VERSION 5.8 ;
BUSBITCHARS "[]" ;
DIVIDERCHAR "/" ;
UNITS
    DATABASE MICRONS 1000 ;
END UNITS

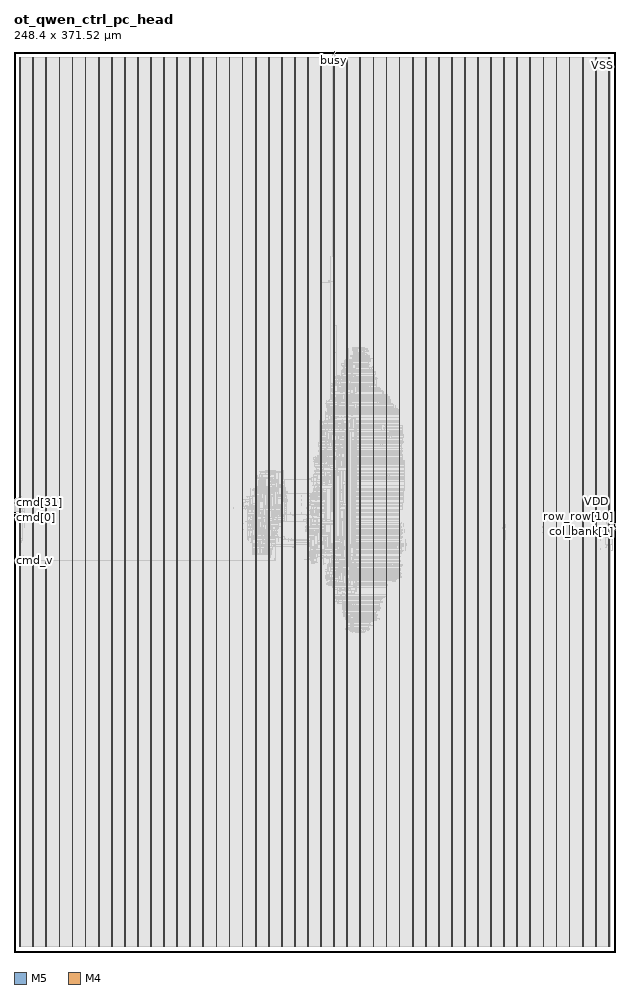
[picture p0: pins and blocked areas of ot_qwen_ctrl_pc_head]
MACRO ot_qwen_ctrl_pc_head
  FOREIGN ot_qwen_ctrl_pc_head 0 0 ;
  CLASS BLOCK ;
  SIZE 248.4 BY 371.52 ;
  PIN busy
    DIRECTION OUTPUT ;
    USE SIGNAL ;
    PORT
      LAYER M5 ;
        RECT  132.144 371.436 132.168 371.52 ;
    END
  END busy
  PIN clk
    DIRECTION INPUT ;
    USE SIGNAL ;
    PORT
      LAYER M5 ;
        RECT  132.24 371.436 132.264 371.52 ;
    END
  END clk
  PIN cmd[0]
    DIRECTION INPUT ;
    USE SIGNAL ;
    PORT
      LAYER M4 ;
        RECT  0 182.64 0.084 182.664 ;
    END
  END cmd[0]
  PIN cmd[10]
    DIRECTION INPUT ;
    USE SIGNAL ;
    PORT
      LAYER M4 ;
        RECT  0 183.6 0.084 183.624 ;
    END
  END cmd[10]
  PIN cmd[11]
    DIRECTION INPUT ;
    USE SIGNAL ;
    PORT
      LAYER M4 ;
        RECT  0 183.696 0.084 183.72 ;
    END
  END cmd[11]
  PIN cmd[12]
    DIRECTION INPUT ;
    USE SIGNAL ;
    PORT
      LAYER M4 ;
        RECT  0 183.792 0.084 183.816 ;
    END
  END cmd[12]
  PIN cmd[13]
    DIRECTION INPUT ;
    USE SIGNAL ;
    PORT
      LAYER M4 ;
        RECT  0 183.888 0.084 183.912 ;
    END
  END cmd[13]
  PIN cmd[14]
    DIRECTION INPUT ;
    USE SIGNAL ;
    PORT
      LAYER M4 ;
        RECT  0 183.984 0.084 184.008 ;
    END
  END cmd[14]
  PIN cmd[15]
    DIRECTION INPUT ;
    USE SIGNAL ;
    PORT
      LAYER M4 ;
        RECT  0 184.08 0.084 184.104 ;
    END
  END cmd[15]
  PIN cmd[16]
    DIRECTION INPUT ;
    USE SIGNAL ;
    PORT
      LAYER M4 ;
        RECT  0 184.176 0.084 184.2 ;
    END
  END cmd[16]
  PIN cmd[17]
    DIRECTION INPUT ;
    USE SIGNAL ;
    PORT
      LAYER M4 ;
        RECT  0 184.272 0.084 184.296 ;
    END
  END cmd[17]
  PIN cmd[18]
    DIRECTION INPUT ;
    USE SIGNAL ;
    PORT
      LAYER M4 ;
        RECT  0 184.368 0.084 184.392 ;
    END
  END cmd[18]
  PIN cmd[19]
    DIRECTION INPUT ;
    USE SIGNAL ;
    PORT
      LAYER M4 ;
        RECT  0 184.464 0.084 184.488 ;
    END
  END cmd[19]
  PIN cmd[1]
    DIRECTION INPUT ;
    USE SIGNAL ;
    PORT
      LAYER M4 ;
        RECT  0 182.736 0.084 182.76 ;
    END
  END cmd[1]
  PIN cmd[20]
    DIRECTION INPUT ;
    USE SIGNAL ;
    PORT
      LAYER M4 ;
        RECT  0 184.56 0.084 184.584 ;
    END
  END cmd[20]
  PIN cmd[21]
    DIRECTION INPUT ;
    USE SIGNAL ;
    PORT
      LAYER M4 ;
        RECT  0 184.656 0.084 184.68 ;
    END
  END cmd[21]
  PIN cmd[22]
    DIRECTION INPUT ;
    USE SIGNAL ;
    PORT
      LAYER M4 ;
        RECT  0 184.752 0.084 184.776 ;
    END
  END cmd[22]
  PIN cmd[23]
    DIRECTION INPUT ;
    USE SIGNAL ;
    PORT
      LAYER M4 ;
        RECT  0 184.848 0.084 184.872 ;
    END
  END cmd[23]
  PIN cmd[24]
    DIRECTION INPUT ;
    USE SIGNAL ;
    PORT
      LAYER M4 ;
        RECT  0 184.944 0.084 184.968 ;
    END
  END cmd[24]
  PIN cmd[25]
    DIRECTION INPUT ;
    USE SIGNAL ;
    PORT
      LAYER M4 ;
        RECT  0 185.04 0.084 185.064 ;
    END
  END cmd[25]
  PIN cmd[26]
    DIRECTION INPUT ;
    USE SIGNAL ;
    PORT
      LAYER M4 ;
        RECT  0 185.136 0.084 185.16 ;
    END
  END cmd[26]
  PIN cmd[27]
    DIRECTION INPUT ;
    USE SIGNAL ;
    PORT
      LAYER M4 ;
        RECT  0 185.232 0.084 185.256 ;
    END
  END cmd[27]
  PIN cmd[28]
    DIRECTION INPUT ;
    USE SIGNAL ;
    PORT
      LAYER M4 ;
        RECT  0 185.328 0.084 185.352 ;
    END
  END cmd[28]
  PIN cmd[29]
    DIRECTION INPUT ;
    USE SIGNAL ;
    PORT
      LAYER M4 ;
        RECT  0 185.424 0.084 185.448 ;
    END
  END cmd[29]
  PIN cmd[2]
    DIRECTION INPUT ;
    USE SIGNAL ;
    PORT
      LAYER M4 ;
        RECT  0 182.832 0.084 182.856 ;
    END
  END cmd[2]
  PIN cmd[30]
    DIRECTION INPUT ;
    USE SIGNAL ;
    PORT
      LAYER M4 ;
        RECT  0 185.52 0.084 185.544 ;
    END
  END cmd[30]
  PIN cmd[31]
    DIRECTION INPUT ;
    USE SIGNAL ;
    PORT
      LAYER M4 ;
        RECT  0 185.616 0.084 185.64 ;
    END
  END cmd[31]
  PIN cmd[3]
    DIRECTION INPUT ;
    USE SIGNAL ;
    PORT
      LAYER M4 ;
        RECT  0 182.928 0.084 182.952 ;
    END
  END cmd[3]
  PIN cmd[4]
    DIRECTION INPUT ;
    USE SIGNAL ;
    PORT
      LAYER M4 ;
        RECT  0 183.024 0.084 183.048 ;
    END
  END cmd[4]
  PIN cmd[5]
    DIRECTION INPUT ;
    USE SIGNAL ;
    PORT
      LAYER M4 ;
        RECT  0 183.12 0.084 183.144 ;
    END
  END cmd[5]
  PIN cmd[6]
    DIRECTION INPUT ;
    USE SIGNAL ;
    PORT
      LAYER M4 ;
        RECT  0 183.216 0.084 183.24 ;
    END
  END cmd[6]
  PIN cmd[7]
    DIRECTION INPUT ;
    USE SIGNAL ;
    PORT
      LAYER M4 ;
        RECT  0 183.312 0.084 183.336 ;
    END
  END cmd[7]
  PIN cmd[8]
    DIRECTION INPUT ;
    USE SIGNAL ;
    PORT
      LAYER M4 ;
        RECT  0 183.408 0.084 183.432 ;
    END
  END cmd[8]
  PIN cmd[9]
    DIRECTION INPUT ;
    USE SIGNAL ;
    PORT
      LAYER M4 ;
        RECT  0 183.504 0.084 183.528 ;
    END
  END cmd[9]
  PIN cmd_credit
    DIRECTION OUTPUT ;
    USE SIGNAL ;
    PORT
      LAYER M4 ;
        RECT  0 161.52 0.084 161.544 ;
    END
  END cmd_credit
  PIN cmd_v
    DIRECTION INPUT ;
    USE SIGNAL ;
    PORT
      LAYER M4 ;
        RECT  0 161.616 0.084 161.64 ;
    END
  END cmd_v
  PIN col_bank[0]
    DIRECTION OUTPUT ;
    USE SIGNAL ;
    PORT
      LAYER M4 ;
        RECT  248.316 173.52 248.4 173.544 ;
    END
  END col_bank[0]
  PIN col_bank[1]
    DIRECTION OUTPUT ;
    USE SIGNAL ;
    PORT
      LAYER M4 ;
        RECT  248.316 173.616 248.4 173.64 ;
    END
  END col_bank[1]
  PIN col_bank[2]
    DIRECTION OUTPUT ;
    USE SIGNAL ;
    PORT
      LAYER M4 ;
        RECT  248.316 173.712 248.4 173.736 ;
    END
  END col_bank[2]
  PIN col_bank[3]
    DIRECTION OUTPUT ;
    USE SIGNAL ;
    PORT
      LAYER M4 ;
        RECT  248.316 173.808 248.4 173.832 ;
    END
  END col_bank[3]
  PIN col_bank[4]
    DIRECTION OUTPUT ;
    USE SIGNAL ;
    PORT
      LAYER M4 ;
        RECT  248.316 173.904 248.4 173.928 ;
    END
  END col_bank[4]
  PIN col_col[0]
    DIRECTION OUTPUT ;
    USE SIGNAL ;
    PORT
      LAYER M4 ;
        RECT  248.316 174 248.4 174.024 ;
    END
  END col_col[0]
  PIN col_col[1]
    DIRECTION OUTPUT ;
    USE SIGNAL ;
    PORT
      LAYER M4 ;
        RECT  248.316 174.096 248.4 174.12 ;
    END
  END col_col[1]
  PIN col_col[2]
    DIRECTION OUTPUT ;
    USE SIGNAL ;
    PORT
      LAYER M4 ;
        RECT  248.316 174.192 248.4 174.216 ;
    END
  END col_col[2]
  PIN col_col[3]
    DIRECTION OUTPUT ;
    USE SIGNAL ;
    PORT
      LAYER M4 ;
        RECT  248.316 174.288 248.4 174.312 ;
    END
  END col_col[3]
  PIN col_col[4]
    DIRECTION OUTPUT ;
    USE SIGNAL ;
    PORT
      LAYER M4 ;
        RECT  248.316 174.384 248.4 174.408 ;
    END
  END col_col[4]
  PIN col_v
    DIRECTION OUTPUT ;
    USE SIGNAL ;
    PORT
      LAYER M4 ;
        RECT  248.316 174.48 248.4 174.504 ;
    END
  END col_v
  PIN col_we
    DIRECTION OUTPUT ;
    USE SIGNAL ;
    PORT
      LAYER M4 ;
        RECT  248.316 174.576 248.4 174.6 ;
    END
  END col_we
  PIN fault
    DIRECTION OUTPUT ;
    USE SIGNAL ;
    PORT
      LAYER M5 ;
        RECT  132.336 371.436 132.36 371.52 ;
    END
  END fault
  PIN read_credit[0]
    DIRECTION INPUT ;
    USE SIGNAL ;
    PORT
      LAYER M4 ;
        RECT  0 161.712 0.084 161.736 ;
    END
  END read_credit[0]
  PIN read_credit[1]
    DIRECTION INPUT ;
    USE SIGNAL ;
    PORT
      LAYER M4 ;
        RECT  0 161.808 0.084 161.832 ;
    END
  END read_credit[1]
  PIN read_credit[2]
    DIRECTION INPUT ;
    USE SIGNAL ;
    PORT
      LAYER M4 ;
        RECT  0 161.904 0.084 161.928 ;
    END
  END read_credit[2]
  PIN row_bank[0]
    DIRECTION OUTPUT ;
    USE SIGNAL ;
    PORT
      LAYER M4 ;
        RECT  248.316 174.672 248.4 174.696 ;
    END
  END row_bank[0]
  PIN row_bank[1]
    DIRECTION OUTPUT ;
    USE SIGNAL ;
    PORT
      LAYER M4 ;
        RECT  248.316 174.768 248.4 174.792 ;
    END
  END row_bank[1]
  PIN row_bank[2]
    DIRECTION OUTPUT ;
    USE SIGNAL ;
    PORT
      LAYER M4 ;
        RECT  248.316 174.864 248.4 174.888 ;
    END
  END row_bank[2]
  PIN row_bank[3]
    DIRECTION OUTPUT ;
    USE SIGNAL ;
    PORT
      LAYER M4 ;
        RECT  248.316 174.96 248.4 174.984 ;
    END
  END row_bank[3]
  PIN row_bank[4]
    DIRECTION OUTPUT ;
    USE SIGNAL ;
    PORT
      LAYER M4 ;
        RECT  248.316 175.056 248.4 175.08 ;
    END
  END row_bank[4]
  PIN row_op[0]
    DIRECTION OUTPUT ;
    USE SIGNAL ;
    PORT
      LAYER M4 ;
        RECT  248.316 175.152 248.4 175.176 ;
    END
  END row_op[0]
  PIN row_op[1]
    DIRECTION OUTPUT ;
    USE SIGNAL ;
    PORT
      LAYER M4 ;
        RECT  248.316 175.248 248.4 175.272 ;
    END
  END row_op[1]
  PIN row_op[2]
    DIRECTION OUTPUT ;
    USE SIGNAL ;
    PORT
      LAYER M4 ;
        RECT  248.316 175.344 248.4 175.368 ;
    END
  END row_op[2]
  PIN row_row[0]
    DIRECTION OUTPUT ;
    USE SIGNAL ;
    PORT
      LAYER M4 ;
        RECT  248.316 175.44 248.4 175.464 ;
    END
  END row_row[0]
  PIN row_row[10]
    DIRECTION OUTPUT ;
    USE SIGNAL ;
    PORT
      LAYER M4 ;
        RECT  248.316 176.4 248.4 176.424 ;
    END
  END row_row[10]
  PIN row_row[11]
    DIRECTION OUTPUT ;
    USE SIGNAL ;
    PORT
      LAYER M4 ;
        RECT  248.316 176.496 248.4 176.52 ;
    END
  END row_row[11]
  PIN row_row[12]
    DIRECTION OUTPUT ;
    USE SIGNAL ;
    PORT
      LAYER M4 ;
        RECT  248.316 179.664 248.4 179.688 ;
    END
  END row_row[12]
  PIN row_row[13]
    DIRECTION OUTPUT ;
    USE SIGNAL ;
    PORT
      LAYER M4 ;
        RECT  248.316 179.76 248.4 179.784 ;
    END
  END row_row[13]
  PIN row_row[14]
    DIRECTION OUTPUT ;
    USE SIGNAL ;
    PORT
      LAYER M4 ;
        RECT  248.316 179.856 248.4 179.88 ;
    END
  END row_row[14]
  PIN row_row[15]
    DIRECTION OUTPUT ;
    USE SIGNAL ;
    PORT
      LAYER M4 ;
        RECT  248.316 179.952 248.4 179.976 ;
    END
  END row_row[15]
  PIN row_row[16]
    DIRECTION OUTPUT ;
    USE SIGNAL ;
    PORT
      LAYER M4 ;
        RECT  248.316 180.048 248.4 180.072 ;
    END
  END row_row[16]
  PIN row_row[17]
    DIRECTION OUTPUT ;
    USE SIGNAL ;
    PORT
      LAYER M4 ;
        RECT  248.316 180.144 248.4 180.168 ;
    END
  END row_row[17]
  PIN row_row[18]
    DIRECTION OUTPUT ;
    USE SIGNAL ;
    PORT
      LAYER M4 ;
        RECT  248.316 180.24 248.4 180.264 ;
    END
  END row_row[18]
  PIN row_row[1]
    DIRECTION OUTPUT ;
    USE SIGNAL ;
    PORT
      LAYER M4 ;
        RECT  248.316 175.536 248.4 175.56 ;
    END
  END row_row[1]
  PIN row_row[2]
    DIRECTION OUTPUT ;
    USE SIGNAL ;
    PORT
      LAYER M4 ;
        RECT  248.316 175.632 248.4 175.656 ;
    END
  END row_row[2]
  PIN row_row[3]
    DIRECTION OUTPUT ;
    USE SIGNAL ;
    PORT
      LAYER M4 ;
        RECT  248.316 175.728 248.4 175.752 ;
    END
  END row_row[3]
  PIN row_row[4]
    DIRECTION OUTPUT ;
    USE SIGNAL ;
    PORT
      LAYER M4 ;
        RECT  248.316 175.824 248.4 175.848 ;
    END
  END row_row[4]
  PIN row_row[5]
    DIRECTION OUTPUT ;
    USE SIGNAL ;
    PORT
      LAYER M4 ;
        RECT  248.316 175.92 248.4 175.944 ;
    END
  END row_row[5]
  PIN row_row[6]
    DIRECTION OUTPUT ;
    USE SIGNAL ;
    PORT
      LAYER M4 ;
        RECT  248.316 176.016 248.4 176.04 ;
    END
  END row_row[6]
  PIN row_row[7]
    DIRECTION OUTPUT ;
    USE SIGNAL ;
    PORT
      LAYER M4 ;
        RECT  248.316 176.112 248.4 176.136 ;
    END
  END row_row[7]
  PIN row_row[8]
    DIRECTION OUTPUT ;
    USE SIGNAL ;
    PORT
      LAYER M4 ;
        RECT  248.316 176.208 248.4 176.232 ;
    END
  END row_row[8]
  PIN row_row[9]
    DIRECTION OUTPUT ;
    USE SIGNAL ;
    PORT
      LAYER M4 ;
        RECT  248.316 176.304 248.4 176.328 ;
    END
  END row_row[9]
  PIN row_v
    DIRECTION OUTPUT ;
    USE SIGNAL ;
    PORT
      LAYER M4 ;
        RECT  248.316 180.336 248.4 180.36 ;
    END
  END row_v
  PIN rst_n
    DIRECTION INPUT ;
    USE SIGNAL ;
    PORT
      LAYER M5 ;
        RECT  132.432 371.436 132.456 371.52 ;
    END
  END rst_n
  PIN VDD
    DIRECTION INOUT ;
    USE POWER ;
    PORT
      LAYER M5 ;
        RECT  245.592 2.151 245.712 369.369 ;
        RECT  240.192 2.151 240.312 369.369 ;
        RECT  234.792 2.151 234.912 369.369 ;
        RECT  229.392 2.151 229.512 369.369 ;
        RECT  223.992 2.151 224.112 369.369 ;
        RECT  218.592 2.151 218.712 369.369 ;
        RECT  213.192 2.151 213.312 369.369 ;
        RECT  207.792 2.151 207.912 369.369 ;
        RECT  202.392 2.151 202.512 369.369 ;
        RECT  196.992 2.151 197.112 369.369 ;
        RECT  191.592 2.151 191.712 369.369 ;
        RECT  186.192 2.151 186.312 369.369 ;
        RECT  180.792 2.151 180.912 369.369 ;
        RECT  175.392 2.151 175.512 369.369 ;
        RECT  169.992 2.151 170.112 369.369 ;
        RECT  164.592 2.151 164.712 369.369 ;
        RECT  159.192 2.151 159.312 369.369 ;
        RECT  153.792 2.151 153.912 369.369 ;
        RECT  148.392 2.151 148.512 369.369 ;
        RECT  142.992 2.151 143.112 369.369 ;
        RECT  137.592 2.151 137.712 369.369 ;
        RECT  132.192 2.151 132.312 369.369 ;
        RECT  126.792 2.151 126.912 369.369 ;
        RECT  121.392 2.151 121.512 369.369 ;
        RECT  115.992 2.151 116.112 369.369 ;
        RECT  110.592 2.151 110.712 369.369 ;
        RECT  105.192 2.151 105.312 369.369 ;
        RECT  99.792 2.151 99.912 369.369 ;
        RECT  94.392 2.151 94.512 369.369 ;
        RECT  88.992 2.151 89.112 369.369 ;
        RECT  83.592 2.151 83.712 369.369 ;
        RECT  78.192 2.151 78.312 369.369 ;
        RECT  72.792 2.151 72.912 369.369 ;
        RECT  67.392 2.151 67.512 369.369 ;
        RECT  61.992 2.151 62.112 369.369 ;
        RECT  56.592 2.151 56.712 369.369 ;
        RECT  51.192 2.151 51.312 369.369 ;
        RECT  45.792 2.151 45.912 369.369 ;
        RECT  40.392 2.151 40.512 369.369 ;
        RECT  34.992 2.151 35.112 369.369 ;
        RECT  29.592 2.151 29.712 369.369 ;
        RECT  24.192 2.151 24.312 369.369 ;
        RECT  18.792 2.151 18.912 369.369 ;
        RECT  13.392 2.151 13.512 369.369 ;
        RECT  7.992 2.151 8.112 369.369 ;
        RECT  2.592 2.151 2.712 369.369 ;
    END
  END VDD
  PIN VSS
    DIRECTION INOUT ;
    USE GROUND ;
    PORT
      LAYER M5 ;
        RECT  245.4 2.137 245.52 369.383 ;
        RECT  240 2.137 240.12 369.383 ;
        RECT  234.6 2.137 234.72 369.383 ;
        RECT  229.2 2.137 229.32 369.383 ;
        RECT  223.8 2.137 223.92 369.383 ;
        RECT  218.4 2.137 218.52 369.383 ;
        RECT  213 2.137 213.12 369.383 ;
        RECT  207.6 2.137 207.72 369.383 ;
        RECT  202.2 2.137 202.32 369.383 ;
        RECT  196.8 2.137 196.92 369.383 ;
        RECT  191.4 2.137 191.52 369.383 ;
        RECT  186 2.137 186.12 369.383 ;
        RECT  180.6 2.137 180.72 369.383 ;
        RECT  175.2 2.137 175.32 369.383 ;
        RECT  169.8 2.137 169.92 369.383 ;
        RECT  164.4 2.137 164.52 369.383 ;
        RECT  159 2.137 159.12 369.383 ;
        RECT  153.6 2.137 153.72 369.383 ;
        RECT  148.2 2.137 148.32 369.383 ;
        RECT  142.8 2.137 142.92 369.383 ;
        RECT  137.4 2.137 137.52 369.383 ;
        RECT  132 2.137 132.12 369.383 ;
        RECT  126.6 2.137 126.72 369.383 ;
        RECT  121.2 2.137 121.32 369.383 ;
        RECT  115.8 2.137 115.92 369.383 ;
        RECT  110.4 2.137 110.52 369.383 ;
        RECT  105 2.137 105.12 369.383 ;
        RECT  99.6 2.137 99.72 369.383 ;
        RECT  94.2 2.137 94.32 369.383 ;
        RECT  88.8 2.137 88.92 369.383 ;
        RECT  83.4 2.137 83.52 369.383 ;
        RECT  78 2.137 78.12 369.383 ;
        RECT  72.6 2.137 72.72 369.383 ;
        RECT  67.2 2.137 67.32 369.383 ;
        RECT  61.8 2.137 61.92 369.383 ;
        RECT  56.4 2.137 56.52 369.383 ;
        RECT  51 2.137 51.12 369.383 ;
        RECT  45.6 2.137 45.72 369.383 ;
        RECT  40.2 2.137 40.32 369.383 ;
        RECT  34.8 2.137 34.92 369.383 ;
        RECT  29.4 2.137 29.52 369.383 ;
        RECT  24 2.137 24.12 369.383 ;
        RECT  18.6 2.137 18.72 369.383 ;
        RECT  13.2 2.137 13.32 369.383 ;
        RECT  7.8 2.137 7.92 369.383 ;
        RECT  2.4 2.137 2.52 369.383 ;
    END
  END VSS
  OBS
    LAYER RVTN ;
     RECT  2.16 2.16 246.24 2.295 ;
     RECT  2.16 2.565 246.24 2.835 ;
     RECT  2.16 3.105 246.24 3.375 ;
     RECT  2.16 3.645 246.24 3.915 ;
     RECT  2.16 4.185 246.24 4.455 ;
     RECT  2.16 4.725 246.24 4.995 ;
     RECT  2.16 5.265 246.24 5.535 ;
     RECT  2.16 5.805 246.24 6.075 ;
     RECT  2.16 6.345 246.24 6.615 ;
     RECT  2.16 6.885 246.24 7.155 ;
     RECT  2.16 7.425 246.24 7.695 ;
     RECT  2.16 7.965 246.24 8.235 ;
     RECT  2.16 8.505 246.24 8.775 ;
     RECT  2.16 9.045 246.24 9.315 ;
     RECT  2.16 9.585 246.24 9.855 ;
     RECT  2.16 10.125 246.24 10.395 ;
     RECT  2.16 10.665 246.24 10.935 ;
     RECT  2.16 11.205 246.24 11.475 ;
     RECT  2.16 11.745 246.24 12.015 ;
     RECT  2.16 12.285 246.24 12.555 ;
     RECT  2.16 12.825 246.24 13.095 ;
     RECT  2.16 13.365 246.24 13.635 ;
     RECT  2.16 13.905 246.24 14.175 ;
     RECT  2.16 14.445 246.24 14.715 ;
     RECT  2.16 14.985 246.24 15.255 ;
     RECT  2.16 15.525 246.24 15.795 ;
     RECT  2.16 16.065 246.24 16.335 ;
     RECT  2.16 16.605 246.24 16.875 ;
     RECT  2.16 17.145 246.24 17.415 ;
     RECT  2.16 17.685 246.24 17.955 ;
     RECT  2.16 18.225 246.24 18.495 ;
     RECT  2.16 18.765 246.24 19.035 ;
     RECT  2.16 19.305 246.24 19.575 ;
     RECT  2.16 19.845 246.24 20.115 ;
     RECT  2.16 20.385 246.24 20.655 ;
     RECT  2.16 20.925 246.24 21.195 ;
     RECT  2.16 21.465 246.24 21.735 ;
     RECT  2.16 22.005 246.24 22.275 ;
     RECT  2.16 22.545 246.24 22.815 ;
     RECT  2.16 23.085 246.24 23.355 ;
     RECT  2.16 23.625 246.24 23.895 ;
     RECT  2.16 24.165 246.24 24.435 ;
     RECT  2.16 24.705 246.24 24.975 ;
     RECT  2.16 25.245 246.24 25.515 ;
     RECT  2.16 25.785 246.24 26.055 ;
     RECT  2.16 26.325 246.24 26.595 ;
     RECT  2.16 26.865 246.24 27.135 ;
     RECT  2.16 27.405 246.24 27.675 ;
     RECT  2.16 27.945 246.24 28.215 ;
     RECT  2.16 28.485 246.24 28.755 ;
     RECT  2.16 29.025 246.24 29.295 ;
     RECT  2.16 29.565 246.24 29.835 ;
     RECT  2.16 30.105 246.24 30.375 ;
     RECT  2.16 30.645 246.24 30.915 ;
     RECT  2.16 31.185 246.24 31.455 ;
     RECT  2.16 31.725 246.24 31.995 ;
     RECT  2.16 32.265 246.24 32.535 ;
     RECT  2.16 32.805 246.24 33.075 ;
     RECT  2.16 33.345 246.24 33.615 ;
     RECT  2.16 33.885 246.24 34.155 ;
     RECT  2.16 34.425 246.24 34.695 ;
     RECT  2.16 34.965 246.24 35.235 ;
     RECT  2.16 35.505 246.24 35.775 ;
     RECT  2.16 36.045 246.24 36.315 ;
     RECT  2.16 36.585 246.24 36.855 ;
     RECT  2.16 37.125 246.24 37.395 ;
     RECT  2.16 37.665 246.24 37.935 ;
     RECT  2.16 38.205 246.24 38.475 ;
     RECT  2.16 38.745 246.24 39.015 ;
     RECT  2.16 39.285 246.24 39.555 ;
     RECT  2.16 39.825 246.24 40.095 ;
     RECT  2.16 40.365 246.24 40.635 ;
     RECT  2.16 40.905 246.24 41.175 ;
     RECT  2.16 41.445 246.24 41.715 ;
     RECT  2.16 41.985 246.24 42.255 ;
     RECT  2.16 42.525 246.24 42.795 ;
     RECT  2.16 43.065 246.24 43.335 ;
     RECT  2.16 43.605 246.24 43.875 ;
     RECT  2.16 44.145 246.24 44.415 ;
     RECT  2.16 44.685 246.24 44.955 ;
     RECT  2.16 45.225 246.24 45.495 ;
     RECT  2.16 45.765 246.24 46.035 ;
     RECT  2.16 46.305 246.24 46.575 ;
     RECT  2.16 46.845 246.24 47.115 ;
     RECT  2.16 47.385 246.24 47.655 ;
     RECT  2.16 47.925 246.24 48.195 ;
     RECT  2.16 48.465 246.24 48.735 ;
     RECT  2.16 49.005 246.24 49.275 ;
     RECT  2.16 49.545 246.24 49.815 ;
     RECT  2.16 50.085 246.24 50.355 ;
     RECT  2.16 50.625 246.24 50.895 ;
     RECT  2.16 51.165 246.24 51.435 ;
     RECT  2.16 51.705 246.24 51.975 ;
     RECT  2.16 52.245 246.24 52.515 ;
     RECT  2.16 52.785 246.24 53.055 ;
     RECT  2.16 53.325 246.24 53.595 ;
     RECT  2.16 53.865 246.24 54.135 ;
     RECT  2.16 54.405 246.24 54.675 ;
     RECT  2.16 54.945 246.24 55.215 ;
     RECT  2.16 55.485 246.24 55.755 ;
     RECT  2.16 56.025 246.24 56.295 ;
     RECT  2.16 56.565 246.24 56.835 ;
     RECT  2.16 57.105 246.24 57.375 ;
     RECT  2.16 57.645 246.24 57.915 ;
     RECT  2.16 58.185 246.24 58.455 ;
     RECT  2.16 58.725 246.24 58.995 ;
     RECT  2.16 59.265 246.24 59.535 ;
     RECT  2.16 59.805 246.24 60.075 ;
     RECT  2.16 60.345 246.24 60.615 ;
     RECT  2.16 60.885 246.24 61.155 ;
     RECT  2.16 61.425 246.24 61.695 ;
     RECT  2.16 61.965 246.24 62.235 ;
     RECT  2.16 62.505 246.24 62.775 ;
     RECT  2.16 63.045 246.24 63.315 ;
     RECT  2.16 63.585 246.24 63.855 ;
     RECT  2.16 64.125 246.24 64.395 ;
     RECT  2.16 64.665 246.24 64.935 ;
     RECT  2.16 65.205 246.24 65.475 ;
     RECT  2.16 65.745 246.24 66.015 ;
     RECT  2.16 66.285 246.24 66.555 ;
     RECT  2.16 66.825 246.24 67.095 ;
     RECT  2.16 67.365 246.24 67.635 ;
     RECT  2.16 67.905 246.24 68.175 ;
     RECT  2.16 68.445 246.24 68.715 ;
     RECT  2.16 68.985 246.24 69.255 ;
     RECT  2.16 69.525 246.24 69.795 ;
     RECT  2.16 70.065 246.24 70.335 ;
     RECT  2.16 70.605 246.24 70.875 ;
     RECT  2.16 71.145 246.24 71.415 ;
     RECT  2.16 71.685 246.24 71.955 ;
     RECT  2.16 72.225 246.24 72.495 ;
     RECT  2.16 72.765 246.24 73.035 ;
     RECT  2.16 73.305 246.24 73.575 ;
     RECT  2.16 73.845 246.24 74.115 ;
     RECT  2.16 74.385 246.24 74.655 ;
     RECT  2.16 74.925 246.24 75.195 ;
     RECT  2.16 75.465 246.24 75.735 ;
     RECT  2.16 76.005 246.24 76.275 ;
     RECT  2.16 76.545 246.24 76.815 ;
     RECT  2.16 77.085 246.24 77.355 ;
     RECT  2.16 77.625 246.24 77.895 ;
     RECT  2.16 78.165 246.24 78.435 ;
     RECT  2.16 78.705 246.24 78.975 ;
     RECT  2.16 79.245 246.24 79.515 ;
     RECT  2.16 79.785 246.24 80.055 ;
     RECT  2.16 80.325 246.24 80.595 ;
     RECT  2.16 80.865 246.24 81.135 ;
     RECT  2.16 81.405 246.24 81.675 ;
     RECT  2.16 81.945 246.24 82.215 ;
     RECT  2.16 82.485 246.24 82.755 ;
     RECT  2.16 83.025 246.24 83.295 ;
     RECT  2.16 83.565 246.24 83.835 ;
     RECT  2.16 84.105 246.24 84.375 ;
     RECT  2.16 84.645 246.24 84.915 ;
     RECT  2.16 85.185 246.24 85.455 ;
     RECT  2.16 85.725 246.24 85.995 ;
     RECT  2.16 86.265 246.24 86.535 ;
     RECT  2.16 86.805 246.24 87.075 ;
     RECT  2.16 87.345 246.24 87.615 ;
     RECT  2.16 87.885 246.24 88.155 ;
     RECT  2.16 88.425 246.24 88.695 ;
     RECT  2.16 88.965 246.24 89.235 ;
     RECT  2.16 89.505 246.24 89.775 ;
     RECT  2.16 90.045 246.24 90.315 ;
     RECT  2.16 90.585 246.24 90.855 ;
     RECT  2.16 91.125 246.24 91.395 ;
     RECT  2.16 91.665 246.24 91.935 ;
     RECT  2.16 92.205 246.24 92.475 ;
     RECT  2.16 92.745 246.24 93.015 ;
     RECT  2.16 93.285 246.24 93.555 ;
     RECT  2.16 93.825 246.24 94.095 ;
     RECT  2.16 94.365 246.24 94.635 ;
     RECT  2.16 94.905 246.24 95.175 ;
     RECT  2.16 95.445 246.24 95.715 ;
     RECT  2.16 95.985 246.24 96.255 ;
     RECT  2.16 96.525 246.24 96.795 ;
     RECT  2.16 97.065 246.24 97.335 ;
     RECT  2.16 97.605 246.24 97.875 ;
     RECT  2.16 98.145 246.24 98.415 ;
     RECT  2.16 98.685 246.24 98.955 ;
     RECT  2.16 99.225 246.24 99.495 ;
     RECT  2.16 99.765 246.24 100.035 ;
     RECT  2.16 100.305 246.24 100.575 ;
     RECT  2.16 100.845 246.24 101.115 ;
     RECT  2.16 101.385 246.24 101.655 ;
     RECT  2.16 101.925 246.24 102.195 ;
     RECT  2.16 102.465 246.24 102.735 ;
     RECT  2.16 103.005 246.24 103.275 ;
     RECT  2.16 103.545 246.24 103.815 ;
     RECT  2.16 104.085 246.24 104.355 ;
     RECT  2.16 104.625 246.24 104.895 ;
     RECT  2.16 105.165 246.24 105.435 ;
     RECT  2.16 105.705 246.24 105.975 ;
     RECT  2.16 106.245 246.24 106.515 ;
     RECT  2.16 106.785 246.24 107.055 ;
     RECT  2.16 107.325 246.24 107.595 ;
     RECT  2.16 107.865 246.24 108.135 ;
     RECT  2.16 108.405 246.24 108.675 ;
     RECT  2.16 108.945 246.24 109.215 ;
     RECT  2.16 109.485 246.24 109.755 ;
     RECT  2.16 110.025 246.24 110.295 ;
     RECT  2.16 110.565 246.24 110.835 ;
     RECT  2.16 111.105 246.24 111.375 ;
     RECT  2.16 111.645 246.24 111.915 ;
     RECT  2.16 112.185 246.24 112.455 ;
     RECT  2.16 112.725 246.24 112.995 ;
     RECT  2.16 113.265 246.24 113.535 ;
     RECT  2.16 113.805 246.24 114.075 ;
     RECT  2.16 114.345 246.24 114.615 ;
     RECT  2.16 114.885 246.24 115.155 ;
     RECT  2.16 115.425 246.24 115.695 ;
     RECT  2.16 115.965 246.24 116.235 ;
     RECT  2.16 116.505 246.24 116.775 ;
     RECT  2.16 117.045 246.24 117.315 ;
     RECT  2.16 117.585 246.24 117.855 ;
     RECT  2.16 118.125 246.24 118.395 ;
     RECT  2.16 118.665 246.24 118.935 ;
     RECT  2.16 119.205 246.24 119.475 ;
     RECT  2.16 119.745 246.24 120.015 ;
     RECT  2.16 120.285 246.24 120.555 ;
     RECT  2.16 120.825 246.24 121.095 ;
     RECT  2.16 121.365 246.24 121.635 ;
     RECT  2.16 121.905 246.24 122.175 ;
     RECT  2.16 122.445 246.24 122.715 ;
     RECT  2.16 122.985 246.24 123.255 ;
     RECT  2.16 123.525 246.24 123.795 ;
     RECT  2.16 124.065 246.24 124.335 ;
     RECT  2.16 124.605 246.24 124.875 ;
     RECT  2.16 125.145 246.24 125.415 ;
     RECT  2.16 125.685 246.24 125.955 ;
     RECT  2.16 126.225 246.24 126.495 ;
     RECT  2.16 126.765 246.24 127.035 ;
     RECT  2.16 127.305 246.24 127.575 ;
     RECT  2.16 127.845 246.24 128.115 ;
     RECT  2.16 128.385 246.24 128.655 ;
     RECT  2.16 128.925 246.24 129.195 ;
     RECT  2.16 129.465 246.24 129.735 ;
     RECT  2.16 130.005 246.24 130.275 ;
     RECT  2.16 130.545 246.24 130.815 ;
     RECT  2.16 131.085 246.24 131.355 ;
     RECT  2.16 131.625 246.24 131.895 ;
     RECT  2.16 132.165 246.24 132.435 ;
     RECT  2.16 132.705 246.24 132.975 ;
     RECT  2.16 133.245 246.24 133.515 ;
     RECT  2.16 133.785 246.24 134.055 ;
     RECT  2.16 134.325 246.24 134.595 ;
     RECT  2.16 134.865 246.24 135.135 ;
     RECT  2.16 135.405 246.24 135.675 ;
     RECT  2.16 135.945 246.24 136.215 ;
     RECT  2.16 136.485 246.24 136.755 ;
     RECT  2.16 137.025 246.24 137.295 ;
     RECT  2.16 137.565 246.24 137.835 ;
     RECT  2.16 138.105 246.24 138.375 ;
     RECT  2.16 138.645 246.24 138.915 ;
     RECT  2.16 139.185 246.24 139.455 ;
     RECT  2.16 139.725 246.24 139.995 ;
     RECT  2.16 140.265 246.24 140.535 ;
     RECT  2.16 140.805 246.24 141.075 ;
     RECT  2.16 141.345 246.24 141.615 ;
     RECT  2.16 141.885 246.24 142.155 ;
     RECT  2.16 142.425 246.24 142.695 ;
     RECT  2.16 142.965 246.24 143.235 ;
     RECT  2.16 143.505 246.24 143.775 ;
     RECT  2.16 144.045 246.24 144.315 ;
     RECT  2.16 144.585 246.24 144.855 ;
     RECT  2.16 145.125 246.24 145.395 ;
     RECT  2.16 145.665 246.24 145.935 ;
     RECT  2.16 146.205 246.24 146.475 ;
     RECT  2.16 146.745 246.24 147.015 ;
     RECT  2.16 147.285 246.24 147.555 ;
     RECT  2.16 147.825 246.24 148.095 ;
     RECT  2.16 148.365 246.24 148.635 ;
     RECT  2.16 148.905 246.24 149.175 ;
     RECT  2.16 149.445 246.24 149.715 ;
     RECT  2.16 149.985 246.24 150.255 ;
     RECT  2.16 150.525 246.24 150.795 ;
     RECT  2.16 151.065 246.24 151.335 ;
     RECT  2.16 151.605 246.24 151.875 ;
     RECT  2.16 152.145 246.24 152.415 ;
     RECT  2.16 152.685 246.24 152.955 ;
     RECT  2.16 153.225 246.24 153.495 ;
     RECT  2.16 153.765 246.24 154.035 ;
     RECT  2.16 154.305 246.24 154.575 ;
     RECT  2.16 154.845 246.24 155.115 ;
     RECT  2.16 155.385 246.24 155.655 ;
     RECT  2.16 155.925 246.24 156.195 ;
     RECT  2.16 156.465 246.24 156.735 ;
     RECT  2.16 157.005 246.24 157.275 ;
     RECT  2.16 157.545 246.24 157.815 ;
     RECT  2.16 158.085 246.24 158.355 ;
     RECT  2.16 158.625 246.24 158.895 ;
     RECT  2.16 159.165 246.24 159.435 ;
     RECT  2.16 159.705 246.24 159.975 ;
     RECT  2.16 160.245 246.24 160.515 ;
     RECT  2.16 160.785 246.24 161.055 ;
     RECT  2.16 161.325 246.24 161.595 ;
     RECT  2.16 161.865 246.24 162.135 ;
     RECT  2.16 162.405 246.24 162.675 ;
     RECT  2.16 162.945 246.24 163.215 ;
     RECT  2.16 163.485 246.24 163.755 ;
     RECT  2.16 164.025 246.24 164.295 ;
     RECT  2.16 164.565 246.24 164.835 ;
     RECT  2.16 165.105 246.24 165.375 ;
     RECT  2.16 165.645 246.24 165.915 ;
     RECT  2.16 166.185 246.24 166.455 ;
     RECT  2.16 166.725 246.24 166.995 ;
     RECT  2.16 167.265 246.24 167.535 ;
     RECT  2.16 167.805 246.24 168.075 ;
     RECT  2.16 168.345 246.24 168.615 ;
     RECT  2.16 168.885 246.24 169.155 ;
     RECT  2.16 169.425 246.24 169.695 ;
     RECT  2.16 169.965 246.24 170.235 ;
     RECT  2.16 170.505 246.24 170.775 ;
     RECT  2.16 171.045 246.24 171.315 ;
     RECT  2.16 171.585 246.24 171.855 ;
     RECT  2.16 172.125 246.24 172.395 ;
     RECT  2.16 172.665 246.24 172.935 ;
     RECT  2.16 173.205 246.24 173.475 ;
     RECT  2.16 173.745 246.24 174.015 ;
     RECT  2.16 174.285 246.24 174.555 ;
     RECT  2.16 174.825 246.24 175.095 ;
     RECT  2.16 175.365 246.24 175.635 ;
     RECT  2.16 175.905 246.24 176.175 ;
     RECT  2.16 176.445 246.24 176.715 ;
     RECT  2.16 176.985 246.24 177.255 ;
     RECT  2.16 177.525 246.24 177.795 ;
     RECT  2.16 178.065 246.24 178.335 ;
     RECT  2.16 178.605 246.24 178.875 ;
     RECT  2.16 179.145 246.24 179.415 ;
     RECT  2.16 179.685 246.24 179.955 ;
     RECT  2.16 180.225 246.24 180.495 ;
     RECT  2.16 180.765 246.24 181.035 ;
     RECT  2.16 181.305 246.24 181.575 ;
     RECT  2.16 181.845 246.24 182.115 ;
     RECT  2.16 182.385 246.24 182.655 ;
     RECT  2.16 182.925 246.24 183.195 ;
     RECT  2.16 183.465 246.24 183.735 ;
     RECT  2.16 184.005 246.24 184.275 ;
     RECT  2.16 184.545 246.24 184.815 ;
     RECT  2.16 185.085 246.24 185.355 ;
     RECT  2.16 185.625 246.24 185.895 ;
     RECT  2.16 186.165 246.24 186.435 ;
     RECT  2.16 186.705 246.24 186.975 ;
     RECT  2.16 187.245 246.24 187.515 ;
     RECT  2.16 187.785 246.24 188.055 ;
     RECT  2.16 188.325 246.24 188.595 ;
     RECT  2.16 188.865 246.24 189.135 ;
     RECT  2.16 189.405 246.24 189.675 ;
     RECT  2.16 189.945 246.24 190.215 ;
     RECT  2.16 190.485 246.24 190.755 ;
     RECT  2.16 191.025 246.24 191.295 ;
     RECT  2.16 191.565 246.24 191.835 ;
     RECT  2.16 192.105 246.24 192.375 ;
     RECT  2.16 192.645 246.24 192.915 ;
     RECT  2.16 193.185 246.24 193.455 ;
     RECT  2.16 193.725 246.24 193.995 ;
     RECT  2.16 194.265 246.24 194.535 ;
     RECT  2.16 194.805 246.24 195.075 ;
     RECT  2.16 195.345 246.24 195.615 ;
     RECT  2.16 195.885 246.24 196.155 ;
     RECT  2.16 196.425 246.24 196.695 ;
     RECT  2.16 196.965 246.24 197.235 ;
     RECT  2.16 197.505 246.24 197.775 ;
     RECT  2.16 198.045 246.24 198.315 ;
     RECT  2.16 198.585 246.24 198.855 ;
     RECT  2.16 199.125 246.24 199.395 ;
     RECT  2.16 199.665 246.24 199.935 ;
     RECT  2.16 200.205 246.24 200.475 ;
     RECT  2.16 200.745 246.24 201.015 ;
     RECT  2.16 201.285 246.24 201.555 ;
     RECT  2.16 201.825 246.24 202.095 ;
     RECT  2.16 202.365 246.24 202.635 ;
     RECT  2.16 202.905 246.24 203.175 ;
     RECT  2.16 203.445 246.24 203.715 ;
     RECT  2.16 203.985 246.24 204.255 ;
     RECT  2.16 204.525 246.24 204.795 ;
     RECT  2.16 205.065 246.24 205.335 ;
     RECT  2.16 205.605 246.24 205.875 ;
     RECT  2.16 206.145 246.24 206.415 ;
     RECT  2.16 206.685 246.24 206.955 ;
     RECT  2.16 207.225 246.24 207.495 ;
     RECT  2.16 207.765 246.24 208.035 ;
     RECT  2.16 208.305 246.24 208.575 ;
     RECT  2.16 208.845 246.24 209.115 ;
     RECT  2.16 209.385 246.24 209.655 ;
     RECT  2.16 209.925 246.24 210.195 ;
     RECT  2.16 210.465 246.24 210.735 ;
     RECT  2.16 211.005 246.24 211.275 ;
     RECT  2.16 211.545 246.24 211.815 ;
     RECT  2.16 212.085 246.24 212.355 ;
     RECT  2.16 212.625 246.24 212.895 ;
     RECT  2.16 213.165 246.24 213.435 ;
     RECT  2.16 213.705 246.24 213.975 ;
     RECT  2.16 214.245 246.24 214.515 ;
     RECT  2.16 214.785 246.24 215.055 ;
     RECT  2.16 215.325 246.24 215.595 ;
     RECT  2.16 215.865 246.24 216.135 ;
     RECT  2.16 216.405 246.24 216.675 ;
     RECT  2.16 216.945 246.24 217.215 ;
     RECT  2.16 217.485 246.24 217.755 ;
     RECT  2.16 218.025 246.24 218.295 ;
     RECT  2.16 218.565 246.24 218.835 ;
     RECT  2.16 219.105 246.24 219.375 ;
     RECT  2.16 219.645 246.24 219.915 ;
     RECT  2.16 220.185 246.24 220.455 ;
     RECT  2.16 220.725 246.24 220.995 ;
     RECT  2.16 221.265 246.24 221.535 ;
     RECT  2.16 221.805 246.24 222.075 ;
     RECT  2.16 222.345 246.24 222.615 ;
     RECT  2.16 222.885 246.24 223.155 ;
     RECT  2.16 223.425 246.24 223.695 ;
     RECT  2.16 223.965 246.24 224.235 ;
     RECT  2.16 224.505 246.24 224.775 ;
     RECT  2.16 225.045 246.24 225.315 ;
     RECT  2.16 225.585 246.24 225.855 ;
     RECT  2.16 226.125 246.24 226.395 ;
     RECT  2.16 226.665 246.24 226.935 ;
     RECT  2.16 227.205 246.24 227.475 ;
     RECT  2.16 227.745 246.24 228.015 ;
     RECT  2.16 228.285 246.24 228.555 ;
     RECT  2.16 228.825 246.24 229.095 ;
     RECT  2.16 229.365 246.24 229.635 ;
     RECT  2.16 229.905 246.24 230.175 ;
     RECT  2.16 230.445 246.24 230.715 ;
     RECT  2.16 230.985 246.24 231.255 ;
     RECT  2.16 231.525 246.24 231.795 ;
     RECT  2.16 232.065 246.24 232.335 ;
     RECT  2.16 232.605 246.24 232.875 ;
     RECT  2.16 233.145 246.24 233.415 ;
     RECT  2.16 233.685 246.24 233.955 ;
     RECT  2.16 234.225 246.24 234.495 ;
     RECT  2.16 234.765 246.24 235.035 ;
     RECT  2.16 235.305 246.24 235.575 ;
     RECT  2.16 235.845 246.24 236.115 ;
     RECT  2.16 236.385 246.24 236.655 ;
     RECT  2.16 236.925 246.24 237.195 ;
     RECT  2.16 237.465 246.24 237.735 ;
     RECT  2.16 238.005 246.24 238.275 ;
     RECT  2.16 238.545 246.24 238.815 ;
     RECT  2.16 239.085 246.24 239.355 ;
     RECT  2.16 239.625 246.24 239.895 ;
     RECT  2.16 240.165 246.24 240.435 ;
     RECT  2.16 240.705 246.24 240.975 ;
     RECT  2.16 241.245 246.24 241.515 ;
     RECT  2.16 241.785 246.24 242.055 ;
     RECT  2.16 242.325 246.24 242.595 ;
     RECT  2.16 242.865 246.24 243.135 ;
     RECT  2.16 243.405 246.24 243.675 ;
     RECT  2.16 243.945 246.24 244.215 ;
     RECT  2.16 244.485 246.24 244.755 ;
     RECT  2.16 245.025 246.24 245.295 ;
     RECT  2.16 245.565 246.24 245.835 ;
     RECT  2.16 246.105 246.24 246.375 ;
     RECT  2.16 246.645 246.24 246.915 ;
     RECT  2.16 247.185 246.24 247.455 ;
     RECT  2.16 247.725 246.24 247.995 ;
     RECT  2.16 248.265 246.24 248.535 ;
     RECT  2.16 248.805 246.24 249.075 ;
     RECT  2.16 249.345 246.24 249.615 ;
     RECT  2.16 249.885 246.24 250.155 ;
     RECT  2.16 250.425 246.24 250.695 ;
     RECT  2.16 250.965 246.24 251.235 ;
     RECT  2.16 251.505 246.24 251.775 ;
     RECT  2.16 252.045 246.24 252.315 ;
     RECT  2.16 252.585 246.24 252.855 ;
     RECT  2.16 253.125 246.24 253.395 ;
     RECT  2.16 253.665 246.24 253.935 ;
     RECT  2.16 254.205 246.24 254.475 ;
     RECT  2.16 254.745 246.24 255.015 ;
     RECT  2.16 255.285 246.24 255.555 ;
     RECT  2.16 255.825 246.24 256.095 ;
     RECT  2.16 256.365 246.24 256.635 ;
     RECT  2.16 256.905 246.24 257.175 ;
     RECT  2.16 257.445 246.24 257.715 ;
     RECT  2.16 257.985 246.24 258.255 ;
     RECT  2.16 258.525 246.24 258.795 ;
     RECT  2.16 259.065 246.24 259.335 ;
     RECT  2.16 259.605 246.24 259.875 ;
     RECT  2.16 260.145 246.24 260.415 ;
     RECT  2.16 260.685 246.24 260.955 ;
     RECT  2.16 261.225 246.24 261.495 ;
     RECT  2.16 261.765 246.24 262.035 ;
     RECT  2.16 262.305 246.24 262.575 ;
     RECT  2.16 262.845 246.24 263.115 ;
     RECT  2.16 263.385 246.24 263.655 ;
     RECT  2.16 263.925 246.24 264.195 ;
     RECT  2.16 264.465 246.24 264.735 ;
     RECT  2.16 265.005 246.24 265.275 ;
     RECT  2.16 265.545 246.24 265.815 ;
     RECT  2.16 266.085 246.24 266.355 ;
     RECT  2.16 266.625 246.24 266.895 ;
     RECT  2.16 267.165 246.24 267.435 ;
     RECT  2.16 267.705 246.24 267.975 ;
     RECT  2.16 268.245 246.24 268.515 ;
     RECT  2.16 268.785 246.24 269.055 ;
     RECT  2.16 269.325 246.24 269.595 ;
     RECT  2.16 269.865 246.24 270.135 ;
     RECT  2.16 270.405 246.24 270.675 ;
     RECT  2.16 270.945 246.24 271.215 ;
     RECT  2.16 271.485 246.24 271.755 ;
     RECT  2.16 272.025 246.24 272.295 ;
     RECT  2.16 272.565 246.24 272.835 ;
     RECT  2.16 273.105 246.24 273.375 ;
     RECT  2.16 273.645 246.24 273.915 ;
     RECT  2.16 274.185 246.24 274.455 ;
     RECT  2.16 274.725 246.24 274.995 ;
     RECT  2.16 275.265 246.24 275.535 ;
     RECT  2.16 275.805 246.24 276.075 ;
     RECT  2.16 276.345 246.24 276.615 ;
     RECT  2.16 276.885 246.24 277.155 ;
     RECT  2.16 277.425 246.24 277.695 ;
     RECT  2.16 277.965 246.24 278.235 ;
     RECT  2.16 278.505 246.24 278.775 ;
     RECT  2.16 279.045 246.24 279.315 ;
     RECT  2.16 279.585 246.24 279.855 ;
     RECT  2.16 280.125 246.24 280.395 ;
     RECT  2.16 280.665 246.24 280.935 ;
     RECT  2.16 281.205 246.24 281.475 ;
     RECT  2.16 281.745 246.24 282.015 ;
     RECT  2.16 282.285 246.24 282.555 ;
     RECT  2.16 282.825 246.24 283.095 ;
     RECT  2.16 283.365 246.24 283.635 ;
     RECT  2.16 283.905 246.24 284.175 ;
     RECT  2.16 284.445 246.24 284.715 ;
     RECT  2.16 284.985 246.24 285.255 ;
     RECT  2.16 285.525 246.24 285.795 ;
     RECT  2.16 286.065 246.24 286.335 ;
     RECT  2.16 286.605 246.24 286.875 ;
     RECT  2.16 287.145 246.24 287.415 ;
     RECT  2.16 287.685 246.24 287.955 ;
     RECT  2.16 288.225 246.24 288.495 ;
     RECT  2.16 288.765 246.24 289.035 ;
     RECT  2.16 289.305 246.24 289.575 ;
     RECT  2.16 289.845 246.24 290.115 ;
     RECT  2.16 290.385 246.24 290.655 ;
     RECT  2.16 290.925 246.24 291.195 ;
     RECT  2.16 291.465 246.24 291.735 ;
     RECT  2.16 292.005 246.24 292.275 ;
     RECT  2.16 292.545 246.24 292.815 ;
     RECT  2.16 293.085 246.24 293.355 ;
     RECT  2.16 293.625 246.24 293.895 ;
     RECT  2.16 294.165 246.24 294.435 ;
     RECT  2.16 294.705 246.24 294.975 ;
     RECT  2.16 295.245 246.24 295.515 ;
     RECT  2.16 295.785 246.24 296.055 ;
     RECT  2.16 296.325 246.24 296.595 ;
     RECT  2.16 296.865 246.24 297.135 ;
     RECT  2.16 297.405 246.24 297.675 ;
     RECT  2.16 297.945 246.24 298.215 ;
     RECT  2.16 298.485 246.24 298.755 ;
     RECT  2.16 299.025 246.24 299.295 ;
     RECT  2.16 299.565 246.24 299.835 ;
     RECT  2.16 300.105 246.24 300.375 ;
     RECT  2.16 300.645 246.24 300.915 ;
     RECT  2.16 301.185 246.24 301.455 ;
     RECT  2.16 301.725 246.24 301.995 ;
     RECT  2.16 302.265 246.24 302.535 ;
     RECT  2.16 302.805 246.24 303.075 ;
     RECT  2.16 303.345 246.24 303.615 ;
     RECT  2.16 303.885 246.24 304.155 ;
     RECT  2.16 304.425 246.24 304.695 ;
     RECT  2.16 304.965 246.24 305.235 ;
     RECT  2.16 305.505 246.24 305.775 ;
     RECT  2.16 306.045 246.24 306.315 ;
     RECT  2.16 306.585 246.24 306.855 ;
     RECT  2.16 307.125 246.24 307.395 ;
     RECT  2.16 307.665 246.24 307.935 ;
     RECT  2.16 308.205 246.24 308.475 ;
     RECT  2.16 308.745 246.24 309.015 ;
     RECT  2.16 309.285 246.24 309.555 ;
     RECT  2.16 309.825 246.24 310.095 ;
     RECT  2.16 310.365 246.24 310.635 ;
     RECT  2.16 310.905 246.24 311.175 ;
     RECT  2.16 311.445 246.24 311.715 ;
     RECT  2.16 311.985 246.24 312.255 ;
     RECT  2.16 312.525 246.24 312.795 ;
     RECT  2.16 313.065 246.24 313.335 ;
     RECT  2.16 313.605 246.24 313.875 ;
     RECT  2.16 314.145 246.24 314.415 ;
     RECT  2.16 314.685 246.24 314.955 ;
     RECT  2.16 315.225 246.24 315.495 ;
     RECT  2.16 315.765 246.24 316.035 ;
     RECT  2.16 316.305 246.24 316.575 ;
     RECT  2.16 316.845 246.24 317.115 ;
     RECT  2.16 317.385 246.24 317.655 ;
     RECT  2.16 317.925 246.24 318.195 ;
     RECT  2.16 318.465 246.24 318.735 ;
     RECT  2.16 319.005 246.24 319.275 ;
     RECT  2.16 319.545 246.24 319.815 ;
     RECT  2.16 320.085 246.24 320.355 ;
     RECT  2.16 320.625 246.24 320.895 ;
     RECT  2.16 321.165 246.24 321.435 ;
     RECT  2.16 321.705 246.24 321.975 ;
     RECT  2.16 322.245 246.24 322.515 ;
     RECT  2.16 322.785 246.24 323.055 ;
     RECT  2.16 323.325 246.24 323.595 ;
     RECT  2.16 323.865 246.24 324.135 ;
     RECT  2.16 324.405 246.24 324.675 ;
     RECT  2.16 324.945 246.24 325.215 ;
     RECT  2.16 325.485 246.24 325.755 ;
     RECT  2.16 326.025 246.24 326.295 ;
     RECT  2.16 326.565 246.24 326.835 ;
     RECT  2.16 327.105 246.24 327.375 ;
     RECT  2.16 327.645 246.24 327.915 ;
     RECT  2.16 328.185 246.24 328.455 ;
     RECT  2.16 328.725 246.24 328.995 ;
     RECT  2.16 329.265 246.24 329.535 ;
     RECT  2.16 329.805 246.24 330.075 ;
     RECT  2.16 330.345 246.24 330.615 ;
     RECT  2.16 330.885 246.24 331.155 ;
     RECT  2.16 331.425 246.24 331.695 ;
     RECT  2.16 331.965 246.24 332.235 ;
     RECT  2.16 332.505 246.24 332.775 ;
     RECT  2.16 333.045 246.24 333.315 ;
     RECT  2.16 333.585 246.24 333.855 ;
     RECT  2.16 334.125 246.24 334.395 ;
     RECT  2.16 334.665 246.24 334.935 ;
     RECT  2.16 335.205 246.24 335.475 ;
     RECT  2.16 335.745 246.24 336.015 ;
     RECT  2.16 336.285 246.24 336.555 ;
     RECT  2.16 336.825 246.24 337.095 ;
     RECT  2.16 337.365 246.24 337.635 ;
     RECT  2.16 337.905 246.24 338.175 ;
     RECT  2.16 338.445 246.24 338.715 ;
     RECT  2.16 338.985 246.24 339.255 ;
     RECT  2.16 339.525 246.24 339.795 ;
     RECT  2.16 340.065 246.24 340.335 ;
     RECT  2.16 340.605 246.24 340.875 ;
     RECT  2.16 341.145 246.24 341.415 ;
     RECT  2.16 341.685 246.24 341.955 ;
     RECT  2.16 342.225 246.24 342.495 ;
     RECT  2.16 342.765 246.24 343.035 ;
     RECT  2.16 343.305 246.24 343.575 ;
     RECT  2.16 343.845 246.24 344.115 ;
     RECT  2.16 344.385 246.24 344.655 ;
     RECT  2.16 344.925 246.24 345.195 ;
     RECT  2.16 345.465 246.24 345.735 ;
     RECT  2.16 346.005 246.24 346.275 ;
     RECT  2.16 346.545 246.24 346.815 ;
     RECT  2.16 347.085 246.24 347.355 ;
     RECT  2.16 347.625 246.24 347.895 ;
     RECT  2.16 348.165 246.24 348.435 ;
     RECT  2.16 348.705 246.24 348.975 ;
     RECT  2.16 349.245 246.24 349.515 ;
     RECT  2.16 349.785 246.24 350.055 ;
     RECT  2.16 350.325 246.24 350.595 ;
     RECT  2.16 350.865 246.24 351.135 ;
     RECT  2.16 351.405 246.24 351.675 ;
     RECT  2.16 351.945 246.24 352.215 ;
     RECT  2.16 352.485 246.24 352.755 ;
     RECT  2.16 353.025 246.24 353.295 ;
     RECT  2.16 353.565 246.24 353.835 ;
     RECT  2.16 354.105 246.24 354.375 ;
     RECT  2.16 354.645 246.24 354.915 ;
     RECT  2.16 355.185 246.24 355.455 ;
     RECT  2.16 355.725 246.24 355.995 ;
     RECT  2.16 356.265 246.24 356.535 ;
     RECT  2.16 356.805 246.24 357.075 ;
     RECT  2.16 357.345 246.24 357.615 ;
     RECT  2.16 357.885 246.24 358.155 ;
     RECT  2.16 358.425 246.24 358.695 ;
     RECT  2.16 358.965 246.24 359.235 ;
     RECT  2.16 359.505 246.24 359.775 ;
     RECT  2.16 360.045 246.24 360.315 ;
     RECT  2.16 360.585 246.24 360.855 ;
     RECT  2.16 361.125 246.24 361.395 ;
     RECT  2.16 361.665 246.24 361.935 ;
     RECT  2.16 362.205 246.24 362.475 ;
     RECT  2.16 362.745 246.24 363.015 ;
     RECT  2.16 363.285 246.24 363.555 ;
     RECT  2.16 363.825 246.24 364.095 ;
     RECT  2.16 364.365 246.24 364.635 ;
     RECT  2.16 364.905 246.24 365.175 ;
     RECT  2.16 365.445 246.24 365.715 ;
     RECT  2.16 365.985 246.24 366.255 ;
     RECT  2.16 366.525 246.24 366.795 ;
     RECT  2.16 367.065 246.24 367.335 ;
     RECT  2.16 367.605 246.24 367.875 ;
     RECT  2.16 368.145 246.24 368.415 ;
     RECT  2.16 368.685 246.24 368.955 ;
     RECT  2.16 369.225 246.24 369.36 ;
    LAYER RVTP ;
     RECT  2.16 2.295 246.24 2.565 ;
     RECT  2.16 2.835 246.24 3.105 ;
     RECT  2.16 3.375 246.24 3.645 ;
     RECT  2.16 3.915 246.24 4.185 ;
     RECT  2.16 4.455 246.24 4.725 ;
     RECT  2.16 4.995 246.24 5.265 ;
     RECT  2.16 5.535 246.24 5.805 ;
     RECT  2.16 6.075 246.24 6.345 ;
     RECT  2.16 6.615 246.24 6.885 ;
     RECT  2.16 7.155 246.24 7.425 ;
     RECT  2.16 7.695 246.24 7.965 ;
     RECT  2.16 8.235 246.24 8.505 ;
     RECT  2.16 8.775 246.24 9.045 ;
     RECT  2.16 9.315 246.24 9.585 ;
     RECT  2.16 9.855 246.24 10.125 ;
     RECT  2.16 10.395 246.24 10.665 ;
     RECT  2.16 10.935 246.24 11.205 ;
     RECT  2.16 11.475 246.24 11.745 ;
     RECT  2.16 12.015 246.24 12.285 ;
     RECT  2.16 12.555 246.24 12.825 ;
     RECT  2.16 13.095 246.24 13.365 ;
     RECT  2.16 13.635 246.24 13.905 ;
     RECT  2.16 14.175 246.24 14.445 ;
     RECT  2.16 14.715 246.24 14.985 ;
     RECT  2.16 15.255 246.24 15.525 ;
     RECT  2.16 15.795 246.24 16.065 ;
     RECT  2.16 16.335 246.24 16.605 ;
     RECT  2.16 16.875 246.24 17.145 ;
     RECT  2.16 17.415 246.24 17.685 ;
     RECT  2.16 17.955 246.24 18.225 ;
     RECT  2.16 18.495 246.24 18.765 ;
     RECT  2.16 19.035 246.24 19.305 ;
     RECT  2.16 19.575 246.24 19.845 ;
     RECT  2.16 20.115 246.24 20.385 ;
     RECT  2.16 20.655 246.24 20.925 ;
     RECT  2.16 21.195 246.24 21.465 ;
     RECT  2.16 21.735 246.24 22.005 ;
     RECT  2.16 22.275 246.24 22.545 ;
     RECT  2.16 22.815 246.24 23.085 ;
     RECT  2.16 23.355 246.24 23.625 ;
     RECT  2.16 23.895 246.24 24.165 ;
     RECT  2.16 24.435 246.24 24.705 ;
     RECT  2.16 24.975 246.24 25.245 ;
     RECT  2.16 25.515 246.24 25.785 ;
     RECT  2.16 26.055 246.24 26.325 ;
     RECT  2.16 26.595 246.24 26.865 ;
     RECT  2.16 27.135 246.24 27.405 ;
     RECT  2.16 27.675 246.24 27.945 ;
     RECT  2.16 28.215 246.24 28.485 ;
     RECT  2.16 28.755 246.24 29.025 ;
     RECT  2.16 29.295 246.24 29.565 ;
     RECT  2.16 29.835 246.24 30.105 ;
     RECT  2.16 30.375 246.24 30.645 ;
     RECT  2.16 30.915 246.24 31.185 ;
     RECT  2.16 31.455 246.24 31.725 ;
     RECT  2.16 31.995 246.24 32.265 ;
     RECT  2.16 32.535 246.24 32.805 ;
     RECT  2.16 33.075 246.24 33.345 ;
     RECT  2.16 33.615 246.24 33.885 ;
     RECT  2.16 34.155 246.24 34.425 ;
     RECT  2.16 34.695 246.24 34.965 ;
     RECT  2.16 35.235 246.24 35.505 ;
     RECT  2.16 35.775 246.24 36.045 ;
     RECT  2.16 36.315 246.24 36.585 ;
     RECT  2.16 36.855 246.24 37.125 ;
     RECT  2.16 37.395 246.24 37.665 ;
     RECT  2.16 37.935 246.24 38.205 ;
     RECT  2.16 38.475 246.24 38.745 ;
     RECT  2.16 39.015 246.24 39.285 ;
     RECT  2.16 39.555 246.24 39.825 ;
     RECT  2.16 40.095 246.24 40.365 ;
     RECT  2.16 40.635 246.24 40.905 ;
     RECT  2.16 41.175 246.24 41.445 ;
     RECT  2.16 41.715 246.24 41.985 ;
     RECT  2.16 42.255 246.24 42.525 ;
     RECT  2.16 42.795 246.24 43.065 ;
     RECT  2.16 43.335 246.24 43.605 ;
     RECT  2.16 43.875 246.24 44.145 ;
     RECT  2.16 44.415 246.24 44.685 ;
     RECT  2.16 44.955 246.24 45.225 ;
     RECT  2.16 45.495 246.24 45.765 ;
     RECT  2.16 46.035 246.24 46.305 ;
     RECT  2.16 46.575 246.24 46.845 ;
     RECT  2.16 47.115 246.24 47.385 ;
     RECT  2.16 47.655 246.24 47.925 ;
     RECT  2.16 48.195 246.24 48.465 ;
     RECT  2.16 48.735 246.24 49.005 ;
     RECT  2.16 49.275 246.24 49.545 ;
     RECT  2.16 49.815 246.24 50.085 ;
     RECT  2.16 50.355 246.24 50.625 ;
     RECT  2.16 50.895 246.24 51.165 ;
     RECT  2.16 51.435 246.24 51.705 ;
     RECT  2.16 51.975 246.24 52.245 ;
     RECT  2.16 52.515 246.24 52.785 ;
     RECT  2.16 53.055 246.24 53.325 ;
     RECT  2.16 53.595 246.24 53.865 ;
     RECT  2.16 54.135 246.24 54.405 ;
     RECT  2.16 54.675 246.24 54.945 ;
     RECT  2.16 55.215 246.24 55.485 ;
     RECT  2.16 55.755 246.24 56.025 ;
     RECT  2.16 56.295 246.24 56.565 ;
     RECT  2.16 56.835 246.24 57.105 ;
     RECT  2.16 57.375 246.24 57.645 ;
     RECT  2.16 57.915 246.24 58.185 ;
     RECT  2.16 58.455 246.24 58.725 ;
     RECT  2.16 58.995 246.24 59.265 ;
     RECT  2.16 59.535 246.24 59.805 ;
     RECT  2.16 60.075 246.24 60.345 ;
     RECT  2.16 60.615 246.24 60.885 ;
     RECT  2.16 61.155 246.24 61.425 ;
     RECT  2.16 61.695 246.24 61.965 ;
     RECT  2.16 62.235 246.24 62.505 ;
     RECT  2.16 62.775 246.24 63.045 ;
     RECT  2.16 63.315 246.24 63.585 ;
     RECT  2.16 63.855 246.24 64.125 ;
     RECT  2.16 64.395 246.24 64.665 ;
     RECT  2.16 64.935 246.24 65.205 ;
     RECT  2.16 65.475 246.24 65.745 ;
     RECT  2.16 66.015 246.24 66.285 ;
     RECT  2.16 66.555 246.24 66.825 ;
     RECT  2.16 67.095 246.24 67.365 ;
     RECT  2.16 67.635 246.24 67.905 ;
     RECT  2.16 68.175 246.24 68.445 ;
     RECT  2.16 68.715 246.24 68.985 ;
     RECT  2.16 69.255 246.24 69.525 ;
     RECT  2.16 69.795 246.24 70.065 ;
     RECT  2.16 70.335 246.24 70.605 ;
     RECT  2.16 70.875 246.24 71.145 ;
     RECT  2.16 71.415 246.24 71.685 ;
     RECT  2.16 71.955 246.24 72.225 ;
     RECT  2.16 72.495 246.24 72.765 ;
     RECT  2.16 73.035 246.24 73.305 ;
     RECT  2.16 73.575 246.24 73.845 ;
     RECT  2.16 74.115 246.24 74.385 ;
     RECT  2.16 74.655 246.24 74.925 ;
     RECT  2.16 75.195 246.24 75.465 ;
     RECT  2.16 75.735 246.24 76.005 ;
     RECT  2.16 76.275 246.24 76.545 ;
     RECT  2.16 76.815 246.24 77.085 ;
     RECT  2.16 77.355 246.24 77.625 ;
     RECT  2.16 77.895 246.24 78.165 ;
     RECT  2.16 78.435 246.24 78.705 ;
     RECT  2.16 78.975 246.24 79.245 ;
     RECT  2.16 79.515 246.24 79.785 ;
     RECT  2.16 80.055 246.24 80.325 ;
     RECT  2.16 80.595 246.24 80.865 ;
     RECT  2.16 81.135 246.24 81.405 ;
     RECT  2.16 81.675 246.24 81.945 ;
     RECT  2.16 82.215 246.24 82.485 ;
     RECT  2.16 82.755 246.24 83.025 ;
     RECT  2.16 83.295 246.24 83.565 ;
     RECT  2.16 83.835 246.24 84.105 ;
     RECT  2.16 84.375 246.24 84.645 ;
     RECT  2.16 84.915 246.24 85.185 ;
     RECT  2.16 85.455 246.24 85.725 ;
     RECT  2.16 85.995 246.24 86.265 ;
     RECT  2.16 86.535 246.24 86.805 ;
     RECT  2.16 87.075 246.24 87.345 ;
     RECT  2.16 87.615 246.24 87.885 ;
     RECT  2.16 88.155 246.24 88.425 ;
     RECT  2.16 88.695 246.24 88.965 ;
     RECT  2.16 89.235 246.24 89.505 ;
     RECT  2.16 89.775 246.24 90.045 ;
     RECT  2.16 90.315 246.24 90.585 ;
     RECT  2.16 90.855 246.24 91.125 ;
     RECT  2.16 91.395 246.24 91.665 ;
     RECT  2.16 91.935 246.24 92.205 ;
     RECT  2.16 92.475 246.24 92.745 ;
     RECT  2.16 93.015 246.24 93.285 ;
     RECT  2.16 93.555 246.24 93.825 ;
     RECT  2.16 94.095 246.24 94.365 ;
     RECT  2.16 94.635 246.24 94.905 ;
     RECT  2.16 95.175 246.24 95.445 ;
     RECT  2.16 95.715 246.24 95.985 ;
     RECT  2.16 96.255 246.24 96.525 ;
     RECT  2.16 96.795 246.24 97.065 ;
     RECT  2.16 97.335 246.24 97.605 ;
     RECT  2.16 97.875 246.24 98.145 ;
     RECT  2.16 98.415 246.24 98.685 ;
     RECT  2.16 98.955 246.24 99.225 ;
     RECT  2.16 99.495 246.24 99.765 ;
     RECT  2.16 100.035 246.24 100.305 ;
     RECT  2.16 100.575 246.24 100.845 ;
     RECT  2.16 101.115 246.24 101.385 ;
     RECT  2.16 101.655 246.24 101.925 ;
     RECT  2.16 102.195 246.24 102.465 ;
     RECT  2.16 102.735 246.24 103.005 ;
     RECT  2.16 103.275 246.24 103.545 ;
     RECT  2.16 103.815 246.24 104.085 ;
     RECT  2.16 104.355 246.24 104.625 ;
     RECT  2.16 104.895 246.24 105.165 ;
     RECT  2.16 105.435 246.24 105.705 ;
     RECT  2.16 105.975 246.24 106.245 ;
     RECT  2.16 106.515 246.24 106.785 ;
     RECT  2.16 107.055 246.24 107.325 ;
     RECT  2.16 107.595 246.24 107.865 ;
     RECT  2.16 108.135 246.24 108.405 ;
     RECT  2.16 108.675 246.24 108.945 ;
     RECT  2.16 109.215 246.24 109.485 ;
     RECT  2.16 109.755 246.24 110.025 ;
     RECT  2.16 110.295 246.24 110.565 ;
     RECT  2.16 110.835 246.24 111.105 ;
     RECT  2.16 111.375 246.24 111.645 ;
     RECT  2.16 111.915 246.24 112.185 ;
     RECT  2.16 112.455 246.24 112.725 ;
     RECT  2.16 112.995 246.24 113.265 ;
     RECT  2.16 113.535 246.24 113.805 ;
     RECT  2.16 114.075 246.24 114.345 ;
     RECT  2.16 114.615 246.24 114.885 ;
     RECT  2.16 115.155 246.24 115.425 ;
     RECT  2.16 115.695 246.24 115.965 ;
     RECT  2.16 116.235 246.24 116.505 ;
     RECT  2.16 116.775 246.24 117.045 ;
     RECT  2.16 117.315 246.24 117.585 ;
     RECT  2.16 117.855 246.24 118.125 ;
     RECT  2.16 118.395 246.24 118.665 ;
     RECT  2.16 118.935 246.24 119.205 ;
     RECT  2.16 119.475 246.24 119.745 ;
     RECT  2.16 120.015 246.24 120.285 ;
     RECT  2.16 120.555 246.24 120.825 ;
     RECT  2.16 121.095 246.24 121.365 ;
     RECT  2.16 121.635 246.24 121.905 ;
     RECT  2.16 122.175 246.24 122.445 ;
     RECT  2.16 122.715 246.24 122.985 ;
     RECT  2.16 123.255 246.24 123.525 ;
     RECT  2.16 123.795 246.24 124.065 ;
     RECT  2.16 124.335 246.24 124.605 ;
     RECT  2.16 124.875 246.24 125.145 ;
     RECT  2.16 125.415 246.24 125.685 ;
     RECT  2.16 125.955 246.24 126.225 ;
     RECT  2.16 126.495 246.24 126.765 ;
     RECT  2.16 127.035 246.24 127.305 ;
     RECT  2.16 127.575 246.24 127.845 ;
     RECT  2.16 128.115 246.24 128.385 ;
     RECT  2.16 128.655 246.24 128.925 ;
     RECT  2.16 129.195 246.24 129.465 ;
     RECT  2.16 129.735 246.24 130.005 ;
     RECT  2.16 130.275 246.24 130.545 ;
     RECT  2.16 130.815 246.24 131.085 ;
     RECT  2.16 131.355 246.24 131.625 ;
     RECT  2.16 131.895 246.24 132.165 ;
     RECT  2.16 132.435 246.24 132.705 ;
     RECT  2.16 132.975 246.24 133.245 ;
     RECT  2.16 133.515 246.24 133.785 ;
     RECT  2.16 134.055 246.24 134.325 ;
     RECT  2.16 134.595 246.24 134.865 ;
     RECT  2.16 135.135 246.24 135.405 ;
     RECT  2.16 135.675 246.24 135.945 ;
     RECT  2.16 136.215 246.24 136.485 ;
     RECT  2.16 136.755 246.24 137.025 ;
     RECT  2.16 137.295 246.24 137.565 ;
     RECT  2.16 137.835 246.24 138.105 ;
     RECT  2.16 138.375 246.24 138.645 ;
     RECT  2.16 138.915 246.24 139.185 ;
     RECT  2.16 139.455 246.24 139.725 ;
     RECT  2.16 139.995 246.24 140.265 ;
     RECT  2.16 140.535 246.24 140.805 ;
     RECT  2.16 141.075 246.24 141.345 ;
     RECT  2.16 141.615 246.24 141.885 ;
     RECT  2.16 142.155 246.24 142.425 ;
     RECT  2.16 142.695 246.24 142.965 ;
     RECT  2.16 143.235 246.24 143.505 ;
     RECT  2.16 143.775 246.24 144.045 ;
     RECT  2.16 144.315 246.24 144.585 ;
     RECT  2.16 144.855 246.24 145.125 ;
     RECT  2.16 145.395 246.24 145.665 ;
     RECT  2.16 145.935 246.24 146.205 ;
     RECT  2.16 146.475 246.24 146.745 ;
     RECT  2.16 147.015 246.24 147.285 ;
     RECT  2.16 147.555 246.24 147.825 ;
     RECT  2.16 148.095 246.24 148.365 ;
     RECT  2.16 148.635 246.24 148.905 ;
     RECT  2.16 149.175 246.24 149.445 ;
     RECT  2.16 149.715 246.24 149.985 ;
     RECT  2.16 150.255 246.24 150.525 ;
     RECT  2.16 150.795 246.24 151.065 ;
     RECT  2.16 151.335 246.24 151.605 ;
     RECT  2.16 151.875 246.24 152.145 ;
     RECT  2.16 152.415 246.24 152.685 ;
     RECT  2.16 152.955 246.24 153.225 ;
     RECT  2.16 153.495 246.24 153.765 ;
     RECT  2.16 154.035 246.24 154.305 ;
     RECT  2.16 154.575 246.24 154.845 ;
     RECT  2.16 155.115 246.24 155.385 ;
     RECT  2.16 155.655 246.24 155.925 ;
     RECT  2.16 156.195 246.24 156.465 ;
     RECT  2.16 156.735 246.24 157.005 ;
     RECT  2.16 157.275 246.24 157.545 ;
     RECT  2.16 157.815 246.24 158.085 ;
     RECT  2.16 158.355 246.24 158.625 ;
     RECT  2.16 158.895 246.24 159.165 ;
     RECT  2.16 159.435 246.24 159.705 ;
     RECT  2.16 159.975 246.24 160.245 ;
     RECT  2.16 160.515 246.24 160.785 ;
     RECT  2.16 161.055 246.24 161.325 ;
     RECT  2.16 161.595 246.24 161.865 ;
     RECT  2.16 162.135 246.24 162.405 ;
     RECT  2.16 162.675 246.24 162.945 ;
     RECT  2.16 163.215 246.24 163.485 ;
     RECT  2.16 163.755 246.24 164.025 ;
     RECT  2.16 164.295 246.24 164.565 ;
     RECT  2.16 164.835 246.24 165.105 ;
     RECT  2.16 165.375 246.24 165.645 ;
     RECT  2.16 165.915 246.24 166.185 ;
     RECT  2.16 166.455 246.24 166.725 ;
     RECT  2.16 166.995 246.24 167.265 ;
     RECT  2.16 167.535 246.24 167.805 ;
     RECT  2.16 168.075 246.24 168.345 ;
     RECT  2.16 168.615 246.24 168.885 ;
     RECT  2.16 169.155 246.24 169.425 ;
     RECT  2.16 169.695 246.24 169.965 ;
     RECT  2.16 170.235 246.24 170.505 ;
     RECT  2.16 170.775 246.24 171.045 ;
     RECT  2.16 171.315 246.24 171.585 ;
     RECT  2.16 171.855 246.24 172.125 ;
     RECT  2.16 172.395 246.24 172.665 ;
     RECT  2.16 172.935 246.24 173.205 ;
     RECT  2.16 173.475 246.24 173.745 ;
     RECT  2.16 174.015 246.24 174.285 ;
     RECT  2.16 174.555 246.24 174.825 ;
     RECT  2.16 175.095 246.24 175.365 ;
     RECT  2.16 175.635 246.24 175.905 ;
     RECT  2.16 176.175 246.24 176.445 ;
     RECT  2.16 176.715 246.24 176.985 ;
     RECT  2.16 177.255 246.24 177.525 ;
     RECT  2.16 177.795 246.24 178.065 ;
     RECT  2.16 178.335 246.24 178.605 ;
     RECT  2.16 178.875 246.24 179.145 ;
     RECT  2.16 179.415 246.24 179.685 ;
     RECT  2.16 179.955 246.24 180.225 ;
     RECT  2.16 180.495 246.24 180.765 ;
     RECT  2.16 181.035 246.24 181.305 ;
     RECT  2.16 181.575 246.24 181.845 ;
     RECT  2.16 182.115 246.24 182.385 ;
     RECT  2.16 182.655 246.24 182.925 ;
     RECT  2.16 183.195 246.24 183.465 ;
     RECT  2.16 183.735 246.24 184.005 ;
     RECT  2.16 184.275 246.24 184.545 ;
     RECT  2.16 184.815 246.24 185.085 ;
     RECT  2.16 185.355 246.24 185.625 ;
     RECT  2.16 185.895 246.24 186.165 ;
     RECT  2.16 186.435 246.24 186.705 ;
     RECT  2.16 186.975 246.24 187.245 ;
     RECT  2.16 187.515 246.24 187.785 ;
     RECT  2.16 188.055 246.24 188.325 ;
     RECT  2.16 188.595 246.24 188.865 ;
     RECT  2.16 189.135 246.24 189.405 ;
     RECT  2.16 189.675 246.24 189.945 ;
     RECT  2.16 190.215 246.24 190.485 ;
     RECT  2.16 190.755 246.24 191.025 ;
     RECT  2.16 191.295 246.24 191.565 ;
     RECT  2.16 191.835 246.24 192.105 ;
     RECT  2.16 192.375 246.24 192.645 ;
     RECT  2.16 192.915 246.24 193.185 ;
     RECT  2.16 193.455 246.24 193.725 ;
     RECT  2.16 193.995 246.24 194.265 ;
     RECT  2.16 194.535 246.24 194.805 ;
     RECT  2.16 195.075 246.24 195.345 ;
     RECT  2.16 195.615 246.24 195.885 ;
     RECT  2.16 196.155 246.24 196.425 ;
     RECT  2.16 196.695 246.24 196.965 ;
     RECT  2.16 197.235 246.24 197.505 ;
     RECT  2.16 197.775 246.24 198.045 ;
     RECT  2.16 198.315 246.24 198.585 ;
     RECT  2.16 198.855 246.24 199.125 ;
     RECT  2.16 199.395 246.24 199.665 ;
     RECT  2.16 199.935 246.24 200.205 ;
     RECT  2.16 200.475 246.24 200.745 ;
     RECT  2.16 201.015 246.24 201.285 ;
     RECT  2.16 201.555 246.24 201.825 ;
     RECT  2.16 202.095 246.24 202.365 ;
     RECT  2.16 202.635 246.24 202.905 ;
     RECT  2.16 203.175 246.24 203.445 ;
     RECT  2.16 203.715 246.24 203.985 ;
     RECT  2.16 204.255 246.24 204.525 ;
     RECT  2.16 204.795 246.24 205.065 ;
     RECT  2.16 205.335 246.24 205.605 ;
     RECT  2.16 205.875 246.24 206.145 ;
     RECT  2.16 206.415 246.24 206.685 ;
     RECT  2.16 206.955 246.24 207.225 ;
     RECT  2.16 207.495 246.24 207.765 ;
     RECT  2.16 208.035 246.24 208.305 ;
     RECT  2.16 208.575 246.24 208.845 ;
     RECT  2.16 209.115 246.24 209.385 ;
     RECT  2.16 209.655 246.24 209.925 ;
     RECT  2.16 210.195 246.24 210.465 ;
     RECT  2.16 210.735 246.24 211.005 ;
     RECT  2.16 211.275 246.24 211.545 ;
     RECT  2.16 211.815 246.24 212.085 ;
     RECT  2.16 212.355 246.24 212.625 ;
     RECT  2.16 212.895 246.24 213.165 ;
     RECT  2.16 213.435 246.24 213.705 ;
     RECT  2.16 213.975 246.24 214.245 ;
     RECT  2.16 214.515 246.24 214.785 ;
     RECT  2.16 215.055 246.24 215.325 ;
     RECT  2.16 215.595 246.24 215.865 ;
     RECT  2.16 216.135 246.24 216.405 ;
     RECT  2.16 216.675 246.24 216.945 ;
     RECT  2.16 217.215 246.24 217.485 ;
     RECT  2.16 217.755 246.24 218.025 ;
     RECT  2.16 218.295 246.24 218.565 ;
     RECT  2.16 218.835 246.24 219.105 ;
     RECT  2.16 219.375 246.24 219.645 ;
     RECT  2.16 219.915 246.24 220.185 ;
     RECT  2.16 220.455 246.24 220.725 ;
     RECT  2.16 220.995 246.24 221.265 ;
     RECT  2.16 221.535 246.24 221.805 ;
     RECT  2.16 222.075 246.24 222.345 ;
     RECT  2.16 222.615 246.24 222.885 ;
     RECT  2.16 223.155 246.24 223.425 ;
     RECT  2.16 223.695 246.24 223.965 ;
     RECT  2.16 224.235 246.24 224.505 ;
     RECT  2.16 224.775 246.24 225.045 ;
     RECT  2.16 225.315 246.24 225.585 ;
     RECT  2.16 225.855 246.24 226.125 ;
     RECT  2.16 226.395 246.24 226.665 ;
     RECT  2.16 226.935 246.24 227.205 ;
     RECT  2.16 227.475 246.24 227.745 ;
     RECT  2.16 228.015 246.24 228.285 ;
     RECT  2.16 228.555 246.24 228.825 ;
     RECT  2.16 229.095 246.24 229.365 ;
     RECT  2.16 229.635 246.24 229.905 ;
     RECT  2.16 230.175 246.24 230.445 ;
     RECT  2.16 230.715 246.24 230.985 ;
     RECT  2.16 231.255 246.24 231.525 ;
     RECT  2.16 231.795 246.24 232.065 ;
     RECT  2.16 232.335 246.24 232.605 ;
     RECT  2.16 232.875 246.24 233.145 ;
     RECT  2.16 233.415 246.24 233.685 ;
     RECT  2.16 233.955 246.24 234.225 ;
     RECT  2.16 234.495 246.24 234.765 ;
     RECT  2.16 235.035 246.24 235.305 ;
     RECT  2.16 235.575 246.24 235.845 ;
     RECT  2.16 236.115 246.24 236.385 ;
     RECT  2.16 236.655 246.24 236.925 ;
     RECT  2.16 237.195 246.24 237.465 ;
     RECT  2.16 237.735 246.24 238.005 ;
     RECT  2.16 238.275 246.24 238.545 ;
     RECT  2.16 238.815 246.24 239.085 ;
     RECT  2.16 239.355 246.24 239.625 ;
     RECT  2.16 239.895 246.24 240.165 ;
     RECT  2.16 240.435 246.24 240.705 ;
     RECT  2.16 240.975 246.24 241.245 ;
     RECT  2.16 241.515 246.24 241.785 ;
     RECT  2.16 242.055 246.24 242.325 ;
     RECT  2.16 242.595 246.24 242.865 ;
     RECT  2.16 243.135 246.24 243.405 ;
     RECT  2.16 243.675 246.24 243.945 ;
     RECT  2.16 244.215 246.24 244.485 ;
     RECT  2.16 244.755 246.24 245.025 ;
     RECT  2.16 245.295 246.24 245.565 ;
     RECT  2.16 245.835 246.24 246.105 ;
     RECT  2.16 246.375 246.24 246.645 ;
     RECT  2.16 246.915 246.24 247.185 ;
     RECT  2.16 247.455 246.24 247.725 ;
     RECT  2.16 247.995 246.24 248.265 ;
     RECT  2.16 248.535 246.24 248.805 ;
     RECT  2.16 249.075 246.24 249.345 ;
     RECT  2.16 249.615 246.24 249.885 ;
     RECT  2.16 250.155 246.24 250.425 ;
     RECT  2.16 250.695 246.24 250.965 ;
     RECT  2.16 251.235 246.24 251.505 ;
     RECT  2.16 251.775 246.24 252.045 ;
     RECT  2.16 252.315 246.24 252.585 ;
     RECT  2.16 252.855 246.24 253.125 ;
     RECT  2.16 253.395 246.24 253.665 ;
     RECT  2.16 253.935 246.24 254.205 ;
     RECT  2.16 254.475 246.24 254.745 ;
     RECT  2.16 255.015 246.24 255.285 ;
     RECT  2.16 255.555 246.24 255.825 ;
     RECT  2.16 256.095 246.24 256.365 ;
     RECT  2.16 256.635 246.24 256.905 ;
     RECT  2.16 257.175 246.24 257.445 ;
     RECT  2.16 257.715 246.24 257.985 ;
     RECT  2.16 258.255 246.24 258.525 ;
     RECT  2.16 258.795 246.24 259.065 ;
     RECT  2.16 259.335 246.24 259.605 ;
     RECT  2.16 259.875 246.24 260.145 ;
     RECT  2.16 260.415 246.24 260.685 ;
     RECT  2.16 260.955 246.24 261.225 ;
     RECT  2.16 261.495 246.24 261.765 ;
     RECT  2.16 262.035 246.24 262.305 ;
     RECT  2.16 262.575 246.24 262.845 ;
     RECT  2.16 263.115 246.24 263.385 ;
     RECT  2.16 263.655 246.24 263.925 ;
     RECT  2.16 264.195 246.24 264.465 ;
     RECT  2.16 264.735 246.24 265.005 ;
     RECT  2.16 265.275 246.24 265.545 ;
     RECT  2.16 265.815 246.24 266.085 ;
     RECT  2.16 266.355 246.24 266.625 ;
     RECT  2.16 266.895 246.24 267.165 ;
     RECT  2.16 267.435 246.24 267.705 ;
     RECT  2.16 267.975 246.24 268.245 ;
     RECT  2.16 268.515 246.24 268.785 ;
     RECT  2.16 269.055 246.24 269.325 ;
     RECT  2.16 269.595 246.24 269.865 ;
     RECT  2.16 270.135 246.24 270.405 ;
     RECT  2.16 270.675 246.24 270.945 ;
     RECT  2.16 271.215 246.24 271.485 ;
     RECT  2.16 271.755 246.24 272.025 ;
     RECT  2.16 272.295 246.24 272.565 ;
     RECT  2.16 272.835 246.24 273.105 ;
     RECT  2.16 273.375 246.24 273.645 ;
     RECT  2.16 273.915 246.24 274.185 ;
     RECT  2.16 274.455 246.24 274.725 ;
     RECT  2.16 274.995 246.24 275.265 ;
     RECT  2.16 275.535 246.24 275.805 ;
     RECT  2.16 276.075 246.24 276.345 ;
     RECT  2.16 276.615 246.24 276.885 ;
     RECT  2.16 277.155 246.24 277.425 ;
     RECT  2.16 277.695 246.24 277.965 ;
     RECT  2.16 278.235 246.24 278.505 ;
     RECT  2.16 278.775 246.24 279.045 ;
     RECT  2.16 279.315 246.24 279.585 ;
     RECT  2.16 279.855 246.24 280.125 ;
     RECT  2.16 280.395 246.24 280.665 ;
     RECT  2.16 280.935 246.24 281.205 ;
     RECT  2.16 281.475 246.24 281.745 ;
     RECT  2.16 282.015 246.24 282.285 ;
     RECT  2.16 282.555 246.24 282.825 ;
     RECT  2.16 283.095 246.24 283.365 ;
     RECT  2.16 283.635 246.24 283.905 ;
     RECT  2.16 284.175 246.24 284.445 ;
     RECT  2.16 284.715 246.24 284.985 ;
     RECT  2.16 285.255 246.24 285.525 ;
     RECT  2.16 285.795 246.24 286.065 ;
     RECT  2.16 286.335 246.24 286.605 ;
     RECT  2.16 286.875 246.24 287.145 ;
     RECT  2.16 287.415 246.24 287.685 ;
     RECT  2.16 287.955 246.24 288.225 ;
     RECT  2.16 288.495 246.24 288.765 ;
     RECT  2.16 289.035 246.24 289.305 ;
     RECT  2.16 289.575 246.24 289.845 ;
     RECT  2.16 290.115 246.24 290.385 ;
     RECT  2.16 290.655 246.24 290.925 ;
     RECT  2.16 291.195 246.24 291.465 ;
     RECT  2.16 291.735 246.24 292.005 ;
     RECT  2.16 292.275 246.24 292.545 ;
     RECT  2.16 292.815 246.24 293.085 ;
     RECT  2.16 293.355 246.24 293.625 ;
     RECT  2.16 293.895 246.24 294.165 ;
     RECT  2.16 294.435 246.24 294.705 ;
     RECT  2.16 294.975 246.24 295.245 ;
     RECT  2.16 295.515 246.24 295.785 ;
     RECT  2.16 296.055 246.24 296.325 ;
     RECT  2.16 296.595 246.24 296.865 ;
     RECT  2.16 297.135 246.24 297.405 ;
     RECT  2.16 297.675 246.24 297.945 ;
     RECT  2.16 298.215 246.24 298.485 ;
     RECT  2.16 298.755 246.24 299.025 ;
     RECT  2.16 299.295 246.24 299.565 ;
     RECT  2.16 299.835 246.24 300.105 ;
     RECT  2.16 300.375 246.24 300.645 ;
     RECT  2.16 300.915 246.24 301.185 ;
     RECT  2.16 301.455 246.24 301.725 ;
     RECT  2.16 301.995 246.24 302.265 ;
     RECT  2.16 302.535 246.24 302.805 ;
     RECT  2.16 303.075 246.24 303.345 ;
     RECT  2.16 303.615 246.24 303.885 ;
     RECT  2.16 304.155 246.24 304.425 ;
     RECT  2.16 304.695 246.24 304.965 ;
     RECT  2.16 305.235 246.24 305.505 ;
     RECT  2.16 305.775 246.24 306.045 ;
     RECT  2.16 306.315 246.24 306.585 ;
     RECT  2.16 306.855 246.24 307.125 ;
     RECT  2.16 307.395 246.24 307.665 ;
     RECT  2.16 307.935 246.24 308.205 ;
     RECT  2.16 308.475 246.24 308.745 ;
     RECT  2.16 309.015 246.24 309.285 ;
     RECT  2.16 309.555 246.24 309.825 ;
     RECT  2.16 310.095 246.24 310.365 ;
     RECT  2.16 310.635 246.24 310.905 ;
     RECT  2.16 311.175 246.24 311.445 ;
     RECT  2.16 311.715 246.24 311.985 ;
     RECT  2.16 312.255 246.24 312.525 ;
     RECT  2.16 312.795 246.24 313.065 ;
     RECT  2.16 313.335 246.24 313.605 ;
     RECT  2.16 313.875 246.24 314.145 ;
     RECT  2.16 314.415 246.24 314.685 ;
     RECT  2.16 314.955 246.24 315.225 ;
     RECT  2.16 315.495 246.24 315.765 ;
     RECT  2.16 316.035 246.24 316.305 ;
     RECT  2.16 316.575 246.24 316.845 ;
     RECT  2.16 317.115 246.24 317.385 ;
     RECT  2.16 317.655 246.24 317.925 ;
     RECT  2.16 318.195 246.24 318.465 ;
     RECT  2.16 318.735 246.24 319.005 ;
     RECT  2.16 319.275 246.24 319.545 ;
     RECT  2.16 319.815 246.24 320.085 ;
     RECT  2.16 320.355 246.24 320.625 ;
     RECT  2.16 320.895 246.24 321.165 ;
     RECT  2.16 321.435 246.24 321.705 ;
     RECT  2.16 321.975 246.24 322.245 ;
     RECT  2.16 322.515 246.24 322.785 ;
     RECT  2.16 323.055 246.24 323.325 ;
     RECT  2.16 323.595 246.24 323.865 ;
     RECT  2.16 324.135 246.24 324.405 ;
     RECT  2.16 324.675 246.24 324.945 ;
     RECT  2.16 325.215 246.24 325.485 ;
     RECT  2.16 325.755 246.24 326.025 ;
     RECT  2.16 326.295 246.24 326.565 ;
     RECT  2.16 326.835 246.24 327.105 ;
     RECT  2.16 327.375 246.24 327.645 ;
     RECT  2.16 327.915 246.24 328.185 ;
     RECT  2.16 328.455 246.24 328.725 ;
     RECT  2.16 328.995 246.24 329.265 ;
     RECT  2.16 329.535 246.24 329.805 ;
     RECT  2.16 330.075 246.24 330.345 ;
     RECT  2.16 330.615 246.24 330.885 ;
     RECT  2.16 331.155 246.24 331.425 ;
     RECT  2.16 331.695 246.24 331.965 ;
     RECT  2.16 332.235 246.24 332.505 ;
     RECT  2.16 332.775 246.24 333.045 ;
     RECT  2.16 333.315 246.24 333.585 ;
     RECT  2.16 333.855 246.24 334.125 ;
     RECT  2.16 334.395 246.24 334.665 ;
     RECT  2.16 334.935 246.24 335.205 ;
     RECT  2.16 335.475 246.24 335.745 ;
     RECT  2.16 336.015 246.24 336.285 ;
     RECT  2.16 336.555 246.24 336.825 ;
     RECT  2.16 337.095 246.24 337.365 ;
     RECT  2.16 337.635 246.24 337.905 ;
     RECT  2.16 338.175 246.24 338.445 ;
     RECT  2.16 338.715 246.24 338.985 ;
     RECT  2.16 339.255 246.24 339.525 ;
     RECT  2.16 339.795 246.24 340.065 ;
     RECT  2.16 340.335 246.24 340.605 ;
     RECT  2.16 340.875 246.24 341.145 ;
     RECT  2.16 341.415 246.24 341.685 ;
     RECT  2.16 341.955 246.24 342.225 ;
     RECT  2.16 342.495 246.24 342.765 ;
     RECT  2.16 343.035 246.24 343.305 ;
     RECT  2.16 343.575 246.24 343.845 ;
     RECT  2.16 344.115 246.24 344.385 ;
     RECT  2.16 344.655 246.24 344.925 ;
     RECT  2.16 345.195 246.24 345.465 ;
     RECT  2.16 345.735 246.24 346.005 ;
     RECT  2.16 346.275 246.24 346.545 ;
     RECT  2.16 346.815 246.24 347.085 ;
     RECT  2.16 347.355 246.24 347.625 ;
     RECT  2.16 347.895 246.24 348.165 ;
     RECT  2.16 348.435 246.24 348.705 ;
     RECT  2.16 348.975 246.24 349.245 ;
     RECT  2.16 349.515 246.24 349.785 ;
     RECT  2.16 350.055 246.24 350.325 ;
     RECT  2.16 350.595 246.24 350.865 ;
     RECT  2.16 351.135 246.24 351.405 ;
     RECT  2.16 351.675 246.24 351.945 ;
     RECT  2.16 352.215 246.24 352.485 ;
     RECT  2.16 352.755 246.24 353.025 ;
     RECT  2.16 353.295 246.24 353.565 ;
     RECT  2.16 353.835 246.24 354.105 ;
     RECT  2.16 354.375 246.24 354.645 ;
     RECT  2.16 354.915 246.24 355.185 ;
     RECT  2.16 355.455 246.24 355.725 ;
     RECT  2.16 355.995 246.24 356.265 ;
     RECT  2.16 356.535 246.24 356.805 ;
     RECT  2.16 357.075 246.24 357.345 ;
     RECT  2.16 357.615 246.24 357.885 ;
     RECT  2.16 358.155 246.24 358.425 ;
     RECT  2.16 358.695 246.24 358.965 ;
     RECT  2.16 359.235 246.24 359.505 ;
     RECT  2.16 359.775 246.24 360.045 ;
     RECT  2.16 360.315 246.24 360.585 ;
     RECT  2.16 360.855 246.24 361.125 ;
     RECT  2.16 361.395 246.24 361.665 ;
     RECT  2.16 361.935 246.24 362.205 ;
     RECT  2.16 362.475 246.24 362.745 ;
     RECT  2.16 363.015 246.24 363.285 ;
     RECT  2.16 363.555 246.24 363.825 ;
     RECT  2.16 364.095 246.24 364.365 ;
     RECT  2.16 364.635 246.24 364.905 ;
     RECT  2.16 365.175 246.24 365.445 ;
     RECT  2.16 365.715 246.24 365.985 ;
     RECT  2.16 366.255 246.24 366.525 ;
     RECT  2.16 366.795 246.24 367.065 ;
     RECT  2.16 367.335 246.24 367.605 ;
     RECT  2.16 367.875 246.24 368.145 ;
     RECT  2.16 368.415 246.24 368.685 ;
     RECT  2.16 368.955 246.24 369.225 ;
    LAYER M1 ;
     RECT  2.16 2.151 246.24 369.369 ;
    LAYER M2 ;
     RECT  1.975 187.794 2.047 187.812 ;
     RECT  0.535 183.474 2.16 183.492 ;
     RECT  2.047 187.722 2.16 187.812 ;
     RECT  2.16 2.151 246.24 369.369 ;
     RECT  246.24 168.426 246.515 168.444 ;
     RECT  246.24 170.442 246.587 171 ;
     RECT  246.24 179.856 246.767 181.494 ;
     RECT  246.24 172.836 246.839 175.554 ;
     RECT  246.24 165.852 247.091 165.87 ;
     RECT  246.587 170.982 247.127 171 ;
     RECT  246.767 179.856 247.343 180.414 ;
     RECT  246.839 173.646 247.379 175.284 ;
     RECT  246.24 176.418 247.379 176.904 ;
     RECT  247.343 180.126 247.379 180.144 ;
     RECT  246.767 181.476 247.379 181.494 ;
     RECT  247.379 173.79 247.415 175.158 ;
     RECT  246.839 172.836 247.451 172.854 ;
     RECT  247.415 173.79 247.487 173.808 ;
     RECT  247.415 174.6 248.315 175.122 ;
     RECT  247.379 176.886 248.315 176.904 ;
    LAYER M3 ;
     RECT  2.415 2.143 2.505 2.413 ;
     RECT  7.815 2.143 7.905 2.413 ;
     RECT  13.215 2.143 13.305 2.413 ;
     RECT  18.615 2.143 18.705 2.413 ;
     RECT  24.015 2.143 24.105 2.413 ;
     RECT  29.415 2.143 29.505 2.413 ;
     RECT  34.815 2.143 34.905 2.413 ;
     RECT  40.215 2.143 40.305 2.413 ;
     RECT  45.615 2.143 45.705 2.413 ;
     RECT  51.015 2.143 51.105 2.413 ;
     RECT  56.415 2.143 56.505 2.413 ;
     RECT  61.815 2.143 61.905 2.413 ;
     RECT  67.215 2.143 67.305 2.413 ;
     RECT  72.615 2.143 72.705 2.413 ;
     RECT  78.015 2.143 78.105 2.413 ;
     RECT  83.415 2.143 83.505 2.413 ;
     RECT  88.815 2.143 88.905 2.413 ;
     RECT  94.215 2.143 94.305 2.413 ;
     RECT  99.615 2.143 99.705 2.413 ;
     RECT  105.015 2.143 105.105 2.413 ;
     RECT  110.415 2.143 110.505 2.413 ;
     RECT  115.815 2.143 115.905 2.413 ;
     RECT  121.215 2.143 121.305 2.413 ;
     RECT  126.615 2.143 126.705 2.413 ;
     RECT  132.015 2.143 132.105 2.413 ;
     RECT  137.415 2.143 137.505 2.413 ;
     RECT  142.815 2.143 142.905 2.413 ;
     RECT  148.215 2.143 148.305 2.413 ;
     RECT  153.615 2.143 153.705 2.413 ;
     RECT  159.015 2.143 159.105 2.413 ;
     RECT  164.415 2.143 164.505 2.413 ;
     RECT  169.815 2.143 169.905 2.413 ;
     RECT  175.215 2.143 175.305 2.413 ;
     RECT  180.615 2.143 180.705 2.413 ;
     RECT  186.015 2.143 186.105 2.413 ;
     RECT  191.415 2.143 191.505 2.413 ;
     RECT  196.815 2.143 196.905 2.413 ;
     RECT  202.215 2.143 202.305 2.413 ;
     RECT  207.615 2.143 207.705 2.413 ;
     RECT  213.015 2.143 213.105 2.413 ;
     RECT  218.415 2.143 218.505 2.413 ;
     RECT  223.815 2.143 223.905 2.413 ;
     RECT  229.215 2.143 229.305 2.413 ;
     RECT  234.615 2.143 234.705 2.413 ;
     RECT  240.015 2.143 240.105 2.413 ;
     RECT  245.415 2.143 245.505 2.413 ;
     RECT  142.815 2.413 143.097 131.665 ;
     RECT  142.416 131.665 143.097 131.899 ;
     RECT  139.788 131.791 139.806 131.935 ;
     RECT  144.36 131.899 144.378 131.935 ;
     RECT  141.948 131.899 143.097 131.971 ;
     RECT  144.252 131.935 144.378 131.971 ;
     RECT  139.788 131.935 139.914 132.205 ;
     RECT  139.608 132.205 140.238 132.331 ;
     RECT  141.156 131.971 144.702 132.331 ;
     RECT  139.104 132.331 144.702 132.367 ;
     RECT  139.104 132.367 145.134 132.431 ;
     RECT  139.104 132.431 143.406 132.475 ;
     RECT  138.852 132.475 143.406 132.701 ;
     RECT  138.852 132.701 143.154 132.745 ;
     RECT  145.944 132.511 145.962 132.907 ;
     RECT  137.415 2.413 137.697 133.015 ;
     RECT  144.144 132.431 145.134 133.015 ;
     RECT  145.944 132.907 146.214 133.015 ;
     RECT  137.415 133.015 137.754 133.051 ;
     RECT  138.492 132.745 143.154 133.051 ;
     RECT  144.144 133.015 146.214 133.051 ;
     RECT  144.144 133.051 146.682 133.285 ;
     RECT  137.415 133.051 143.154 133.291 ;
     RECT  137.016 133.291 143.154 133.349 ;
     RECT  139.86 133.349 143.154 133.435 ;
     RECT  143.892 133.285 146.682 133.435 ;
     RECT  137.016 133.349 139.122 133.511 ;
     RECT  139.86 133.435 146.682 133.709 ;
     RECT  137.232 133.511 139.122 134.107 ;
     RECT  139.86 133.709 146.214 134.107 ;
     RECT  137.232 134.107 146.214 134.599 ;
     RECT  137.232 134.599 146.934 134.671 ;
     RECT  148.215 2.413 148.497 134.671 ;
     RECT  137.232 134.671 148.497 134.789 ;
     RECT  137.232 134.789 147.186 134.797 ;
     RECT  137.088 134.797 147.186 134.825 ;
     RECT  137.088 134.825 139.086 134.969 ;
     RECT  137.304 134.969 139.086 135.059 ;
     RECT  139.824 134.825 147.186 135.095 ;
     RECT  139.824 135.095 146.646 135.149 ;
     RECT  137.376 135.059 139.086 135.389 ;
     RECT  137.415 135.389 139.086 135.751 ;
     RECT  137.415 135.751 139.194 135.913 ;
     RECT  139.968 135.149 146.646 135.913 ;
     RECT  137.415 135.913 146.646 135.985 ;
     RECT  137.415 135.985 147.366 136.291 ;
     RECT  148.215 134.789 148.497 136.291 ;
     RECT  137.415 136.291 148.497 136.759 ;
     RECT  149.22 136.723 149.238 136.759 ;
     RECT  137.415 136.759 149.238 136.795 ;
     RECT  137.415 136.795 149.31 136.993 ;
     RECT  137.415 136.993 149.706 137.101 ;
     RECT  137.415 137.101 149.814 137.191 ;
     RECT  137.376 137.191 149.814 137.323 ;
     RECT  137.016 137.323 149.814 137.405 ;
     RECT  150.84 137.371 150.858 137.489 ;
     RECT  144.864 137.405 149.814 137.497 ;
     RECT  137.016 137.405 144.09 137.561 ;
     RECT  140.184 137.561 144.09 137.633 ;
     RECT  137.016 137.561 139.446 137.669 ;
     RECT  144.864 137.497 150.318 137.759 ;
     RECT  150.3 137.759 150.318 137.795 ;
     RECT  140.22 137.633 144.09 138.145 ;
     RECT  144.864 137.759 149.562 138.145 ;
     RECT  137.016 137.669 139.05 138.271 ;
     RECT  136.908 138.271 139.05 138.415 ;
     RECT  140.22 138.145 149.562 138.415 ;
     RECT  136.8 138.415 139.05 138.451 ;
     RECT  135.972 138.451 139.05 138.577 ;
     RECT  139.824 138.415 149.562 138.577 ;
     RECT  135.972 138.577 149.562 138.685 ;
     RECT  135.972 138.685 149.67 138.763 ;
     RECT  135.972 138.763 150.102 138.839 ;
     RECT  135.972 138.839 149.85 138.875 ;
     RECT  138.744 138.875 149.85 139.145 ;
     RECT  135.972 138.875 137.862 139.189 ;
     RECT  138.744 139.145 149.562 139.289 ;
     RECT  138.744 139.289 149.346 139.621 ;
     RECT  135.936 139.189 137.862 139.657 ;
     RECT  138.672 139.621 149.346 139.657 ;
     RECT  135.936 139.657 149.346 140.071 ;
     RECT  135.828 140.071 149.778 140.197 ;
     RECT  135.684 140.197 149.778 140.237 ;
     RECT  136.332 140.237 149.778 140.773 ;
     RECT  136.332 140.773 150.426 140.809 ;
     RECT  136.332 140.809 150.858 141.151 ;
     RECT  136.188 141.151 150.858 141.385 ;
     RECT  136.152 141.385 150.858 141.421 ;
     RECT  135.72 141.421 150.858 141.643 ;
     RECT  135.576 141.643 150.858 141.691 ;
     RECT  135.576 141.691 151.038 141.845 ;
     RECT  135.684 141.845 151.038 141.961 ;
     RECT  135.684 141.961 151.11 142.259 ;
     RECT  135.936 142.259 151.11 142.385 ;
     RECT  135.936 142.385 151.038 142.493 ;
     RECT  135.936 142.493 150.93 142.925 ;
     RECT  135.936 142.925 139.338 143.275 ;
     RECT  135.468 143.275 139.338 143.309 ;
     RECT  135.792 143.309 139.338 143.671 ;
     RECT  140.112 142.925 150.93 143.671 ;
     RECT  134.244 143.977 134.262 144.013 ;
     RECT  133.416 143.977 133.434 144.029 ;
     RECT  134.208 144.013 134.262 144.121 ;
     RECT  135.792 143.671 150.93 144.121 ;
     RECT  151.668 144.085 151.686 144.121 ;
     RECT  135.792 144.121 151.686 144.391 ;
     RECT  135.504 144.391 152.262 144.509 ;
     RECT  135.504 144.509 151.542 144.545 ;
     RECT  133.452 144.121 133.47 144.625 ;
     RECT  134.208 144.121 134.406 144.625 ;
     RECT  133.452 144.625 134.406 144.859 ;
     RECT  135.504 144.545 151.218 144.859 ;
     RECT  133.092 144.859 151.218 145.327 ;
     RECT  133.092 145.327 151.578 145.435 ;
     RECT  133.02 145.435 151.578 145.669 ;
     RECT  132.015 2.413 132.297 145.741 ;
     RECT  133.02 145.669 151.614 145.741 ;
     RECT  132.015 145.741 152.154 146.443 ;
     RECT  132.015 146.443 152.766 146.705 ;
     RECT  135.396 146.705 152.766 146.713 ;
     RECT  135.396 146.713 152.838 146.821 ;
     RECT  153.615 2.413 153.897 146.821 ;
     RECT  132.015 146.705 134.658 147.499 ;
     RECT  135.396 146.821 153.897 147.499 ;
     RECT  131.76 147.499 153.897 150.493 ;
     RECT  131.328 150.493 153.897 151.411 ;
     RECT  129.852 151.483 129.87 151.573 ;
     RECT  130.68 151.411 153.99 151.573 ;
     RECT  129.852 151.573 153.99 151.601 ;
     RECT  129.852 151.601 153.897 152.077 ;
     RECT  128.916 152.149 128.934 152.189 ;
     RECT  129.708 152.077 153.897 152.221 ;
     RECT  129.384 152.221 153.897 152.339 ;
     RECT  129.708 152.339 153.897 152.609 ;
     RECT  130.212 152.609 132.93 152.753 ;
     RECT  156.816 152.959 156.834 152.971 ;
     RECT  156.24 152.971 156.834 152.995 ;
     RECT  156.24 152.995 157.122 153.031 ;
     RECT  156.24 153.031 157.446 153.157 ;
     RECT  155.268 153.229 155.286 153.301 ;
     RECT  156.024 153.157 157.446 153.301 ;
     RECT  133.884 152.609 153.897 153.307 ;
     RECT  133.884 153.307 154.422 153.499 ;
     RECT  155.268 153.301 157.446 153.499 ;
     RECT  130.464 152.753 132.93 153.571 ;
     RECT  133.884 153.499 157.446 153.571 ;
     RECT  129.204 153.355 129.222 153.691 ;
     RECT  129.996 153.571 157.446 153.691 ;
     RECT  129.204 153.691 157.446 153.805 ;
     RECT  129.204 153.805 157.842 154.027 ;
     RECT  129.204 154.027 157.914 154.075 ;
     RECT  128.556 154.075 157.914 154.111 ;
     RECT  128.556 154.111 158.202 154.349 ;
     RECT  128.736 154.349 158.202 154.381 ;
     RECT  159.015 2.413 159.297 154.381 ;
     RECT  128.736 154.381 159.297 154.579 ;
     RECT  128.736 154.579 159.57 154.651 ;
     RECT  128.736 154.651 159.93 155.039 ;
     RECT  128.736 155.039 159.606 155.191 ;
     RECT  128.664 155.191 159.606 155.453 ;
     RECT  128.808 155.453 159.39 155.741 ;
     RECT  131.112 155.741 159.39 155.849 ;
     RECT  131.184 155.849 159.39 155.957 ;
     RECT  131.4 155.957 159.39 156.155 ;
     RECT  131.472 156.155 159.39 156.271 ;
     RECT  131.472 156.271 159.966 156.389 ;
     RECT  131.472 156.389 159.57 156.461 ;
     RECT  131.472 156.461 159.462 156.695 ;
     RECT  131.472 156.695 159.297 156.901 ;
     RECT  128.808 155.741 130.122 156.907 ;
     RECT  128.556 156.907 130.122 156.937 ;
     RECT  130.896 156.901 159.297 156.937 ;
     RECT  128.556 156.937 159.297 156.965 ;
     RECT  129.06 156.965 159.297 157.109 ;
     RECT  160.02 157.351 160.038 157.469 ;
     RECT  129.348 157.109 159.297 157.477 ;
     RECT  129.348 157.477 159.642 157.541 ;
     RECT  129.348 157.541 159.57 157.891 ;
     RECT  128.88 157.891 159.57 157.963 ;
     RECT  128.736 157.963 159.57 158.009 ;
     RECT  129.456 158.009 159.57 158.045 ;
     RECT  129.564 158.045 159.57 158.315 ;
     RECT  129.564 158.315 159.297 159.019 ;
     RECT  129.384 159.019 159.297 159.169 ;
     RECT  129.384 159.169 159.822 159.359 ;
     RECT  156.744 159.359 159.822 159.475 ;
     RECT  156.744 159.475 160.182 159.899 ;
     RECT  129.384 159.359 155.898 160.043 ;
     RECT  156.744 159.899 159.714 160.043 ;
     RECT  129.816 160.043 155.898 160.169 ;
     RECT  130.104 160.169 155.898 160.171 ;
     RECT  156.744 160.043 159.297 160.171 ;
     RECT  127.908 160.141 127.926 160.285 ;
     RECT  127.908 160.285 128.502 160.349 ;
     RECT  122.832 160.321 122.85 160.411 ;
     RECT  130.104 160.171 159.297 160.475 ;
     RECT  122.832 160.411 123.282 160.519 ;
     RECT  124.164 160.321 124.182 160.519 ;
     RECT  122.832 160.519 124.182 160.681 ;
     RECT  122.832 160.681 124.434 160.861 ;
     RECT  122.832 160.861 125.154 160.979 ;
     RECT  130.932 160.475 159.297 161.285 ;
     RECT  122.832 160.979 124.794 161.321 ;
     RECT  131.004 161.285 159.297 161.323 ;
     RECT  122.832 161.321 123.786 161.519 ;
     RECT  131.004 161.323 159.642 161.519 ;
     RECT  122.832 161.519 123.714 161.635 ;
     RECT  122.58 161.635 123.714 161.671 ;
     RECT  2.415 2.413 2.697 161.797 ;
     RECT  2.34 161.797 2.862 161.851 ;
     RECT  3.78 161.761 3.798 161.851 ;
     RECT  0.18 161.707 0.198 161.885 ;
     RECT  107.784 161.515 107.802 161.905 ;
     RECT  120.348 161.833 120.366 161.941 ;
     RECT  2.34 161.851 3.798 161.947 ;
     RECT  120.276 161.941 120.366 162.059 ;
     RECT  2.304 161.947 3.798 162.095 ;
     RECT  0.108 161.899 0.126 162.125 ;
     RECT  126.615 2.413 126.897 162.139 ;
     RECT  107.784 161.905 107.91 162.175 ;
     RECT  121.215 2.413 121.497 162.175 ;
     RECT  122.508 161.671 123.714 162.175 ;
     RECT  3.78 162.095 3.798 162.211 ;
     RECT  121.212 162.175 121.497 162.211 ;
     RECT  122.436 162.175 123.714 162.211 ;
     RECT  120.132 162.175 120.15 162.221 ;
     RECT  2.415 162.095 2.862 162.239 ;
     RECT  130.104 160.475 130.122 162.301 ;
     RECT  107.712 162.175 107.91 162.329 ;
     RECT  121.068 162.211 123.714 162.337 ;
     RECT  124.776 161.321 124.794 162.337 ;
     RECT  131.004 161.519 159.297 162.337 ;
     RECT  121.068 162.337 124.794 162.365 ;
     RECT  121.215 162.365 124.794 162.373 ;
     RECT  126.615 162.139 127.134 162.607 ;
     RECT  127.908 160.349 127.926 162.607 ;
     RECT  121.215 162.373 124.902 162.635 ;
     RECT  129.42 162.301 130.122 162.643 ;
     RECT  126.615 162.607 127.926 162.667 ;
     RECT  105.015 2.413 105.297 162.715 ;
     RECT  3.78 162.211 3.834 162.743 ;
     RECT  126.468 162.667 127.926 162.751 ;
     RECT  129.024 162.643 130.122 162.751 ;
     RECT  122.22 162.635 124.902 162.913 ;
     RECT  122.22 162.913 125.406 162.941 ;
     RECT  126.396 162.751 130.122 163.021 ;
     RECT  130.932 162.337 159.297 163.021 ;
     RECT  126.396 163.021 159.297 163.183 ;
     RECT  125.388 162.941 125.406 163.219 ;
     RECT  126.252 163.183 159.297 163.219 ;
     RECT  125.388 163.219 159.297 163.255 ;
     RECT  122.22 162.941 124.254 163.319 ;
     RECT  125.388 163.255 159.426 163.409 ;
     RECT  121.215 162.635 121.497 163.417 ;
     RECT  122.22 163.319 124.146 163.417 ;
     RECT  121.215 163.417 124.146 163.531 ;
     RECT  3.816 162.743 3.834 163.679 ;
     RECT  121.104 163.531 124.146 163.715 ;
     RECT  101.808 163.993 101.826 164.029 ;
     RECT  101.34 164.029 101.826 164.065 ;
     RECT  105.015 162.715 105.714 164.065 ;
     RECT  121.215 163.715 124.146 164.065 ;
     RECT  99.615 2.413 99.897 164.101 ;
     RECT  104.904 164.065 105.714 164.101 ;
     RECT  103.248 164.101 103.986 164.107 ;
     RECT  104.904 164.101 106.11 164.107 ;
     RECT  99.144 164.101 99.897 164.227 ;
     RECT  99.144 164.227 100.17 164.251 ;
     RECT  100.908 164.065 101.826 164.251 ;
     RECT  99.144 164.251 101.826 164.263 ;
     RECT  103.248 164.107 106.11 164.263 ;
     RECT  121.215 164.065 124.362 164.299 ;
     RECT  121.215 164.299 124.542 164.335 ;
     RECT  125.388 163.409 159.297 164.335 ;
     RECT  99.144 164.263 106.11 164.371 ;
     RECT  98.676 164.371 106.11 164.461 ;
     RECT  121.215 164.335 159.297 164.497 ;
     RECT  121.215 164.497 159.462 164.641 ;
     RECT  98.64 164.461 106.11 164.803 ;
     RECT  121.215 164.641 159.93 164.831 ;
     RECT  122.364 164.831 159.93 164.867 ;
     RECT  98.64 164.803 106.29 164.875 ;
     RECT  98.388 164.875 106.326 165.299 ;
     RECT  122.4 164.867 159.93 165.415 ;
     RECT  122.4 165.415 160.29 165.569 ;
     RECT  98.46 165.299 106.326 165.629 ;
     RECT  122.436 165.569 160.29 165.649 ;
     RECT  122.436 165.649 160.902 165.869 ;
     RECT  160.884 165.869 160.902 165.875 ;
     RECT  98.604 165.629 106.326 165.919 ;
     RECT  98.604 165.919 106.434 165.991 ;
     RECT  108 162.409 108.018 166.379 ;
     RECT  242.244 166.225 242.262 166.379 ;
     RECT  245.415 2.413 245.697 166.423 ;
     RECT  98.604 165.991 106.578 166.459 ;
     RECT  122.436 165.869 160.11 166.523 ;
     RECT  122.472 166.523 160.11 166.649 ;
     RECT  245.415 166.423 245.898 166.801 ;
     RECT  158.688 166.649 160.11 166.829 ;
     RECT  115.815 2.413 116.097 166.891 ;
     RECT  244.008 166.801 244.026 166.891 ;
     RECT  244.008 166.891 244.494 166.919 ;
     RECT  115.056 166.891 115.074 166.925 ;
     RECT  122.472 166.649 157.95 167.021 ;
     RECT  122.472 167.021 157.878 167.189 ;
     RECT  98.388 166.459 106.578 167.225 ;
     RECT  121.215 164.831 121.497 167.269 ;
     RECT  122.472 167.189 156.402 167.269 ;
     RECT  115.815 166.891 116.37 167.405 ;
     RECT  121.215 167.269 156.402 167.459 ;
     RECT  98.604 167.225 106.578 167.467 ;
     RECT  158.688 166.829 160.038 167.539 ;
     RECT  244.476 166.919 244.494 167.539 ;
     RECT  158.616 167.539 160.038 167.563 ;
     RECT  244.476 167.539 244.53 167.701 ;
     RECT  245.415 166.801 246.15 167.701 ;
     RECT  158.616 167.563 160.758 167.729 ;
     RECT  107.892 166.495 107.91 167.845 ;
     RECT  157.176 167.189 157.878 167.845 ;
     RECT  158.616 167.729 160.722 167.845 ;
     RECT  161.748 165.847 161.766 167.881 ;
     RECT  242.244 167.809 242.262 167.909 ;
     RECT  122.688 167.459 156.402 167.971 ;
     RECT  157.176 167.845 160.722 167.971 ;
     RECT  161.748 167.881 162.054 167.999 ;
     RECT  98.604 167.467 106.722 168.007 ;
     RECT  107.892 167.845 108.126 168.007 ;
     RECT  122.688 167.971 160.722 168.269 ;
     RECT  98.604 168.007 108.126 168.413 ;
     RECT  98.604 168.413 107.91 168.421 ;
     RECT  244.476 167.701 246.15 168.421 ;
     RECT  247.068 165.847 247.086 168.421 ;
     RECT  161.748 167.999 161.982 168.449 ;
     RECT  122.976 168.269 160.722 168.539 ;
     RECT  122.976 168.539 160.47 168.653 ;
     RECT  121.215 167.459 121.914 168.763 ;
     RECT  122.976 168.653 160.362 168.809 ;
     RECT  2.415 162.239 2.697 169.051 ;
     RECT  121.215 168.763 122.238 169.051 ;
     RECT  122.976 168.809 159.498 169.051 ;
     RECT  98.28 168.421 107.91 169.195 ;
     RECT  97.56 169.195 107.91 169.229 ;
     RECT  97.956 169.229 107.91 169.565 ;
     RECT  160.56 169.465 160.578 169.619 ;
     RECT  109.296 169.627 109.314 169.699 ;
     RECT  160.236 169.675 160.254 169.727 ;
     RECT  121.215 169.051 159.498 169.735 ;
     RECT  121.215 169.735 160.146 169.763 ;
     RECT  122.436 169.763 160.146 169.799 ;
     RECT  122.436 169.799 159.39 169.805 ;
     RECT  98.28 169.565 107.91 169.889 ;
     RECT  160.128 169.799 160.146 169.889 ;
     RECT  2.415 169.051 3.006 169.969 ;
     RECT  109.116 169.699 109.314 170.069 ;
     RECT  113.292 169.465 113.31 170.131 ;
     RECT  202.215 2.413 202.497 170.131 ;
     RECT  161.748 168.449 161.766 170.195 ;
     RECT  113.04 170.131 113.31 170.299 ;
     RECT  96.876 170.041 96.894 170.311 ;
     RECT  111.492 170.275 111.51 170.311 ;
     RECT  114.336 169.963 114.354 170.311 ;
     RECT  242.244 170.041 242.262 170.339 ;
     RECT  112.968 170.299 113.31 170.429 ;
     RECT  118.584 170.311 118.602 170.429 ;
     RECT  114.336 170.311 114.498 170.465 ;
     RECT  111.492 170.311 111.654 170.473 ;
     RECT  110.415 2.413 110.697 170.509 ;
     RECT  111.492 170.473 112.05 170.509 ;
     RECT  110.415 170.509 112.194 170.573 ;
     RECT  121.215 169.763 121.554 170.581 ;
     RECT  112.104 170.573 112.194 170.699 ;
     RECT  2.415 169.969 3.33 170.707 ;
     RECT  98.352 169.889 107.91 170.743 ;
     RECT  110.415 170.573 111.33 170.771 ;
     RECT  113.292 170.429 113.31 170.771 ;
     RECT  121.215 170.581 121.698 170.815 ;
     RECT  122.436 169.805 159.297 170.815 ;
     RECT  112.104 170.699 112.122 170.843 ;
     RECT  114.48 170.465 114.498 170.843 ;
     RECT  121.215 170.815 159.297 170.851 ;
     RECT  244.116 168.421 247.086 170.977 ;
     RECT  121.215 170.851 159.822 171.013 ;
     RECT  109.116 170.069 109.17 171.019 ;
     RECT  121.215 171.013 159.966 171.019 ;
     RECT  98.244 170.743 107.91 171.121 ;
     RECT  121.215 171.019 160.218 171.121 ;
     RECT  110.415 170.771 111.258 171.149 ;
     RECT  97.812 171.121 107.91 171.211 ;
     RECT  109.116 171.019 109.422 171.211 ;
     RECT  97.812 171.211 109.422 171.275 ;
     RECT  121.215 171.121 160.29 171.419 ;
     RECT  97.812 171.275 109.278 171.509 ;
     RECT  121.215 171.419 160.254 171.545 ;
     RECT  121.215 171.545 160.218 171.581 ;
     RECT  98.316 171.509 109.278 171.617 ;
     RECT  96.3 170.311 96.894 171.661 ;
     RECT  98.388 171.617 109.278 171.689 ;
     RECT  98.388 171.689 108.738 172.193 ;
     RECT  121.215 171.581 159.39 172.399 ;
     RECT  98.388 172.193 108.414 172.561 ;
     RECT  121.215 172.399 159.93 172.669 ;
     RECT  244.116 170.977 247.122 172.831 ;
     RECT  242.748 172.705 242.766 172.859 ;
     RECT  98.352 172.561 108.414 172.891 ;
     RECT  98.244 172.891 108.414 172.931 ;
     RECT  98.316 172.931 108.414 173.011 ;
     RECT  98.316 173.011 108.882 173.129 ;
     RECT  121.215 172.669 160.182 173.165 ;
     RECT  164.415 2.413 164.697 173.275 ;
     RECT  175.215 2.413 175.497 173.275 ;
     RECT  186.015 2.413 186.297 173.275 ;
     RECT  196.815 2.413 197.097 173.275 ;
     RECT  207.615 2.413 207.897 173.275 ;
     RECT  218.415 2.413 218.697 173.275 ;
     RECT  229.215 2.413 229.497 173.275 ;
     RECT  164.304 173.275 164.697 173.309 ;
     RECT  175.104 173.275 175.497 173.309 ;
     RECT  185.904 173.275 186.297 173.309 ;
     RECT  196.704 173.275 197.097 173.309 ;
     RECT  207.504 173.275 207.897 173.309 ;
     RECT  218.304 173.275 218.697 173.309 ;
     RECT  229.104 173.275 229.497 173.309 ;
     RECT  121.215 173.165 160.074 173.419 ;
     RECT  161.1 173.245 161.118 173.435 ;
     RECT  238.284 173.275 238.302 173.453 ;
     RECT  98.316 173.129 108.774 173.543 ;
     RECT  107.496 173.543 108.774 173.669 ;
     RECT  243.144 173.419 243.162 173.669 ;
     RECT  244.116 172.831 247.446 173.785 ;
     RECT  242.244 173.713 242.262 173.849 ;
     RECT  161.244 173.713 161.262 173.939 ;
     RECT  96.3 171.661 97.038 173.947 ;
     RECT  202.215 170.131 202.734 174.011 ;
     RECT  120.492 173.419 160.074 174.055 ;
     RECT  96.3 173.947 97.362 174.091 ;
     RECT  120.492 174.055 160.326 174.091 ;
     RECT  243.36 174.019 243.378 174.091 ;
     RECT  244.116 173.785 247.482 174.091 ;
     RECT  96.3 174.091 97.506 174.181 ;
     RECT  98.316 173.543 106.614 174.181 ;
     RECT  120.492 174.091 160.47 174.209 ;
     RECT  242.316 174.055 242.334 174.209 ;
     RECT  94.215 2.413 94.497 174.217 ;
     RECT  96.3 174.181 106.614 174.221 ;
     RECT  243.36 174.091 247.482 174.221 ;
     RECT  243.36 174.221 247.41 174.245 ;
     RECT  160.452 174.209 160.47 174.281 ;
     RECT  202.215 174.011 202.59 174.281 ;
     RECT  161.28 174.055 161.298 174.317 ;
     RECT  243.396 174.245 247.41 174.317 ;
     RECT  243.792 174.317 247.374 174.353 ;
     RECT  94.215 174.217 94.662 174.389 ;
     RECT  107.496 173.669 108.378 174.461 ;
     RECT  120.564 174.209 159.498 174.479 ;
     RECT  243.828 174.353 243.846 174.515 ;
     RECT  98.316 174.221 106.614 174.551 ;
     RECT  107.748 174.461 108.378 174.559 ;
     RECT  98.352 174.551 106.614 174.595 ;
     RECT  107.748 174.559 108.558 174.595 ;
     RECT  107.748 174.595 108.882 174.631 ;
     RECT  98.352 174.595 106.83 174.749 ;
     RECT  202.215 174.281 202.497 174.757 ;
     RECT  107.748 174.631 109.278 174.785 ;
     RECT  201.78 174.757 202.497 175.055 ;
     RECT  248.292 174.379 248.31 175.127 ;
     RECT  244.764 174.353 247.374 175.135 ;
     RECT  107.856 174.785 109.278 175.171 ;
     RECT  120.564 174.479 159.39 175.171 ;
     RECT  160.92 175.171 160.938 175.289 ;
     RECT  242.316 175.051 242.334 175.289 ;
     RECT  244.656 175.135 247.41 175.289 ;
     RECT  120.312 175.171 159.39 175.291 ;
     RECT  202.215 175.055 202.497 175.297 ;
     RECT  166.428 175.261 166.446 175.325 ;
     RECT  96.3 174.221 97.506 175.333 ;
     RECT  98.352 174.749 106.578 175.333 ;
     RECT  243.864 175.261 243.882 175.361 ;
     RECT  164.415 173.309 164.697 175.435 ;
     RECT  175.215 173.309 175.497 175.435 ;
     RECT  186.015 173.309 186.297 175.435 ;
     RECT  196.815 173.309 197.097 175.435 ;
     RECT  207.615 173.309 207.897 175.435 ;
     RECT  218.415 173.309 218.697 175.435 ;
     RECT  229.215 173.309 229.497 175.435 ;
     RECT  240.015 2.413 240.297 175.435 ;
     RECT  120.312 175.291 160.11 175.469 ;
     RECT  164.304 175.435 164.697 175.469 ;
     RECT  175.104 175.435 175.497 175.469 ;
     RECT  185.904 175.435 186.297 175.469 ;
     RECT  196.704 175.435 197.097 175.469 ;
     RECT  207.504 175.435 207.897 175.469 ;
     RECT  218.304 175.435 218.697 175.469 ;
     RECT  229.104 175.435 229.497 175.469 ;
     RECT  239.904 175.435 240.297 175.469 ;
     RECT  107.856 175.171 109.314 175.531 ;
     RECT  96.3 175.333 106.578 175.559 ;
     RECT  120.312 175.469 159.297 175.565 ;
     RECT  96.3 175.559 97.47 175.595 ;
     RECT  107.856 175.531 109.386 175.675 ;
     RECT  110.415 171.149 111.006 175.675 ;
     RECT  98.208 175.559 106.578 175.711 ;
     RECT  243.936 175.441 243.954 175.739 ;
     RECT  244.764 175.289 247.41 175.757 ;
     RECT  107.856 175.675 111.006 175.829 ;
     RECT  161.64 175.711 161.658 175.829 ;
     RECT  98.208 175.711 106.974 175.837 ;
     RECT  107.856 175.829 109.386 175.837 ;
     RECT  244.764 175.757 247.374 175.853 ;
     RECT  160.668 175.579 160.866 175.865 ;
     RECT  244.764 175.853 246.15 175.949 ;
     RECT  110.268 175.829 111.006 176.009 ;
     RECT  120.564 175.565 159.297 176.009 ;
     RECT  121.032 176.009 159.297 176.099 ;
     RECT  160.848 175.865 160.866 176.099 ;
     RECT  247.068 175.853 247.374 176.141 ;
     RECT  244.764 175.949 246.006 176.189 ;
     RECT  244.8 176.189 246.006 176.237 ;
     RECT  98.208 175.837 109.386 176.243 ;
     RECT  121.068 176.099 159.297 176.251 ;
     RECT  248.22 176.155 248.238 176.333 ;
     RECT  202.215 175.297 202.914 176.369 ;
     RECT  247.356 176.141 247.374 176.441 ;
     RECT  98.208 176.243 101.142 176.521 ;
     RECT  244.8 176.237 245.898 176.639 ;
     RECT  121.068 176.251 159.714 176.683 ;
     RECT  121.068 176.683 160.002 176.819 ;
     RECT  160.92 176.377 160.938 176.909 ;
     RECT  248.292 176.491 248.31 176.909 ;
     RECT  121.104 176.819 160.002 176.945 ;
     RECT  4.248 175.261 4.266 176.989 ;
     RECT  94.215 174.389 94.497 176.989 ;
     RECT  96.3 175.595 97.038 177.025 ;
     RECT  98.064 176.521 101.142 177.025 ;
     RECT  101.916 176.243 109.386 177.025 ;
     RECT  244.8 176.639 245.697 177.025 ;
     RECT  94.215 176.989 94.662 177.089 ;
     RECT  160.128 177.061 160.146 177.179 ;
     RECT  96.3 177.025 109.386 177.259 ;
     RECT  110.415 176.009 111.006 177.259 ;
     RECT  96.3 177.259 111.006 177.565 ;
     RECT  121.104 176.945 159.297 177.565 ;
     RECT  2.415 170.707 3.51 177.799 ;
     RECT  95.616 177.565 111.006 177.821 ;
     RECT  96.3 177.821 111.006 178.069 ;
     RECT  96.3 178.069 111.654 178.105 ;
     RECT  120.816 177.565 159.297 178.363 ;
     RECT  120.672 178.363 159.297 178.403 ;
     RECT  119.7 178.603 119.718 178.637 ;
     RECT  244.62 177.025 245.697 178.681 ;
     RECT  120.816 178.403 159.297 178.835 ;
     RECT  120.816 178.835 122.418 178.877 ;
     RECT  121.215 178.877 122.382 178.907 ;
     RECT  121.215 178.907 121.59 178.973 ;
     RECT  244.548 178.681 245.697 178.979 ;
     RECT  122.364 178.907 122.382 179.069 ;
     RECT  244.8 178.979 245.697 179.375 ;
     RECT  2.376 177.799 3.51 179.455 ;
     RECT  245.415 179.375 245.697 179.491 ;
     RECT  2.304 179.455 3.51 179.501 ;
     RECT  96.3 178.105 111.762 179.609 ;
     RECT  96.3 179.609 108.81 179.753 ;
     RECT  247.356 179.659 247.374 179.755 ;
     RECT  247.32 179.755 247.374 179.851 ;
     RECT  2.376 179.501 3.51 179.923 ;
     RECT  4.248 176.989 4.302 179.923 ;
     RECT  244.656 179.851 244.674 179.933 ;
     RECT  109.584 179.609 111.762 180.023 ;
     RECT  123.228 178.835 159.297 180.031 ;
     RECT  247.284 179.851 247.374 180.043 ;
     RECT  245.415 179.491 246.042 180.121 ;
     RECT  244.98 180.121 246.042 180.139 ;
     RECT  246.78 180.043 247.374 180.139 ;
     RECT  121.215 178.973 121.497 180.157 ;
     RECT  120.852 180.157 121.497 180.257 ;
     RECT  96.3 179.753 108.774 180.293 ;
     RECT  244.98 180.139 247.374 180.365 ;
     RECT  115.815 167.405 116.097 180.523 ;
     RECT  123.192 180.031 159.297 180.535 ;
     RECT  244.98 180.365 245.697 180.557 ;
     RECT  107.28 180.293 108.774 180.571 ;
     RECT  96.3 180.293 106.542 180.599 ;
     RECT  114.876 180.139 114.894 180.689 ;
     RECT  115.668 180.523 116.442 180.701 ;
     RECT  118.584 180.523 118.602 180.701 ;
     RECT  109.656 180.023 111.762 180.769 ;
     RECT  112.536 178.231 112.554 180.769 ;
     RECT  2.376 179.923 4.302 180.805 ;
     RECT  107.28 180.571 108.882 180.841 ;
     RECT  109.656 180.769 112.554 180.841 ;
     RECT  2.304 180.805 4.302 180.845 ;
     RECT  2.376 180.845 4.302 180.869 ;
     RECT  246.744 180.365 247.374 180.959 ;
     RECT  122.616 180.535 159.297 181.075 ;
     RECT  114.156 181.075 114.174 181.229 ;
     RECT  118.62 181.111 118.638 181.229 ;
     RECT  96.3 180.599 106.506 181.345 ;
     RECT  107.28 180.841 112.554 181.345 ;
     RECT  244.476 181.111 244.494 181.381 ;
     RECT  96.3 181.345 112.554 181.499 ;
     RECT  247.356 180.959 247.374 181.499 ;
     RECT  244.476 181.381 244.674 181.565 ;
     RECT  245.415 180.557 245.697 181.615 ;
     RECT  2.415 180.869 4.302 181.769 ;
     RECT  244.656 181.565 244.674 181.769 ;
     RECT  245.415 181.615 245.862 181.769 ;
     RECT  122.436 181.075 159.297 181.777 ;
     RECT  2.415 181.769 3.51 181.885 ;
     RECT  2.304 181.885 3.51 182.039 ;
     RECT  122.364 181.777 159.297 182.345 ;
     RECT  96.3 181.499 96.318 182.395 ;
     RECT  97.056 181.499 112.554 182.395 ;
     RECT  122.508 182.345 159.297 182.579 ;
     RECT  123.408 182.579 159.297 182.615 ;
     RECT  123.444 182.615 159.297 182.659 ;
     RECT  122.508 182.579 122.634 182.723 ;
     RECT  123.444 182.659 159.714 182.723 ;
     RECT  123.48 182.723 159.714 182.731 ;
     RECT  4.248 181.769 4.302 182.929 ;
     RECT  95.364 182.731 95.526 182.965 ;
     RECT  96.3 182.395 112.554 182.965 ;
     RECT  94.215 177.089 94.497 182.971 ;
     RECT  95.364 182.965 112.554 182.971 ;
     RECT  94.215 182.971 112.554 183.005 ;
     RECT  95.76 183.005 112.554 183.119 ;
     RECT  2.304 182.039 3.402 183.127 ;
     RECT  4.248 182.929 4.41 183.127 ;
     RECT  121.215 180.257 121.497 183.271 ;
     RECT  2.304 183.127 4.41 183.299 ;
     RECT  95.904 183.119 111.726 183.299 ;
     RECT  2.304 183.299 3.114 183.389 ;
     RECT  4.032 183.299 4.41 183.389 ;
     RECT  90.648 183.271 90.666 183.389 ;
     RECT  120.852 183.271 121.497 183.389 ;
     RECT  95.904 183.299 111.69 183.461 ;
     RECT  4.032 183.389 4.194 183.497 ;
     RECT  2.304 183.389 2.934 183.569 ;
     RECT  4.176 183.497 4.194 183.659 ;
     RECT  94.215 183.005 94.986 183.811 ;
     RECT  122.616 182.723 122.634 183.811 ;
     RECT  123.48 182.731 160.29 183.811 ;
     RECT  94.215 183.811 95.022 183.929 ;
     RECT  95.904 183.461 96.318 184.081 ;
     RECT  97.056 183.461 111.69 184.081 ;
     RECT  95.76 184.081 96.318 184.109 ;
     RECT  121.215 183.389 121.497 184.171 ;
     RECT  122.616 183.811 160.29 184.171 ;
     RECT  0.54 183.469 0.558 184.205 ;
     RECT  97.056 184.081 111.726 184.207 ;
     RECT  112.536 183.119 112.554 184.207 ;
     RECT  95.76 184.109 95.778 184.235 ;
     RECT  2.304 183.569 2.898 184.351 ;
     RECT  3.708 184.279 4.014 184.351 ;
     RECT  118.584 184.207 118.602 184.351 ;
     RECT  2.304 184.351 4.014 184.469 ;
     RECT  118.584 184.351 118.674 184.577 ;
     RECT  94.215 183.929 94.914 184.613 ;
     RECT  2.304 184.469 3.762 184.843 ;
     RECT  0.144 184.747 0.162 184.925 ;
     RECT  118.584 184.577 118.602 185.009 ;
     RECT  6.804 184.981 6.822 185.117 ;
     RECT  1.98 184.843 3.762 185.153 ;
     RECT  121.215 184.171 160.29 185.153 ;
     RECT  122.22 185.153 160.29 185.161 ;
     RECT  122.22 185.161 160.362 185.189 ;
     RECT  0.324 185.131 0.342 185.261 ;
     RECT  95.436 185.017 95.454 185.279 ;
     RECT  94.215 184.613 94.698 185.395 ;
     RECT  97.056 184.207 112.554 185.431 ;
     RECT  94.215 185.395 95.31 185.453 ;
     RECT  94.215 185.453 95.238 185.621 ;
     RECT  122.328 185.189 160.362 185.701 ;
     RECT  1.98 185.153 3.438 185.729 ;
     RECT  3.42 185.729 3.438 185.741 ;
     RECT  96.264 185.521 96.282 185.791 ;
     RECT  97.056 185.431 112.626 185.827 ;
     RECT  96.12 185.791 96.282 185.837 ;
     RECT  94.215 185.621 94.662 186.161 ;
     RECT  97.056 185.827 112.806 186.241 ;
     RECT  97.056 186.241 112.878 186.331 ;
     RECT  4.572 186.061 4.59 186.539 ;
     RECT  96.624 186.331 112.878 186.637 ;
     RECT  95.4 186.637 95.418 186.701 ;
     RECT  96.48 186.637 112.878 186.701 ;
     RECT  90.648 186.601 90.666 186.773 ;
     RECT  118.584 186.439 118.602 186.809 ;
     RECT  122.328 185.701 160.65 186.859 ;
     RECT  97.056 186.701 112.878 186.899 ;
     RECT  97.056 186.899 112.338 187.007 ;
     RECT  122.292 186.859 160.65 187.015 ;
     RECT  97.344 187.007 112.338 187.079 ;
     RECT  1.98 185.729 2.697 187.321 ;
     RECT  121.215 185.153 121.497 187.753 ;
     RECT  122.22 187.015 160.65 187.753 ;
     RECT  1.98 187.321 2.79 187.817 ;
     RECT  97.344 187.079 101.538 187.825 ;
     RECT  102.384 187.079 112.338 187.825 ;
     RECT  2.415 187.817 2.79 187.861 ;
     RECT  96.264 187.717 96.282 187.951 ;
     RECT  2.415 187.861 3.006 187.979 ;
     RECT  96.12 187.951 96.282 187.979 ;
     RECT  97.056 187.825 112.338 187.979 ;
     RECT  96.12 187.979 96.138 187.997 ;
     RECT  2.415 187.979 2.79 188.015 ;
     RECT  97.164 187.979 112.338 188.015 ;
     RECT  97.488 188.015 112.338 188.045 ;
     RECT  121.215 187.753 160.65 188.285 ;
     RECT  98.532 188.045 112.338 188.357 ;
     RECT  97.488 188.045 97.686 188.393 ;
     RECT  99.18 188.357 112.338 188.401 ;
     RECT  118.584 188.131 118.602 188.519 ;
     RECT  99.18 188.401 112.446 188.591 ;
     RECT  122.472 188.285 160.65 188.663 ;
     RECT  122.544 188.663 160.65 188.669 ;
     RECT  123.192 188.669 160.65 188.941 ;
     RECT  123.192 188.941 160.794 189.095 ;
     RECT  126.072 189.095 160.794 189.211 ;
     RECT  99.18 188.591 112.014 189.337 ;
     RECT  123.192 189.095 125.226 189.409 ;
     RECT  99.18 189.337 112.194 189.445 ;
     RECT  123.12 189.409 125.226 189.509 ;
     RECT  123.3 189.509 125.226 189.671 ;
     RECT  99.18 189.445 112.554 189.835 ;
     RECT  99.144 189.835 112.554 189.841 ;
     RECT  123.768 189.671 125.226 189.841 ;
     RECT  126.072 189.211 160.902 189.841 ;
     RECT  99.144 189.841 112.698 189.905 ;
     RECT  99.18 189.905 112.698 190.175 ;
     RECT  99.18 190.175 111.978 190.319 ;
     RECT  123.768 189.841 160.902 190.489 ;
     RECT  123.768 190.489 161.01 190.561 ;
     RECT  123.624 190.561 161.046 190.759 ;
     RECT  99.18 190.319 111.438 190.831 ;
     RECT  123.624 190.759 161.118 190.957 ;
     RECT  99.108 190.831 111.438 191.065 ;
     RECT  123.48 190.957 161.118 191.065 ;
     RECT  98.964 191.065 111.978 191.227 ;
     RECT  98.964 191.227 112.194 191.261 ;
     RECT  97.668 188.393 97.686 191.327 ;
     RECT  99.432 191.261 112.194 191.327 ;
     RECT  123.48 191.065 161.154 191.501 ;
     RECT  99.615 191.327 112.194 191.759 ;
     RECT  99.615 191.759 111.978 191.795 ;
     RECT  99.615 191.795 111.654 192.137 ;
     RECT  99.615 192.137 111.618 192.299 ;
     RECT  124.056 191.501 161.154 192.541 ;
     RECT  100.764 192.299 111.618 192.569 ;
     RECT  123.732 192.541 161.154 192.571 ;
     RECT  123.156 192.571 161.154 192.605 ;
     RECT  100.764 192.569 111.546 192.677 ;
     RECT  100.764 192.677 105.426 193.109 ;
     RECT  100.8 193.109 105.426 193.459 ;
     RECT  106.272 192.677 111.546 193.459 ;
     RECT  100.8 193.459 111.546 193.531 ;
     RECT  100.8 193.531 111.618 193.757 ;
     RECT  106.092 193.757 111.618 194.063 ;
     RECT  123.66 192.605 161.154 194.071 ;
     RECT  123.156 194.071 161.154 194.155 ;
     RECT  123.012 194.155 161.154 194.189 ;
     RECT  106.092 194.063 111.474 194.237 ;
     RECT  123.66 194.189 161.154 194.381 ;
     RECT  100.8 193.757 105.354 194.503 ;
     RECT  106.092 194.237 111.438 194.503 ;
     RECT  100.8 194.503 111.438 194.765 ;
     RECT  121.215 188.285 121.497 194.971 ;
     RECT  101.16 194.765 111.438 195.143 ;
     RECT  123.768 194.381 161.154 195.151 ;
     RECT  101.16 195.143 111.258 195.305 ;
     RECT  121.068 194.971 121.497 195.449 ;
     RECT  123.516 195.151 161.154 195.643 ;
     RECT  101.16 195.305 111.114 195.655 ;
     RECT  122.94 195.643 161.154 195.683 ;
     RECT  99.615 192.299 99.897 196.051 ;
     RECT  100.692 195.655 111.114 196.051 ;
     RECT  99.615 196.051 111.114 196.079 ;
     RECT  123.624 195.683 161.154 196.397 ;
     RECT  99.615 196.079 100.314 196.619 ;
     RECT  123.624 196.397 154.098 196.925 ;
     RECT  124.236 196.925 154.098 197.131 ;
     RECT  154.872 196.397 161.154 197.131 ;
     RECT  101.16 196.079 111.114 197.203 ;
     RECT  101.16 197.203 111.186 197.213 ;
     RECT  101.16 197.213 101.178 197.267 ;
     RECT  124.236 197.131 161.154 197.339 ;
     RECT  101.916 197.213 111.186 198.085 ;
     RECT  101.916 198.085 111.222 198.235 ;
     RECT  101.556 198.235 111.222 198.239 ;
     RECT  124.272 197.339 161.154 198.239 ;
     RECT  101.556 198.239 101.574 198.275 ;
     RECT  102.492 198.239 111.222 198.347 ;
     RECT  102.492 198.347 108.198 198.365 ;
     RECT  109.836 198.347 111.222 198.419 ;
     RECT  102.492 198.365 102.582 198.509 ;
     RECT  103.392 198.365 108.198 198.509 ;
     RECT  108.972 198.347 108.99 198.509 ;
     RECT  110.415 198.419 111.222 198.509 ;
     RECT  102.492 198.509 102.51 198.545 ;
     RECT  103.608 198.509 105.297 198.545 ;
     RECT  110.415 198.509 111.186 198.581 ;
     RECT  106.02 198.509 106.974 198.653 ;
     RECT  107.82 198.509 108.054 198.653 ;
     RECT  106.02 198.653 106.29 198.689 ;
     RECT  103.716 198.545 105.297 198.779 ;
     RECT  106.092 198.689 106.29 198.779 ;
     RECT  107.82 198.653 107.91 198.779 ;
     RECT  103.716 198.779 103.734 198.815 ;
     RECT  104.58 198.779 105.297 198.815 ;
     RECT  106.092 198.779 106.11 198.815 ;
     RECT  107.82 198.779 107.838 198.815 ;
     RECT  123.912 198.355 123.93 198.923 ;
     RECT  124.668 198.239 161.154 198.923 ;
     RECT  124.956 198.923 161.154 199.867 ;
     RECT  124.812 199.867 161.154 200.011 ;
     RECT  124.272 200.011 161.154 200.209 ;
     RECT  124.056 200.209 161.154 201.209 ;
     RECT  129.42 201.209 161.154 201.551 ;
     RECT  124.236 201.209 128.214 201.991 ;
     RECT  129.456 201.551 161.154 202.019 ;
     RECT  124.236 201.991 128.502 202.171 ;
     RECT  123.984 202.171 128.502 202.349 ;
     RECT  129.456 202.019 161.01 202.363 ;
     RECT  124.128 202.349 128.502 202.675 ;
     RECT  129.42 202.363 161.01 202.675 ;
     RECT  124.128 202.675 161.01 202.829 ;
     RECT  124.128 202.829 160.506 202.901 ;
     RECT  124.128 202.901 160.434 203.251 ;
     RECT  123.696 203.251 160.434 203.323 ;
     RECT  123.552 203.323 160.434 203.369 ;
     RECT  124.272 203.369 160.434 203.909 ;
     RECT  124.272 203.909 160.254 204.017 ;
     RECT  124.272 204.017 128.934 204.179 ;
     RECT  124.272 204.179 124.614 204.283 ;
     RECT  123.804 204.283 124.614 204.287 ;
     RECT  123.804 204.287 123.822 204.323 ;
     RECT  124.596 204.287 124.614 204.449 ;
     RECT  125.352 204.179 128.934 204.605 ;
     RECT  126.072 204.605 128.934 204.835 ;
     RECT  129.672 204.017 160.254 204.835 ;
     RECT  126.072 204.835 160.254 205.529 ;
     RECT  126.072 205.529 160.002 205.645 ;
     RECT  126 205.645 160.002 206.077 ;
     RECT  125.964 206.077 160.002 206.617 ;
     RECT  125.856 206.617 160.002 206.669 ;
     RECT  126.072 206.669 160.002 206.725 ;
     RECT  126.072 206.725 160.038 206.761 ;
     RECT  126.072 206.761 160.254 206.879 ;
     RECT  126.072 206.879 160.038 206.915 ;
     RECT  126.072 206.915 160.002 207.805 ;
     RECT  126.072 207.805 160.182 207.959 ;
     RECT  126.072 207.959 160.146 208.603 ;
     RECT  125.892 208.603 160.146 209.165 ;
     RECT  151.956 209.165 160.146 209.731 ;
     RECT  125.892 209.165 151.182 210.001 ;
     RECT  151.956 209.731 160.362 210.001 ;
     RECT  125.892 210.001 160.362 210.271 ;
     RECT  125.892 210.271 160.686 210.389 ;
     RECT  125.892 210.389 128.754 210.425 ;
     RECT  129.528 210.389 160.686 210.425 ;
     RECT  129.636 210.425 160.686 210.731 ;
     RECT  129.636 210.731 160.506 210.965 ;
     RECT  126.072 210.425 128.754 211.195 ;
     RECT  129.636 210.965 160.434 211.195 ;
     RECT  126.072 211.195 160.434 212.045 ;
     RECT  126.072 212.045 154.89 212.351 ;
     RECT  155.736 212.045 160.434 212.431 ;
     RECT  126.072 212.351 154.854 213.133 ;
     RECT  155.736 212.431 160.794 213.133 ;
     RECT  126.072 213.133 160.794 213.701 ;
     RECT  126.072 213.701 160.578 213.899 ;
     RECT  126.072 213.899 160.398 214.583 ;
     RECT  155.556 214.583 160.398 214.709 ;
     RECT  126.072 214.583 154.818 215.123 ;
     RECT  129.708 215.123 154.818 215.309 ;
     RECT  152.964 215.309 154.818 215.329 ;
     RECT  155.556 214.709 160.218 215.329 ;
     RECT  126.072 215.123 128.79 215.905 ;
     RECT  129.708 215.309 151.686 215.905 ;
     RECT  126.072 215.905 151.686 216.139 ;
     RECT  152.964 215.329 160.218 216.211 ;
     RECT  152.64 216.211 160.218 216.599 ;
     RECT  152.676 216.599 160.218 216.671 ;
     RECT  126.072 216.139 151.866 216.707 ;
     RECT  126.072 216.707 151.83 216.941 ;
     RECT  153.252 216.671 160.218 217.139 ;
     RECT  127.656 216.941 151.83 217.181 ;
     RECT  153.252 217.139 159.822 217.409 ;
     RECT  153.252 217.409 159.297 217.525 ;
     RECT  127.692 217.181 151.83 217.651 ;
     RECT  152.784 217.525 159.297 217.651 ;
     RECT  127.692 217.651 159.297 218.759 ;
     RECT  126.072 216.941 126.897 218.779 ;
     RECT  127.836 218.759 159.297 218.903 ;
     RECT  126.072 218.779 127.098 219.065 ;
     RECT  128.052 218.903 159.297 219.101 ;
     RECT  126.072 219.065 126.897 219.209 ;
     RECT  128.124 219.101 159.297 219.335 ;
     RECT  128.484 219.335 159.297 220.495 ;
     RECT  128.412 220.495 159.297 221.729 ;
     RECT  128.448 221.729 159.297 222.269 ;
     RECT  129.204 222.269 159.297 222.575 ;
     RECT  150.624 222.575 159.297 222.953 ;
     RECT  129.24 222.575 149.886 223.079 ;
     RECT  128.448 222.269 128.466 223.223 ;
     RECT  129.276 223.079 149.886 223.421 ;
     RECT  129.6 223.421 149.886 223.501 ;
     RECT  150.624 222.953 151.434 223.501 ;
     RECT  129.6 223.501 151.434 223.735 ;
     RECT  152.208 222.953 159.297 223.735 ;
     RECT  129.6 223.735 159.297 223.889 ;
     RECT  129.6 223.889 158.202 224.339 ;
     RECT  129.6 224.339 158.166 224.465 ;
     RECT  157.644 224.465 158.166 224.501 ;
     RECT  129.6 224.465 156.798 224.671 ;
     RECT  129.348 224.671 156.798 224.815 ;
     RECT  128.808 224.815 156.798 225.149 ;
     RECT  157.644 224.501 157.662 225.509 ;
     RECT  128.88 225.149 156.798 226.049 ;
     RECT  128.88 226.049 156.15 226.411 ;
     RECT  128.556 226.411 156.15 226.463 ;
     RECT  128.88 226.463 156.15 226.589 ;
     RECT  128.88 226.589 155.754 226.625 ;
     RECT  150.732 226.625 155.43 226.895 ;
     RECT  128.88 226.625 149.994 227.399 ;
     RECT  129.672 227.399 149.994 227.407 ;
     RECT  150.732 226.895 155.394 227.407 ;
     RECT  128.808 227.419 128.826 227.471 ;
     RECT  129.672 227.407 155.394 227.669 ;
     RECT  130.32 227.669 155.394 227.939 ;
     RECT  130.32 227.939 154.998 228.011 ;
     RECT  130.68 228.011 154.998 228.479 ;
     RECT  130.68 228.479 154.962 228.749 ;
     RECT  130.68 228.749 154.89 229.289 ;
     RECT  130.68 229.289 154.566 229.361 ;
     RECT  130.68 229.361 154.386 229.595 ;
     RECT  130.68 229.595 154.278 229.829 ;
     RECT  130.68 229.829 154.206 230.099 ;
     RECT  130.68 230.099 153.897 230.243 ;
     RECT  130.68 230.243 152.694 230.251 ;
     RECT  130.608 230.251 152.694 230.279 ;
     RECT  152.676 230.279 152.694 231.179 ;
     RECT  130.608 230.279 151.938 231.457 ;
     RECT  130.464 231.457 151.938 231.965 ;
     RECT  130.608 231.965 151.938 231.989 ;
     RECT  131.4 231.989 151.398 232.259 ;
     RECT  131.4 232.259 151.182 232.403 ;
     RECT  131.4 232.403 151.146 232.529 ;
     RECT  131.4 232.529 151.11 232.541 ;
     RECT  131.868 232.541 151.11 232.799 ;
     RECT  131.868 232.799 151.002 232.907 ;
     RECT  150.624 232.907 151.002 232.943 ;
     RECT  131.868 232.907 149.814 233.177 ;
     RECT  130.608 231.989 130.626 233.491 ;
     RECT  131.868 233.177 146.466 233.491 ;
     RECT  130.608 233.491 146.466 233.645 ;
     RECT  131.652 233.645 146.466 234.031 ;
     RECT  147.312 233.177 149.814 234.031 ;
     RECT  131.652 234.031 149.814 234.419 ;
     RECT  130.608 233.645 130.626 234.571 ;
     RECT  131.652 234.419 134.01 234.571 ;
     RECT  134.748 234.419 148.842 234.689 ;
     RECT  130.608 234.571 134.01 234.761 ;
     RECT  130.608 234.761 131.13 234.845 ;
     RECT  132.015 234.761 134.01 235.579 ;
     RECT  134.748 234.689 148.77 235.579 ;
     RECT  132.015 235.579 148.77 235.607 ;
     RECT  133.128 235.607 148.77 235.921 ;
     RECT  133.128 235.921 148.806 236.039 ;
     RECT  135.684 236.039 148.806 236.191 ;
     RECT  149.652 234.419 149.814 236.191 ;
     RECT  132.015 235.607 132.297 236.623 ;
     RECT  133.128 236.039 134.874 236.623 ;
     RECT  132.015 236.623 134.874 236.659 ;
     RECT  135.684 236.191 149.814 236.731 ;
     RECT  135.684 236.731 149.994 236.849 ;
     RECT  131.94 236.659 134.874 236.857 ;
     RECT  135.684 236.849 149.814 236.857 ;
     RECT  131.796 236.857 149.814 237.149 ;
     RECT  132.015 237.149 149.814 237.191 ;
     RECT  149.796 237.191 149.814 237.227 ;
     RECT  132.015 237.191 148.878 237.425 ;
     RECT  133.308 237.425 134.802 237.725 ;
     RECT  133.308 237.725 134.334 237.965 ;
     RECT  133.308 237.965 133.974 238.037 ;
     RECT  135.612 237.425 148.878 238.219 ;
     RECT  135.072 238.219 148.878 238.315 ;
     RECT  135.072 238.315 149.022 239.125 ;
     RECT  135.072 239.125 149.238 239.279 ;
     RECT  135.072 239.279 149.13 239.549 ;
     RECT  135.072 239.549 148.497 240.125 ;
     RECT  135.54 240.125 148.497 240.431 ;
     RECT  135.54 240.431 146.718 240.467 ;
     RECT  136.188 240.467 146.718 241.169 ;
     RECT  147.492 240.431 148.497 241.177 ;
     RECT  136.188 241.169 146.538 241.325 ;
     RECT  147.348 241.177 148.497 241.475 ;
     RECT  147.816 241.475 148.497 241.547 ;
     RECT  136.188 241.325 146.466 241.861 ;
     RECT  135.684 241.861 146.466 242.131 ;
     RECT  135.504 242.131 146.466 242.249 ;
     RECT  136.152 242.249 146.466 242.285 ;
     RECT  136.296 242.285 146.466 242.401 ;
     RECT  136.296 242.401 146.79 242.519 ;
     RECT  136.296 242.519 146.466 242.555 ;
     RECT  135.36 242.257 135.378 242.813 ;
     RECT  136.332 242.555 146.466 242.933 ;
     RECT  136.332 242.933 146.25 243.715 ;
     RECT  136.332 243.715 146.646 243.751 ;
     RECT  136.332 243.751 147.006 243.965 ;
     RECT  136.692 243.965 147.006 244.409 ;
     RECT  136.692 244.409 138.006 244.445 ;
     RECT  139.644 244.409 147.006 244.561 ;
     RECT  136.692 244.445 137.934 244.787 ;
     RECT  139.644 244.561 147.114 244.795 ;
     RECT  139.644 244.795 147.33 244.831 ;
     RECT  148.215 241.547 148.497 244.831 ;
     RECT  139.644 244.831 148.497 244.949 ;
     RECT  147.816 244.949 148.497 245.021 ;
     RECT  139.644 244.949 146.898 245.363 ;
     RECT  139.644 245.363 146.682 245.767 ;
     RECT  139.32 245.767 146.682 245.795 ;
     RECT  139.32 245.795 146.574 245.911 ;
     RECT  138.924 245.911 146.574 246.065 ;
     RECT  139.716 246.065 146.574 246.101 ;
     RECT  138.744 246.109 138.762 246.173 ;
     RECT  145.62 246.101 146.574 246.299 ;
     RECT  145.62 246.299 146.394 246.335 ;
     RECT  137.415 244.787 137.934 246.451 ;
     RECT  139.968 246.101 144.882 246.797 ;
     RECT  145.62 246.335 145.962 246.839 ;
     RECT  140.328 246.797 144.882 246.907 ;
     RECT  140.328 246.907 145.53 247.019 ;
     RECT  132.015 237.425 132.498 247.351 ;
     RECT  133.308 238.037 133.326 247.351 ;
     RECT  132.015 247.351 133.326 247.379 ;
     RECT  140.328 247.019 144.882 247.415 ;
     RECT  140.328 247.415 143.478 247.487 ;
     RECT  140.328 247.487 141.642 247.621 ;
     RECT  142.452 247.487 143.478 247.649 ;
     RECT  142.776 247.649 143.478 247.685 ;
     RECT  145.656 247.693 145.674 247.765 ;
     RECT  144.216 247.415 144.882 247.801 ;
     RECT  145.656 247.765 145.746 247.801 ;
     RECT  144.216 247.801 145.746 247.919 ;
     RECT  144.216 247.919 144.918 247.997 ;
     RECT  145.656 247.919 145.746 248.071 ;
     RECT  142.815 247.685 143.478 248.161 ;
     RECT  144.216 247.997 144.882 248.161 ;
     RECT  140.22 247.621 141.642 248.197 ;
     RECT  145.656 248.071 146.214 248.261 ;
     RECT  139.788 248.197 141.642 248.773 ;
     RECT  142.815 248.161 144.882 248.845 ;
     RECT  145.656 248.261 146.106 248.845 ;
     RECT  142.815 248.845 146.106 248.999 ;
     RECT  142.815 248.999 145.71 249.071 ;
     RECT  145.548 249.071 145.71 249.143 ;
     RECT  145.692 249.143 145.71 249.149 ;
     RECT  137.196 246.451 137.934 249.269 ;
     RECT  137.196 249.269 137.697 249.305 ;
     RECT  142.815 249.071 144.702 249.305 ;
     RECT  139.788 248.773 141.786 249.313 ;
     RECT  142.815 249.305 144.558 249.313 ;
     RECT  139.788 249.313 144.558 249.341 ;
     RECT  139.788 249.341 144.414 249.449 ;
     RECT  140.544 249.449 144.414 249.539 ;
     RECT  140.544 249.539 140.886 249.575 ;
     RECT  140.688 249.575 140.886 249.629 ;
     RECT  141.624 249.539 141.822 249.647 ;
     RECT  143.892 249.539 144.09 249.647 ;
     RECT  139.788 249.449 139.806 249.677 ;
     RECT  141.624 249.647 141.678 249.677 ;
     RECT  140.868 249.629 140.886 249.683 ;
     RECT  141.66 249.677 141.678 249.683 ;
     RECT  142.815 249.539 143.154 249.683 ;
     RECT  143.892 249.647 143.91 249.683 ;
     RECT  132.015 247.379 133.074 258.719 ;
     RECT  130.608 234.845 130.626 276.475 ;
     RECT  130.212 276.475 130.626 276.955 ;
     RECT  129.888 276.955 130.626 276.96 ;
     RECT  129.885 276.96 130.626 276.987 ;
     RECT  129.888 276.987 130.626 276.989 ;
     RECT  130.608 276.989 130.626 287.069 ;
     RECT  132.015 258.719 132.498 287.221 ;
     RECT  2.415 188.015 2.697 369.107 ;
     RECT  7.815 2.413 8.097 369.107 ;
     RECT  13.215 2.413 13.497 369.107 ;
     RECT  18.615 2.413 18.897 369.107 ;
     RECT  24.015 2.413 24.297 369.107 ;
     RECT  29.415 2.413 29.697 369.107 ;
     RECT  34.815 2.413 35.097 369.107 ;
     RECT  40.215 2.413 40.497 369.107 ;
     RECT  45.615 2.413 45.897 369.107 ;
     RECT  51.015 2.413 51.297 369.107 ;
     RECT  56.415 2.413 56.697 369.107 ;
     RECT  61.815 2.413 62.097 369.107 ;
     RECT  67.215 2.413 67.497 369.107 ;
     RECT  72.615 2.413 72.897 369.107 ;
     RECT  78.015 2.413 78.297 369.107 ;
     RECT  83.415 2.413 83.697 369.107 ;
     RECT  88.815 2.413 89.097 369.107 ;
     RECT  94.215 186.161 94.497 369.107 ;
     RECT  99.615 196.619 99.897 369.107 ;
     RECT  105.015 198.815 105.297 369.107 ;
     RECT  110.415 198.581 110.697 369.107 ;
     RECT  115.815 180.701 116.097 369.107 ;
     RECT  121.215 195.449 121.497 369.107 ;
     RECT  126.615 219.209 126.897 369.107 ;
     RECT  137.415 249.305 137.697 369.107 ;
     RECT  142.815 249.683 143.097 369.107 ;
     RECT  148.215 245.021 148.497 369.107 ;
     RECT  153.615 230.243 153.897 369.107 ;
     RECT  159.015 223.889 159.297 369.107 ;
     RECT  164.415 175.469 164.697 369.107 ;
     RECT  169.815 2.413 170.097 369.107 ;
     RECT  175.215 175.469 175.497 369.107 ;
     RECT  180.615 2.413 180.897 369.107 ;
     RECT  186.015 175.469 186.297 369.107 ;
     RECT  191.415 2.413 191.697 369.107 ;
     RECT  196.815 175.469 197.097 369.107 ;
     RECT  202.215 176.369 202.497 369.107 ;
     RECT  207.615 175.469 207.897 369.107 ;
     RECT  213.015 2.413 213.297 369.107 ;
     RECT  218.415 175.469 218.697 369.107 ;
     RECT  223.815 2.413 224.097 369.107 ;
     RECT  229.215 175.469 229.497 369.107 ;
     RECT  234.615 2.413 234.897 369.107 ;
     RECT  240.015 175.469 240.297 369.107 ;
     RECT  245.415 181.769 245.697 369.107 ;
     RECT  2.415 369.107 2.505 369.377 ;
     RECT  7.815 369.107 7.905 369.377 ;
     RECT  13.215 369.107 13.305 369.377 ;
     RECT  18.615 369.107 18.705 369.377 ;
     RECT  24.015 369.107 24.105 369.377 ;
     RECT  29.415 369.107 29.505 369.377 ;
     RECT  34.815 369.107 34.905 369.377 ;
     RECT  40.215 369.107 40.305 369.377 ;
     RECT  45.615 369.107 45.705 369.377 ;
     RECT  51.015 369.107 51.105 369.377 ;
     RECT  56.415 369.107 56.505 369.377 ;
     RECT  61.815 369.107 61.905 369.377 ;
     RECT  67.215 369.107 67.305 369.377 ;
     RECT  72.615 369.107 72.705 369.377 ;
     RECT  78.015 369.107 78.105 369.377 ;
     RECT  83.415 369.107 83.505 369.377 ;
     RECT  88.815 369.107 88.905 369.377 ;
     RECT  94.215 369.107 94.305 369.377 ;
     RECT  99.615 369.107 99.705 369.377 ;
     RECT  105.015 369.107 105.105 369.377 ;
     RECT  110.415 369.107 110.505 369.377 ;
     RECT  115.815 369.107 115.905 369.377 ;
     RECT  121.215 369.107 121.305 369.377 ;
     RECT  126.615 369.107 126.705 369.377 ;
     RECT  131.292 287.221 132.498 369.377 ;
     RECT  137.415 369.107 137.505 369.377 ;
     RECT  142.815 369.107 142.905 369.377 ;
     RECT  148.215 369.107 148.305 369.377 ;
     RECT  153.615 369.107 153.705 369.377 ;
     RECT  159.015 369.107 159.105 369.377 ;
     RECT  164.415 369.107 164.505 369.377 ;
     RECT  169.815 369.107 169.905 369.377 ;
     RECT  175.215 369.107 175.305 369.377 ;
     RECT  180.615 369.107 180.705 369.377 ;
     RECT  186.015 369.107 186.105 369.377 ;
     RECT  191.415 369.107 191.505 369.377 ;
     RECT  196.815 369.107 196.905 369.377 ;
     RECT  202.215 369.107 202.305 369.377 ;
     RECT  207.615 369.107 207.705 369.377 ;
     RECT  213.015 369.107 213.105 369.377 ;
     RECT  218.415 369.107 218.505 369.377 ;
     RECT  223.815 369.107 223.905 369.377 ;
     RECT  229.215 369.107 229.305 369.377 ;
     RECT  234.615 369.107 234.705 369.377 ;
     RECT  240.015 369.107 240.105 369.377 ;
     RECT  245.415 369.107 245.505 369.377 ;
     RECT  132.48 369.377 132.498 369.917 ;
     RECT  131.292 369.377 131.31 370.541 ;
    LAYER M4 ;
     RECT  0.06 161.52 0.097 161.928 ;
     RECT  0.06 182.64 0.133 185.64 ;
     RECT  0.133 182.352 0.181 185.64 ;
     RECT  0.181 182.16 0.229 185.64 ;
     RECT  0.229 181.92 0.277 185.832 ;
     RECT  0.277 181.92 0.325 186.408 ;
     RECT  0.325 181.92 0.517 186.984 ;
     RECT  0.097 161.52 2.408 162.12 ;
     RECT  0.277 179.472 2.408 179.496 ;
     RECT  0.325 180.816 2.408 180.84 ;
     RECT  0.517 181.92 2.408 187.032 ;
     RECT  2.408 2.148 2.512 369.372 ;
     RECT  2.512 2.418 2.704 369.102 ;
     RECT  2.704 161.52 2.801 162.12 ;
     RECT  2.704 182.928 2.837 182.952 ;
     RECT  2.704 185.04 2.837 185.736 ;
     RECT  2.704 186.96 2.867 186.984 ;
     RECT  2.837 185.136 2.909 185.736 ;
     RECT  2.801 161.52 3.089 161.88 ;
     RECT  2.909 185.712 3.449 185.736 ;
     RECT  3.089 161.52 7.808 161.544 ;
     RECT  7.808 2.148 7.912 369.372 ;
     RECT  7.912 2.418 8.104 369.102 ;
     RECT  8.104 161.52 13.208 161.544 ;
     RECT  13.208 2.148 13.312 369.372 ;
     RECT  13.312 2.418 13.504 369.102 ;
     RECT  13.504 161.52 18.608 161.544 ;
     RECT  18.608 2.148 18.712 369.372 ;
     RECT  18.712 2.418 18.904 369.102 ;
     RECT  18.904 161.52 24.008 161.544 ;
     RECT  24.008 2.148 24.112 369.372 ;
     RECT  24.112 2.418 24.304 369.102 ;
     RECT  24.304 161.52 29.408 161.544 ;
     RECT  29.408 2.148 29.512 369.372 ;
     RECT  29.512 2.418 29.704 369.102 ;
     RECT  29.704 161.52 34.808 161.544 ;
     RECT  34.808 2.148 34.912 369.372 ;
     RECT  34.912 2.418 35.104 369.102 ;
     RECT  35.104 161.52 40.208 161.544 ;
     RECT  40.208 2.148 40.312 369.372 ;
     RECT  40.312 2.418 40.504 369.102 ;
     RECT  40.504 161.52 45.608 161.544 ;
     RECT  45.608 2.148 45.712 369.372 ;
     RECT  45.712 2.418 45.904 369.102 ;
     RECT  45.904 161.52 51.008 161.544 ;
     RECT  51.008 2.148 51.112 369.372 ;
     RECT  51.112 2.418 51.304 369.102 ;
     RECT  51.304 161.52 56.408 161.544 ;
     RECT  56.408 2.148 56.512 369.372 ;
     RECT  56.512 2.418 56.704 369.102 ;
     RECT  56.704 161.52 61.808 161.544 ;
     RECT  61.808 2.148 61.912 369.372 ;
     RECT  61.912 2.418 62.104 369.102 ;
     RECT  62.104 161.52 67.208 161.544 ;
     RECT  67.208 2.148 67.312 369.372 ;
     RECT  67.312 2.418 67.504 369.102 ;
     RECT  67.504 161.52 72.608 161.544 ;
     RECT  72.608 2.148 72.712 369.372 ;
     RECT  72.712 2.418 72.904 369.102 ;
     RECT  72.904 161.52 78.008 161.544 ;
     RECT  78.008 2.148 78.112 369.372 ;
     RECT  78.112 2.418 78.304 369.102 ;
     RECT  78.304 161.52 83.408 161.544 ;
     RECT  83.408 2.148 83.512 369.372 ;
     RECT  83.512 2.418 83.704 369.102 ;
     RECT  83.704 161.52 88.808 161.544 ;
     RECT  88.808 2.148 88.912 369.372 ;
     RECT  88.912 2.418 89.104 369.102 ;
     RECT  89.104 161.52 94.208 161.544 ;
     RECT  94.208 2.148 94.312 369.372 ;
     RECT  94.312 2.418 94.504 369.102 ;
     RECT  94.504 185.424 95.363 186.696 ;
     RECT  94.504 182.976 95.933 183 ;
     RECT  96.865 181.44 96.997 181.464 ;
     RECT  96.289 182.832 96.997 182.856 ;
     RECT  96.289 184.08 97.045 184.104 ;
     RECT  97.045 184.08 97.081 184.632 ;
     RECT  95.363 185.808 97.081 186.696 ;
     RECT  96.109 187.968 97.193 187.992 ;
     RECT  95.605 177.792 97.333 177.816 ;
     RECT  97.333 177.792 97.373 178.392 ;
     RECT  97.373 178.368 97.379 178.392 ;
     RECT  97.117 180 97.657 180.024 ;
     RECT  97.081 184.08 97.733 186.696 ;
     RECT  97.733 184.656 97.801 186.696 ;
     RECT  97.549 169.2 97.945 169.224 ;
     RECT  96.865 170.976 98.089 171 ;
     RECT  96.997 181.44 98.089 182.856 ;
     RECT  97.945 169.2 98.101 169.56 ;
     RECT  98.089 170.976 98.101 171.384 ;
     RECT  98.101 169.2 98.147 172.104 ;
     RECT  98.147 172.08 98.233 172.104 ;
     RECT  98.089 181.44 98.269 183.528 ;
     RECT  98.233 172.08 98.293 172.92 ;
     RECT  97.729 174.192 98.293 174.216 ;
     RECT  97.657 179.136 98.413 180.024 ;
     RECT  98.377 165.264 98.449 165.288 ;
     RECT  97.801 184.656 98.485 187.032 ;
     RECT  97.981 188.016 98.485 188.04 ;
     RECT  98.293 172.08 98.521 174.216 ;
     RECT  98.485 184.656 98.579 188.04 ;
     RECT  98.449 165.264 98.593 165.624 ;
     RECT  98.147 169.2 98.629 170.424 ;
     RECT  98.269 181.248 98.633 183.528 ;
     RECT  98.413 176.928 98.665 176.952 ;
     RECT  98.413 178.416 98.665 180.024 ;
     RECT  98.629 164.112 98.773 164.136 ;
     RECT  98.593 165.264 98.773 165.912 ;
     RECT  98.533 190.704 98.953 190.728 ;
     RECT  98.521 172.08 99.097 174.552 ;
     RECT  98.953 190.704 99.133 191.256 ;
     RECT  98.665 176.928 99.157 180.024 ;
     RECT  98.773 164.112 99.277 165.912 ;
     RECT  99.157 176.112 99.313 180.024 ;
     RECT  99.313 176.112 99.349 180.072 ;
     RECT  98.633 181.248 99.349 182.856 ;
     RECT  99.097 172.08 99.421 174.84 ;
     RECT  99.349 176.112 99.421 182.856 ;
     RECT  99.277 164.112 99.565 166.488 ;
     RECT  99.493 167.472 99.565 167.496 ;
     RECT  94.504 161.52 99.608 161.544 ;
     RECT  99.565 164.112 99.608 167.544 ;
     RECT  98.629 168.672 99.608 170.424 ;
     RECT  99.421 172.08 99.608 182.856 ;
     RECT  99.205 184.032 99.608 184.056 ;
     RECT  98.579 185.04 99.608 188.04 ;
     RECT  99.133 189.84 99.608 191.256 ;
     RECT  99.608 2.148 99.712 369.372 ;
     RECT  99.712 2.418 99.904 369.102 ;
     RECT  99.904 168.048 100.001 169.368 ;
     RECT  99.904 171.36 100.019 173.256 ;
     RECT  99.904 189.984 100.037 190.728 ;
     RECT  99.904 174.336 100.289 188.664 ;
     RECT  100.289 174.336 100.433 188.088 ;
     RECT  100.019 172.08 100.505 173.064 ;
     RECT  99.904 164.256 100.541 166.392 ;
     RECT  100.433 179.664 100.547 188.088 ;
     RECT  100.037 189.984 100.865 190.44 ;
     RECT  100.001 168.528 100.933 169.368 ;
     RECT  100.505 172.752 100.981 173.064 ;
     RECT  100.433 174.336 100.981 178.68 ;
     RECT  100.547 179.664 101.009 185.832 ;
     RECT  100.547 186.816 101.027 188.088 ;
     RECT  99.904 192.336 101.149 192.36 ;
     RECT  101.009 180.672 101.189 185.832 ;
     RECT  101.149 192.336 101.257 192.6 ;
     RECT  101.257 192.336 101.269 193.416 ;
     RECT  101.257 194.4 101.269 194.424 ;
     RECT  100.541 164.544 101.293 166.392 ;
     RECT  100.981 172.752 101.297 178.68 ;
     RECT  100.865 189.984 101.315 190.008 ;
     RECT  101.297 174.336 101.333 178.68 ;
     RECT  99.904 195.696 101.365 195.72 ;
     RECT  101.333 174.336 101.369 177.528 ;
     RECT  101.293 164.544 101.461 167.256 ;
     RECT  100.933 168.528 101.461 169.896 ;
     RECT  101.027 187.152 101.473 188.088 ;
     RECT  100.897 170.976 101.509 171 ;
     RECT  101.269 192.336 101.509 194.424 ;
     RECT  101.365 195.696 101.509 195.816 ;
     RECT  101.473 187.152 101.797 188.664 ;
     RECT  101.509 192.336 101.797 195.816 ;
     RECT  101.461 164.544 101.801 169.896 ;
     RECT  101.845 197.184 101.909 197.208 ;
     RECT  101.009 179.664 101.977 179.688 ;
     RECT  101.189 180.672 101.977 181.848 ;
     RECT  101.333 178.512 102.085 178.68 ;
     RECT  101.977 179.664 102.085 181.848 ;
     RECT  101.797 192.048 102.121 195.816 ;
     RECT  101.545 198.24 102.133 198.264 ;
     RECT  101.369 175.248 102.161 177.528 ;
     RECT  102.085 189.84 102.161 189.864 ;
     RECT  101.509 170.976 102.193 171.576 ;
     RECT  101.297 172.752 102.193 173.016 ;
     RECT  101.797 187.152 102.337 188.712 ;
     RECT  102.161 175.392 102.413 177.528 ;
     RECT  101.801 168.144 102.445 169.896 ;
     RECT  102.193 170.976 102.445 173.016 ;
     RECT  102.445 168.144 102.517 173.016 ;
     RECT  102.517 168.144 102.521 173.976 ;
     RECT  102.121 192.048 102.565 196.776 ;
     RECT  102.521 168.288 102.593 173.976 ;
     RECT  102.565 191.472 102.611 196.776 ;
     RECT  101.801 164.544 102.665 166.44 ;
     RECT  102.593 168.288 102.665 170.76 ;
     RECT  102.085 178.512 102.665 181.848 ;
     RECT  102.613 190.416 102.665 190.44 ;
     RECT  102.665 164.544 102.697 164.76 ;
     RECT  102.413 177.504 102.733 177.528 ;
     RECT  102.665 178.512 102.733 179.112 ;
     RECT  102.733 177.504 102.809 179.112 ;
     RECT  102.593 172.32 102.881 173.976 ;
     RECT  102.611 191.472 102.881 195.816 ;
     RECT  102.881 172.32 102.899 173.304 ;
     RECT  102.665 169.872 102.995 170.76 ;
     RECT  102.337 187.152 103.021 189.384 ;
     RECT  102.665 166.128 103.057 166.44 ;
     RECT  101.189 182.928 103.057 185.832 ;
     RECT  103.021 186.864 103.057 189.384 ;
     RECT  102.665 180.24 103.093 181.848 ;
     RECT  103.057 182.928 103.093 189.384 ;
     RECT  102.133 198.192 103.093 198.264 ;
     RECT  103.093 180.24 103.133 189.384 ;
     RECT  103.133 180.24 103.187 188.808 ;
     RECT  102.697 164.304 103.237 164.76 ;
     RECT  102.413 175.392 103.273 176.472 ;
     RECT  103.093 198.192 103.381 198.36 ;
     RECT  103.187 184.128 103.385 188.808 ;
     RECT  103.381 197.184 103.427 197.208 ;
     RECT  103.057 166.128 103.489 166.488 ;
     RECT  102.881 191.76 103.523 195.816 ;
     RECT  103.237 164.112 103.571 164.76 ;
     RECT  102.899 172.32 103.597 173.256 ;
     RECT  103.273 175.056 103.597 176.472 ;
     RECT  103.489 166.128 103.705 167.208 ;
     RECT  102.665 168.288 103.705 168.888 ;
     RECT  103.597 172.128 103.705 173.256 ;
     RECT  103.187 180.24 103.745 183.144 ;
     RECT  102.995 169.968 103.765 170.76 ;
     RECT  103.705 171.84 103.765 173.256 ;
     RECT  103.381 198.192 103.813 198.456 ;
     RECT  103.777 190.416 103.861 190.44 ;
     RECT  103.523 191.76 103.861 195.576 ;
     RECT  103.813 197.712 103.925 198.456 ;
     RECT  102.809 177.504 103.957 178.968 ;
     RECT  103.745 180.24 103.957 181.8 ;
     RECT  103.861 190.416 103.997 195.576 ;
     RECT  103.705 166.128 104.173 168.888 ;
     RECT  103.597 174.528 104.245 176.472 ;
     RECT  103.957 177.504 104.245 181.8 ;
     RECT  103.765 169.968 104.389 173.256 ;
     RECT  103.385 184.32 104.389 188.808 ;
     RECT  104.389 169.968 104.425 173.496 ;
     RECT  104.245 174.528 104.425 181.8 ;
     RECT  104.389 184.224 104.461 188.808 ;
     RECT  104.173 165.936 104.533 168.888 ;
     RECT  104.533 165.312 104.569 168.888 ;
     RECT  104.425 169.968 104.569 181.8 ;
     RECT  103.571 164.112 104.641 164.328 ;
     RECT  104.569 165.312 104.641 181.8 ;
     RECT  104.461 184.224 104.785 189.288 ;
     RECT  103.997 190.416 104.785 190.968 ;
     RECT  103.745 182.928 104.857 183.144 ;
     RECT  104.785 184.224 104.857 190.968 ;
     RECT  104.869 196.896 104.893 196.92 ;
     RECT  104.857 182.928 105.001 190.968 ;
     RECT  103.997 192.048 105.001 195.576 ;
     RECT  99.904 161.52 105.008 161.544 ;
     RECT  104.641 164.112 105.008 181.8 ;
     RECT  105.001 182.928 105.008 195.576 ;
     RECT  104.893 196.656 105.008 196.92 ;
     RECT  103.925 197.904 105.008 198.36 ;
     RECT  105.008 2.148 105.112 369.372 ;
     RECT  105.112 2.418 105.304 369.102 ;
     RECT  105.304 169.968 105.443 174.6 ;
     RECT  105.304 165.84 105.473 165.96 ;
     RECT  105.304 194.592 105.473 195.576 ;
     RECT  105.304 183.648 105.491 192.648 ;
     RECT  105.443 171.552 105.509 174.6 ;
     RECT  105.491 183.648 105.509 190.728 ;
     RECT  105.304 177.792 105.581 182.184 ;
     RECT  105.509 183.648 105.581 189.672 ;
     RECT  105.304 164.304 105.689 164.328 ;
     RECT  105.304 176.448 105.779 176.76 ;
     RECT  105.443 169.968 105.797 169.992 ;
     RECT  105.304 196.656 105.827 198.264 ;
     RECT  105.473 165.936 105.941 165.96 ;
     RECT  105.581 183.648 105.977 189.48 ;
     RECT  105.977 189.072 106.049 189.48 ;
     RECT  105.827 197.424 106.085 198.264 ;
     RECT  105.581 179.472 106.163 182.184 ;
     RECT  105.509 171.552 106.229 174.552 ;
     RECT  106.163 181.68 106.297 182.184 ;
     RECT  105.977 183.648 106.297 188.088 ;
     RECT  105.509 190.704 106.301 190.728 ;
     RECT  105.304 167.28 106.333 168.888 ;
     RECT  106.297 181.68 106.355 188.088 ;
     RECT  106.229 171.552 106.373 174.456 ;
     RECT  106.333 167.28 106.403 169.224 ;
     RECT  106.373 171.552 106.403 173.256 ;
     RECT  106.403 171.552 106.597 172.152 ;
     RECT  105.491 191.808 106.625 192.648 ;
     RECT  106.597 170.976 106.661 172.152 ;
     RECT  105.581 177.792 106.729 178.392 ;
     RECT  105.473 194.976 106.741 195.576 ;
     RECT  106.729 177.696 106.765 178.392 ;
     RECT  106.163 179.472 106.765 180.6 ;
     RECT  106.403 173.232 106.877 173.256 ;
     RECT  106.355 183.744 106.985 188.088 ;
     RECT  106.049 189.312 107.053 189.48 ;
     RECT  106.765 177.696 107.057 180.6 ;
     RECT  106.985 184.128 107.089 188.088 ;
     RECT  107.053 189.312 107.089 189.864 ;
     RECT  106.085 197.424 107.089 197.448 ;
     RECT  106.945 198.624 107.089 198.648 ;
     RECT  107.057 177.696 107.093 177.816 ;
     RECT  106.661 171.6 107.129 172.152 ;
     RECT  106.403 167.28 107.201 168.36 ;
     RECT  106.625 191.808 107.269 192.6 ;
     RECT  107.089 184.128 107.377 189.864 ;
     RECT  107.269 190.896 107.377 192.6 ;
     RECT  106.355 181.68 107.413 182.376 ;
     RECT  107.129 172.128 107.453 172.152 ;
     RECT  107.377 184.128 107.459 192.6 ;
     RECT  106.373 174.432 107.525 174.456 ;
     RECT  107.057 178.848 107.597 180.6 ;
     RECT  107.413 181.68 107.597 183.144 ;
     RECT  106.741 194.976 107.605 196.056 ;
     RECT  107.089 197.424 107.605 198.648 ;
     RECT  107.459 184.656 107.705 192.6 ;
     RECT  105.304 161.52 107.813 161.544 ;
     RECT  107.597 181.68 107.845 181.8 ;
     RECT  107.597 182.832 107.891 183.144 ;
     RECT  107.605 194.976 108.065 198.648 ;
     RECT  107.891 183.12 108.133 183.144 ;
     RECT  107.705 191.808 108.133 192.6 ;
     RECT  106.765 193.68 108.133 193.704 ;
     RECT  107.093 177.792 108.169 177.816 ;
     RECT  108.133 183.12 108.179 183.672 ;
     RECT  107.705 184.656 108.227 190.248 ;
     RECT  108.227 184.656 108.245 189.912 ;
     RECT  108.169 177.792 108.529 177.864 ;
     RECT  108.245 188.64 108.533 189.912 ;
     RECT  108.529 177.744 108.565 177.864 ;
     RECT  107.597 178.848 108.565 179.064 ;
     RECT  108.565 177.744 108.637 179.064 ;
     RECT  107.597 180.432 108.637 180.456 ;
     RECT  108.637 177.744 108.661 180.456 ;
     RECT  107.845 181.632 108.661 181.8 ;
     RECT  108.661 177.744 108.673 181.8 ;
     RECT  108.673 177.744 108.707 181.848 ;
     RECT  108.707 180.432 108.713 181.848 ;
     RECT  108.707 177.744 108.745 178.968 ;
     RECT  108.133 191.808 108.781 193.704 ;
     RECT  108.179 183.12 108.821 183.528 ;
     RECT  108.745 177.696 108.857 178.968 ;
     RECT  108.245 184.656 108.857 187.416 ;
     RECT  108.857 177.744 108.929 178.968 ;
     RECT  108.857 184.656 108.961 187.032 ;
     RECT  108.061 175.584 109.037 175.608 ;
     RECT  108.781 191.76 109.141 193.704 ;
     RECT  108.065 194.976 109.141 197.832 ;
     RECT  108.533 188.688 109.181 189.912 ;
     RECT  109.069 171.408 109.217 171.432 ;
     RECT  108.713 181.632 109.249 181.848 ;
     RECT  109.181 188.928 109.285 189.912 ;
     RECT  109.285 188.928 109.321 190.68 ;
     RECT  109.141 191.76 109.321 197.832 ;
     RECT  109.321 188.928 109.361 197.832 ;
     RECT  108.713 180.432 110.077 180.456 ;
     RECT  109.249 181.632 110.077 182.232 ;
     RECT  108.821 183.504 110.077 183.528 ;
     RECT  108.929 177.792 110.293 177.864 ;
     RECT  110.077 180.432 110.293 183.528 ;
     RECT  108.961 184.608 110.293 187.032 ;
     RECT  107.201 167.28 110.408 167.304 ;
     RECT  107.201 168.336 110.408 168.36 ;
     RECT  109.393 171.024 110.408 171.048 ;
     RECT  110.293 177.744 110.408 177.864 ;
     RECT  108.929 178.848 110.408 178.968 ;
     RECT  110.293 180.432 110.408 187.032 ;
     RECT  109.361 188.928 110.408 191.784 ;
     RECT  109.361 192.864 110.408 197.832 ;
     RECT  110.408 2.148 110.512 369.372 ;
     RECT  110.512 2.418 110.704 369.102 ;
     RECT  110.704 193.68 110.873 195 ;
     RECT  110.704 187.44 111.233 191.784 ;
     RECT  110.704 178.848 111.305 178.968 ;
     RECT  111.233 187.44 111.341 191.352 ;
     RECT  110.873 194.208 111.485 195 ;
     RECT  110.704 170.304 111.491 171.576 ;
     RECT  111.341 187.44 111.521 189.864 ;
     RECT  111.341 191.232 111.557 191.352 ;
     RECT  111.521 188.352 111.587 189.864 ;
     RECT  111.557 191.232 111.593 191.256 ;
     RECT  110.704 180.432 111.701 186.168 ;
     RECT  111.491 171.552 111.731 171.576 ;
     RECT  111.701 180.432 111.731 182.712 ;
     RECT  111.701 184.08 111.731 186.168 ;
     RECT  111.731 180.432 111.737 182.28 ;
     RECT  111.587 188.688 111.737 189.864 ;
     RECT  111.731 186.096 111.773 186.168 ;
     RECT  111.737 180.432 111.779 180.696 ;
     RECT  111.737 181.968 111.779 182.28 ;
     RECT  111.779 181.968 111.809 181.992 ;
     RECT  111.913 186.288 111.971 186.984 ;
     RECT  111.731 184.08 112.163 184.728 ;
     RECT  112.163 184.704 112.169 184.728 ;
     RECT  111.737 189.36 112.205 189.864 ;
     RECT  111.971 186.288 112.637 186.312 ;
     RECT  111.491 170.304 112.997 170.328 ;
     RECT  113.029 170.208 114.325 170.232 ;
     RECT  111.779 180.672 114.865 180.696 ;
     RECT  110.704 167.28 114.901 167.304 ;
     RECT  110.704 168.336 114.901 168.36 ;
     RECT  114.901 166.896 115.808 167.304 ;
     RECT  114.901 168.288 115.808 168.36 ;
     RECT  114.325 169.968 115.808 170.232 ;
     RECT  110.704 177.696 115.808 177.72 ;
     RECT  114.865 180.144 115.808 180.696 ;
     RECT  112.205 189.36 115.808 189.384 ;
     RECT  111.485 194.976 115.808 195 ;
     RECT  115.808 2.148 115.912 369.372 ;
     RECT  115.912 2.418 116.104 369.102 ;
     RECT  116.104 167.28 116.381 168.84 ;
     RECT  116.381 167.376 116.387 168.84 ;
     RECT  116.104 180.528 116.453 180.696 ;
     RECT  116.453 180.672 118.573 180.696 ;
     RECT  118.573 180.528 118.613 180.696 ;
     RECT  116.104 177.696 119.689 177.72 ;
     RECT  119.689 177.696 120.805 178.632 ;
     RECT  116.104 194.976 121.057 195 ;
     RECT  120.805 176.88 121.093 178.872 ;
     RECT  120.121 162.192 121.208 162.216 ;
     RECT  121.093 163.536 121.208 163.56 ;
     RECT  116.387 168.288 121.208 168.84 ;
     RECT  116.104 169.968 121.208 170.232 ;
     RECT  120.481 173.424 121.208 173.448 ;
     RECT  120.301 175.536 121.208 175.56 ;
     RECT  121.093 176.736 121.208 178.872 ;
     RECT  118.613 180.528 121.208 180.552 ;
     RECT  116.104 189.36 121.208 189.384 ;
     RECT  121.057 194.976 121.208 195.384 ;
     RECT  121.208 2.148 121.312 369.372 ;
     RECT  121.312 2.418 121.504 369.102 ;
     RECT  121.504 172.608 121.619 173.784 ;
     RECT  121.504 162.096 121.955 162.216 ;
     RECT  121.504 167.472 121.955 168.84 ;
     RECT  121.619 173.28 122.357 173.784 ;
     RECT  121.504 184.56 122.357 185.592 ;
     RECT  122.357 185.52 122.429 185.592 ;
     RECT  121.504 186.864 122.483 188.088 ;
     RECT  121.955 167.568 122.485 168.84 ;
     RECT  121.504 169.968 122.485 171 ;
     RECT  122.483 188.064 122.497 188.088 ;
     RECT  121.504 189.36 122.497 189.384 ;
     RECT  121.504 175.824 122.569 178.968 ;
     RECT  121.504 180.528 122.605 180.552 ;
     RECT  122.429 185.568 122.713 185.592 ;
     RECT  122.605 180.528 122.725 180.696 ;
     RECT  122.713 185.568 122.771 185.832 ;
     RECT  122.725 180.144 122.857 181.224 ;
     RECT  121.504 182.208 122.857 182.232 ;
     RECT  122.569 175.68 122.861 178.968 ;
     RECT  122.485 167.568 122.897 171 ;
     RECT  121.955 162.096 122.915 162.12 ;
     RECT  121.504 194.976 122.929 195.384 ;
     RECT  122.869 160.608 122.933 161.112 ;
     RECT  122.497 188.064 122.969 189.384 ;
     RECT  122.929 194.976 123.001 195.672 ;
     RECT  122.857 180.144 123.011 182.232 ;
     RECT  122.861 175.68 123.149 176.184 ;
     RECT  123.149 175.68 123.185 175.992 ;
     RECT  123.011 180.672 123.217 182.232 ;
     RECT  123.289 175.584 123.397 175.608 ;
     RECT  122.357 173.76 123.433 173.784 ;
     RECT  123.217 180.672 123.433 182.376 ;
     RECT  123.397 175.056 123.443 175.608 ;
     RECT  121.504 165.312 123.541 165.336 ;
     RECT  123.433 173.616 123.577 173.784 ;
     RECT  123.001 194.16 123.613 195.672 ;
     RECT  123.613 194.16 123.683 196.104 ;
     RECT  123.541 165.312 123.685 165.528 ;
     RECT  122.861 177.216 123.685 178.968 ;
     RECT  123.541 203.328 123.685 203.352 ;
     RECT  123.433 180.672 123.721 182.424 ;
     RECT  123.685 177.216 123.725 179.496 ;
     RECT  122.771 185.568 123.725 185.592 ;
     RECT  123.685 203.328 123.731 204.312 ;
     RECT  121.504 163.44 123.733 163.56 ;
     RECT  123.685 164.736 123.733 166.44 ;
     RECT  122.969 189.36 123.761 189.384 ;
     RECT  123.725 179.472 123.827 179.496 ;
     RECT  123.721 180.672 123.827 182.616 ;
     RECT  122.933 161.088 123.869 161.112 ;
     RECT  123.733 162.72 123.901 166.44 ;
     RECT  122.897 167.568 123.937 170.424 ;
     RECT  123.001 171.456 123.937 171.48 ;
     RECT  123.901 162.48 123.941 166.44 ;
     RECT  123.941 163.536 124.009 166.44 ;
     RECT  123.937 167.568 124.009 171.48 ;
     RECT  123.685 202.32 124.013 202.344 ;
     RECT  124.009 163.536 124.045 171.48 ;
     RECT  124.045 163.536 124.049 172.104 ;
     RECT  123.469 191.472 124.121 191.496 ;
     RECT  123.145 192.576 124.121 192.6 ;
     RECT  123.577 173.616 124.259 174.456 ;
     RECT  124.259 173.616 124.261 174.36 ;
     RECT  122.483 186.864 124.261 186.888 ;
     RECT  123.941 162.48 124.301 162.504 ;
     RECT  123.827 181.2 124.513 182.616 ;
     RECT  124.049 163.536 124.547 167.064 ;
     RECT  124.547 164.304 124.553 167.064 ;
     RECT  124.553 164.736 124.595 167.064 ;
     RECT  123.725 177.216 124.693 178.392 ;
     RECT  124.549 193.008 124.693 193.032 ;
     RECT  123.683 194.16 124.693 195.672 ;
     RECT  124.693 193.008 124.739 195.672 ;
     RECT  124.513 181.2 124.789 182.952 ;
     RECT  124.225 184.56 124.789 184.584 ;
     RECT  124.789 181.2 124.835 184.584 ;
     RECT  122.969 188.064 124.837 188.088 ;
     RECT  124.739 194.352 124.837 195.672 ;
     RECT  124.261 173.28 124.877 174.36 ;
     RECT  124.765 190.176 124.883 190.2 ;
     RECT  124.837 188.064 124.885 188.808 ;
     RECT  124.835 183.696 124.909 184.584 ;
     RECT  124.837 194.352 124.913 196.104 ;
     RECT  124.693 177.216 124.981 178.968 ;
     RECT  124.909 183.696 124.981 184.728 ;
     RECT  124.981 176.736 125.017 178.968 ;
     RECT  124.981 183.696 125.017 184.824 ;
     RECT  124.835 181.2 125.021 182.568 ;
     RECT  124.261 186.384 125.021 186.888 ;
     RECT  124.885 188.016 125.021 188.808 ;
     RECT  124.913 194.976 125.053 196.104 ;
     RECT  125.017 183.696 125.057 185.112 ;
     RECT  124.595 166.464 125.125 167.064 ;
     RECT  124.049 168.288 125.125 172.104 ;
     RECT  125.017 176.592 125.129 178.968 ;
     RECT  125.125 166.464 125.171 173.016 ;
     RECT  125.053 194.976 125.197 196.248 ;
     RECT  125.129 176.736 125.237 178.968 ;
     RECT  124.945 190.032 125.237 190.056 ;
     RECT  125.171 166.464 125.267 168.84 ;
     RECT  125.021 188.064 125.273 188.808 ;
     RECT  123.731 204.288 125.341 204.312 ;
     RECT  124.595 164.736 125.345 165.288 ;
     RECT  124.693 191.808 125.377 191.832 ;
     RECT  125.305 200.496 125.377 200.52 ;
     RECT  125.377 191.52 125.413 191.832 ;
     RECT  124.739 193.008 125.413 193.272 ;
     RECT  125.197 194.976 125.413 196.968 ;
     RECT  124.657 198.864 125.413 198.888 ;
     RECT  125.341 204.288 125.413 204.6 ;
     RECT  125.413 191.52 125.459 193.272 ;
     RECT  125.413 198.864 125.459 199.368 ;
     RECT  125.413 203.76 125.459 204.84 ;
     RECT  125.377 200.496 125.561 200.568 ;
     RECT  125.459 199.344 125.597 199.368 ;
     RECT  125.459 203.76 125.597 203.784 ;
     RECT  125.459 191.52 125.633 193.128 ;
     RECT  125.413 179.952 125.809 179.976 ;
     RECT  125.021 181.2 125.809 181.224 ;
     RECT  125.345 164.736 125.845 164.856 ;
     RECT  125.057 184.8 125.881 185.112 ;
     RECT  124.877 174.24 125.953 174.36 ;
     RECT  123.443 175.584 125.953 175.608 ;
     RECT  125.845 206.64 125.953 207.192 ;
     RECT  125.881 201.696 125.989 201.72 ;
     RECT  125.413 202.704 125.989 202.728 ;
     RECT  125.057 183.696 126.025 183.816 ;
     RECT  125.881 184.8 126.025 185.256 ;
     RECT  125.171 169.968 126.313 173.016 ;
     RECT  125.953 174.24 126.313 175.608 ;
     RECT  126.313 169.968 126.349 175.608 ;
     RECT  125.413 194.976 126.385 197.256 ;
     RECT  126.025 183.696 126.421 185.256 ;
     RECT  125.633 192.624 126.493 193.128 ;
     RECT  126.385 194.496 126.493 197.256 ;
     RECT  125.267 166.464 126.565 168.312 ;
     RECT  126.349 169.632 126.565 175.608 ;
     RECT  125.377 186.912 126.601 186.936 ;
     RECT  126.457 162.672 126.608 162.696 ;
     RECT  125.845 164.496 126.608 164.856 ;
     RECT  126.565 166.128 126.608 168.312 ;
     RECT  126.565 169.632 126.608 175.944 ;
     RECT  125.237 177.216 126.608 178.968 ;
     RECT  125.809 179.952 126.608 181.224 ;
     RECT  125.021 182.544 126.608 182.568 ;
     RECT  126.421 183.696 126.608 185.88 ;
     RECT  126.601 186.912 126.608 187.224 ;
     RECT  125.273 188.784 126.608 188.808 ;
     RECT  126.457 190.368 126.608 190.392 ;
     RECT  125.633 191.52 126.608 191.544 ;
     RECT  126.493 192.624 126.608 197.256 ;
     RECT  126.457 199.392 126.608 199.416 ;
     RECT  125.561 200.496 126.608 200.52 ;
     RECT  125.989 201.696 126.608 202.728 ;
     RECT  125.459 204.816 126.608 204.84 ;
     RECT  125.953 206.304 126.608 207.192 ;
     RECT  125.845 208.608 126.608 208.632 ;
     RECT  126.493 210.432 126.608 210.456 ;
     RECT  126.529 212.064 126.608 212.088 ;
     RECT  126.608 2.148 126.712 369.372 ;
     RECT  126.712 2.418 126.904 369.102 ;
     RECT  126.904 177.936 126.929 181.08 ;
     RECT  126.904 199.008 126.929 199.176 ;
     RECT  126.904 166.128 127.091 171.384 ;
     RECT  126.904 192.576 127.091 195 ;
     RECT  126.904 213.168 127.109 213.528 ;
     RECT  126.904 185.088 127.139 187.896 ;
     RECT  126.904 216.912 127.139 217.176 ;
     RECT  127.139 185.088 127.145 185.16 ;
     RECT  126.904 202.32 127.145 202.392 ;
     RECT  127.139 186.336 127.181 186.36 ;
     RECT  126.929 177.936 127.253 178.056 ;
     RECT  127.253 177.936 127.283 177.96 ;
     RECT  126.904 189.264 127.289 191.208 ;
     RECT  127.289 189.936 127.325 191.208 ;
     RECT  127.091 192.672 127.397 195 ;
     RECT  126.904 214.512 127.433 215.16 ;
     RECT  127.397 192.672 127.505 193.752 ;
     RECT  126.904 276.48 127.571 276.504 ;
     RECT  127.139 217.152 127.685 217.176 ;
     RECT  126.904 162.672 127.721 163.56 ;
     RECT  127.325 190.512 127.721 191.208 ;
     RECT  127.091 169.632 127.793 171.384 ;
     RECT  126.904 205.056 127.793 205.08 ;
     RECT  126.904 210.432 127.829 210.456 ;
     RECT  126.904 174.048 127.897 174.072 ;
     RECT  126.929 199.008 127.897 199.032 ;
     RECT  127.897 199.008 127.909 199.656 ;
     RECT  127.909 200.64 127.933 200.664 ;
     RECT  126.904 218.544 127.933 218.808 ;
     RECT  127.793 171.36 127.937 171.384 ;
     RECT  127.909 198.912 127.955 199.656 ;
     RECT  127.933 200.64 127.973 201.096 ;
     RECT  127.897 173.76 128.005 174.072 ;
     RECT  126.904 175.584 128.005 176.472 ;
     RECT  127.433 214.512 128.041 214.776 ;
     RECT  127.933 218.544 128.041 218.856 ;
     RECT  127.955 198.912 128.045 198.936 ;
     RECT  127.091 166.128 128.077 168.312 ;
     RECT  126.904 164.736 128.101 164.856 ;
     RECT  128.077 166.08 128.101 168.312 ;
     RECT  127.139 187.872 128.113 187.896 ;
     RECT  126.904 196.464 128.113 196.968 ;
     RECT  128.077 198.336 128.113 198.456 ;
     RECT  128.101 164.352 128.147 168.312 ;
     RECT  128.005 173.76 128.149 176.472 ;
     RECT  126.929 179.136 128.149 181.08 ;
     RECT  128.077 183.456 128.185 183.48 ;
     RECT  127.109 213.168 128.185 213.192 ;
     RECT  128.041 214.32 128.185 214.776 ;
     RECT  127.793 169.632 128.197 170.232 ;
     RECT  128.077 182.304 128.221 182.328 ;
     RECT  128.185 183.408 128.221 183.48 ;
     RECT  128.041 218.544 128.243 219.096 ;
     RECT  128.147 164.352 128.261 165.48 ;
     RECT  128.149 179.04 128.293 181.08 ;
     RECT  127.145 185.136 128.293 185.16 ;
     RECT  128.113 187.536 128.293 187.896 ;
     RECT  128.257 189.024 128.293 189.24 ;
     RECT  126.904 207.168 128.293 207.192 ;
     RECT  128.149 173.28 128.329 176.472 ;
     RECT  128.221 182.256 128.365 183.48 ;
     RECT  128.293 184.8 128.365 185.16 ;
     RECT  128.329 173.28 128.387 176.76 ;
     RECT  128.387 173.28 128.401 176.472 ;
     RECT  128.293 178.704 128.401 181.08 ;
     RECT  128.293 207.168 128.437 207.288 ;
     RECT  128.185 209.904 128.437 209.928 ;
     RECT  127.973 200.832 128.483 201.096 ;
     RECT  128.401 178.704 128.509 181.128 ;
     RECT  128.473 160.32 128.579 160.344 ;
     RECT  128.401 172.608 128.585 176.472 ;
     RECT  128.365 182.256 128.617 185.16 ;
     RECT  128.545 156.912 128.627 156.936 ;
     RECT  128.509 178.32 128.653 181.128 ;
     RECT  128.617 182.256 128.653 185.256 ;
     RECT  128.653 178.32 128.689 185.256 ;
     RECT  127.505 192.672 128.689 193.272 ;
     RECT  127.397 194.832 128.689 195 ;
     RECT  128.689 178.32 128.725 186.072 ;
     RECT  128.293 187.536 128.725 189.24 ;
     RECT  128.147 166.464 128.771 168.312 ;
     RECT  126.904 211.44 128.821 212.088 ;
     RECT  128.185 213.168 128.821 214.776 ;
     RECT  128.545 226.416 128.821 226.44 ;
     RECT  128.689 192.672 128.833 195 ;
     RECT  128.821 226.176 128.867 226.44 ;
     RECT  128.833 192.672 128.909 195.096 ;
     RECT  128.245 217.44 128.909 217.464 ;
     RECT  128.905 152.16 128.917 152.184 ;
     RECT  128.545 154.32 128.917 154.344 ;
     RECT  128.725 178.32 128.941 189.24 ;
     RECT  127.721 190.56 128.941 191.208 ;
     RECT  128.771 166.896 128.945 168.312 ;
     RECT  128.437 206.304 128.945 207.288 ;
     RECT  128.365 171.6 128.977 171.624 ;
     RECT  128.689 163.296 129.013 163.32 ;
     RECT  127.933 208.56 129.013 208.584 ;
     RECT  128.437 209.616 129.013 209.928 ;
     RECT  128.821 211.44 129.013 214.776 ;
     RECT  128.261 164.688 129.017 165.48 ;
     RECT  129.013 163.008 129.059 163.56 ;
     RECT  129.013 208.272 129.059 214.776 ;
     RECT  128.197 169.296 129.085 170.232 ;
     RECT  128.977 171.408 129.085 171.624 ;
     RECT  129.059 208.272 129.085 208.488 ;
     RECT  128.941 178.32 129.089 191.208 ;
     RECT  129.059 209.712 129.121 214.776 ;
     RECT  128.245 216.24 129.125 216.264 ;
     RECT  129.121 209.712 129.161 214.824 ;
     RECT  128.945 167.184 129.193 168.312 ;
     RECT  129.085 169.296 129.193 171.624 ;
     RECT  128.113 196.464 129.197 198.456 ;
     RECT  128.797 225.12 129.229 225.144 ;
     RECT  128.867 226.176 129.229 226.2 ;
     RECT  128.917 153.36 129.233 154.344 ;
     RECT  128.617 203.376 129.265 203.4 ;
     RECT  128.243 218.544 129.265 218.856 ;
     RECT  129.229 225.12 129.269 226.2 ;
     RECT  129.161 211.44 129.305 214.824 ;
     RECT  128.581 157.968 129.337 157.992 ;
     RECT  128.909 193.152 129.443 195.096 ;
     RECT  127.145 202.368 129.449 202.392 ;
     RECT  129.085 208.032 129.449 208.488 ;
     RECT  129.265 217.728 129.449 218.856 ;
     RECT  128.483 200.832 129.517 201.048 ;
     RECT  129.337 157.248 129.553 157.992 ;
     RECT  129.373 159.024 129.553 159.048 ;
     RECT  128.945 206.304 129.557 206.856 ;
     RECT  129.233 153.696 129.685 154.344 ;
     RECT  128.473 205.152 129.733 205.176 ;
     RECT  129.557 206.304 129.733 206.664 ;
     RECT  129.059 163.008 129.773 163.032 ;
     RECT  129.193 167.184 129.805 171.624 ;
     RECT  128.917 151.584 129.841 152.184 ;
     RECT  129.685 153.696 129.875 154.872 ;
     RECT  129.443 193.584 129.877 195.096 ;
     RECT  128.401 220.656 129.877 220.68 ;
     RECT  127.571 276.483 129.877 276.501 ;
     RECT  129.265 223.392 129.913 223.416 ;
     RECT  129.841 151.488 129.917 152.184 ;
     RECT  129.829 162.768 129.917 162.792 ;
     RECT  129.877 193.584 129.923 195.336 ;
     RECT  129.197 196.464 129.923 196.68 ;
     RECT  129.265 203.376 129.973 203.736 ;
     RECT  129.877 220.656 129.973 221.448 ;
     RECT  129.553 157.248 129.985 159.048 ;
     RECT  129.973 203.376 130.019 204.072 ;
     RECT  129.269 225.504 130.025 225.768 ;
     RECT  129.449 217.728 130.097 217.752 ;
     RECT  129.017 165.216 130.129 165.48 ;
     RECT  129.517 200.448 130.133 201.048 ;
     RECT  129.733 205.152 130.133 206.664 ;
     RECT  129.877 276.483 130.201 276.984 ;
     RECT  129.449 208.464 130.237 208.488 ;
     RECT  129.161 209.712 130.237 210.456 ;
     RECT  130.133 205.152 130.241 205.656 ;
     RECT  129.305 211.44 130.241 214.44 ;
     RECT  130.201 276.48 130.241 276.984 ;
     RECT  130.129 165.024 130.261 165.48 ;
     RECT  129.805 167.184 130.261 171.816 ;
     RECT  129.913 223.392 130.273 223.656 ;
     RECT  128.797 227.424 130.309 227.448 ;
     RECT  130.025 225.744 130.313 225.768 ;
     RECT  129.875 154.656 130.381 154.872 ;
     RECT  130.261 166.896 130.385 171.816 ;
     RECT  130.385 168.672 130.489 171.816 ;
     RECT  129.923 193.584 130.489 195.096 ;
     RECT  129.973 219.984 130.489 221.448 ;
     RECT  130.273 222.864 130.489 223.656 ;
     RECT  130.489 219.984 130.499 223.656 ;
     RECT  130.489 168.672 130.525 172.248 ;
     RECT  128.585 173.28 130.525 176.472 ;
     RECT  130.133 200.448 130.525 200.472 ;
     RECT  130.385 166.896 130.529 167.208 ;
     RECT  130.241 211.44 130.529 214.008 ;
     RECT  130.241 276.864 130.565 276.984 ;
     RECT  129.197 197.664 130.595 198.456 ;
     RECT  130.525 199.488 130.595 200.472 ;
     RECT  129.089 178.416 130.597 191.208 ;
     RECT  129.985 157.248 130.601 159.144 ;
     RECT  130.597 178.32 130.601 191.208 ;
     RECT  130.601 178.32 130.637 181.848 ;
     RECT  130.595 199.584 130.643 200.472 ;
     RECT  130.499 221.136 130.643 223.656 ;
     RECT  130.601 159.024 130.669 159.144 ;
     RECT  130.669 159.024 130.781 159.48 ;
     RECT  130.781 159.12 130.817 159.48 ;
     RECT  130.237 208.464 130.921 210.456 ;
     RECT  130.529 211.44 130.921 213.72 ;
     RECT  130.561 153.552 130.925 153.576 ;
     RECT  130.489 193.344 130.957 195.096 ;
     RECT  130.453 231.936 130.957 231.96 ;
     RECT  130.643 222.864 130.961 223.656 ;
     RECT  130.921 208.464 130.979 213.72 ;
     RECT  129.923 196.464 130.993 196.488 ;
     RECT  130.595 197.664 130.993 197.88 ;
     RECT  129.449 218.832 130.993 218.856 ;
     RECT  130.499 219.984 130.993 220.056 ;
     RECT  130.381 154.656 131.029 155.736 ;
     RECT  130.957 231.6 131.029 231.96 ;
     RECT  129.917 151.488 131.065 151.512 ;
     RECT  130.601 182.88 131.065 191.208 ;
     RECT  129.229 216.144 131.065 216.168 ;
     RECT  130.813 217.68 131.065 217.704 ;
     RECT  131.065 216.048 131.077 216.168 ;
     RECT  130.957 193.344 131.209 195.336 ;
     RECT  131.209 193.344 131.281 195.384 ;
     RECT  130.993 196.464 131.281 197.88 ;
     RECT  131.209 202.368 131.281 202.392 ;
     RECT  130.019 203.52 131.281 204.072 ;
     RECT  130.309 227.424 131.281 227.976 ;
     RECT  131.065 151.488 131.317 151.608 ;
     RECT  130.133 206.64 131.353 206.664 ;
     RECT  130.979 208.464 131.353 209.976 ;
     RECT  131.029 231.6 131.389 232.536 ;
     RECT  131.389 229.104 131.413 229.128 ;
     RECT  131.065 182.88 131.425 191.64 ;
     RECT  131.425 182.88 131.497 192.072 ;
     RECT  131.281 193.344 131.497 197.88 ;
     RECT  130.993 218.832 131.497 220.056 ;
     RECT  130.643 221.136 131.497 221.784 ;
     RECT  130.261 165.024 131.569 165.864 ;
     RECT  130.529 167.184 131.569 167.208 ;
     RECT  130.961 223.632 131.605 223.656 ;
     RECT  131.497 224.784 131.605 224.808 ;
     RECT  131.281 202.368 131.641 204.072 ;
     RECT  131.029 233.616 131.641 233.64 ;
     RECT  131.497 182.88 131.653 197.88 ;
     RECT  130.601 157.248 131.749 158.04 ;
     RECT  130.817 159.12 131.749 159.144 ;
     RECT  131.077 215.424 131.749 216.168 ;
     RECT  131.065 217.2 131.749 217.704 ;
     RECT  131.749 215.424 131.785 217.704 ;
     RECT  131.497 218.832 131.785 221.784 ;
     RECT  131.137 163.488 131.821 163.512 ;
     RECT  130.979 211.056 131.845 213.72 ;
     RECT  131.785 215.424 131.845 221.784 ;
     RECT  131.281 227.136 131.845 227.976 ;
     RECT  131.413 229.104 131.845 229.848 ;
     RECT  130.643 199.632 131.857 200.472 ;
     RECT  131.641 201.6 131.857 204.072 ;
     RECT  131.821 162.72 131.965 163.512 ;
     RECT  131.653 182.88 131.965 198.312 ;
     RECT  131.749 147.504 132.008 147.528 ;
     RECT  131.749 149.376 132.008 149.4 ;
     RECT  131.317 151.008 132.008 151.608 ;
     RECT  131.029 154.56 132.008 155.736 ;
     RECT  131.749 157.248 132.008 159.144 ;
     RECT  130.921 160.752 132.008 160.776 ;
     RECT  131.965 162.384 132.008 163.512 ;
     RECT  131.569 165.024 132.008 167.208 ;
     RECT  130.525 168.672 132.008 176.472 ;
     RECT  130.637 178.32 132.008 181.8 ;
     RECT  131.965 182.88 132.008 198.36 ;
     RECT  131.857 199.632 132.008 204.072 ;
     RECT  130.241 205.392 132.008 205.656 ;
     RECT  131.353 206.64 132.008 209.976 ;
     RECT  131.845 211.056 132.008 221.784 ;
     RECT  131.605 223.632 132.008 224.808 ;
     RECT  131.797 225.792 132.008 225.816 ;
     RECT  131.845 227.136 132.008 229.848 ;
     RECT  131.389 230.88 132.008 232.536 ;
     RECT  131.641 233.616 132.008 233.688 ;
     RECT  131.101 234.816 132.008 234.84 ;
     RECT  131.785 237.12 132.008 237.144 ;
     RECT  130.565 276.864 132.008 276.888 ;
     RECT  132.008 2.148 132.112 369.372 ;
     RECT  132.112 2.418 132.133 369.372 ;
     RECT  131.281 370.512 132.133 370.536 ;
     RECT  132.133 2.418 132.229 370.536 ;
     RECT  132.229 2.418 132.304 371.208 ;
     RECT  132.304 157.248 132.329 158.904 ;
     RECT  132.304 219.84 132.329 220.2 ;
     RECT  132.304 227.52 132.365 227.976 ;
     RECT  132.304 369.888 132.371 371.208 ;
     RECT  132.304 164.736 132.401 167.208 ;
     RECT  132.371 371.184 132.421 371.208 ;
     RECT  132.329 157.248 132.437 158.424 ;
     RECT  132.304 276.864 132.467 276.888 ;
     RECT  132.421 371.184 132.467 371.304 ;
     RECT  132.304 207.696 132.473 209.976 ;
     RECT  132.371 369.888 132.509 369.912 ;
     RECT  132.304 258.768 132.563 258.792 ;
     RECT  132.467 371.28 132.563 371.304 ;
     RECT  132.304 150.432 132.581 150.504 ;
     RECT  132.304 170.16 132.581 196.68 ;
     RECT  132.304 217.296 132.581 218.52 ;
     RECT  132.304 155.712 132.725 155.88 ;
     RECT  132.581 218.304 132.725 218.52 ;
     RECT  132.304 151.536 132.797 151.896 ;
     RECT  132.304 234.816 132.803 235.992 ;
     RECT  132.401 164.736 132.833 165.864 ;
     RECT  132.304 163.488 132.851 163.512 ;
     RECT  132.803 234.816 132.851 234.888 ;
     RECT  132.797 151.536 132.941 151.608 ;
     RECT  132.304 204.576 132.941 206.472 ;
     RECT  132.304 161.808 132.977 162.408 ;
     RECT  132.581 170.256 133.139 196.68 ;
     RECT  132.473 207.696 133.139 208.68 ;
     RECT  133.139 170.256 133.157 170.424 ;
     RECT  132.329 220.176 133.157 220.2 ;
     RECT  132.851 234.864 133.235 234.888 ;
     RECT  132.304 229.056 133.283 230.28 ;
     RECT  132.725 155.856 133.333 155.88 ;
     RECT  132.437 157.248 133.333 158.04 ;
     RECT  132.304 197.808 133.333 198.36 ;
     RECT  132.304 199.632 133.333 203.496 ;
     RECT  132.473 209.712 133.333 209.976 ;
     RECT  132.304 211.008 133.333 213.192 ;
     RECT  133.297 222.432 133.333 222.456 ;
     RECT  133.283 229.056 133.337 230.184 ;
     RECT  132.304 237.12 133.369 237.144 ;
     RECT  132.304 147.504 133.373 149.448 ;
     RECT  133.333 155.856 133.373 158.04 ;
     RECT  132.941 205.344 133.373 206.472 ;
     RECT  133.333 222.432 133.379 222.552 ;
     RECT  132.304 144.864 133.381 144.888 ;
     RECT  133.381 144 133.445 144.888 ;
     RECT  133.333 197.808 133.445 203.496 ;
     RECT  133.333 209.712 133.445 213.192 ;
     RECT  133.445 211.008 133.553 213.192 ;
     RECT  132.304 231.36 133.553 233.784 ;
     RECT  133.373 149.328 133.573 149.448 ;
     RECT  132.581 150.432 133.573 150.456 ;
     RECT  132.581 217.296 133.585 217.32 ;
     RECT  133.139 207.696 133.621 208.584 ;
     RECT  132.365 227.952 133.621 227.976 ;
     RECT  133.337 229.056 133.621 229.752 ;
     RECT  133.573 149.328 133.625 150.504 ;
     RECT  132.725 218.304 133.661 218.328 ;
     RECT  133.373 155.856 133.667 156.792 ;
     RECT  133.553 231.36 133.667 232.008 ;
     RECT  132.401 166.992 133.693 167.208 ;
     RECT  132.304 225.792 133.693 226.296 ;
     RECT  133.553 233.04 133.697 233.784 ;
     RECT  133.373 157.92 133.765 158.04 ;
     RECT  133.405 159.072 133.765 159.096 ;
     RECT  133.729 222.576 133.765 223.416 ;
     RECT  133.693 225.792 133.765 226.872 ;
     RECT  133.621 227.952 133.765 229.752 ;
     RECT  133.697 233.04 133.769 233.736 ;
     RECT  133.765 157.92 133.805 159.096 ;
     RECT  133.765 222.576 133.811 224.04 ;
     RECT  132.304 153.888 133.837 154.584 ;
     RECT  133.765 225.792 133.837 229.752 ;
     RECT  133.621 207.504 133.861 208.584 ;
     RECT  133.805 158.016 133.873 159.096 ;
     RECT  132.304 160.128 133.873 160.152 ;
     RECT  133.837 225.696 133.907 229.752 ;
     RECT  133.445 144.048 133.909 144.888 ;
     RECT  133.445 199.824 133.909 203.496 ;
     RECT  133.373 205.344 133.909 206.328 ;
     RECT  133.861 207.456 133.913 208.584 ;
     RECT  133.909 199.824 133.955 203.832 ;
     RECT  133.811 222.576 133.955 222.648 ;
     RECT  133.693 146.448 133.957 146.472 ;
     RECT  133.873 158.016 133.957 160.152 ;
     RECT  132.803 235.968 133.981 235.992 ;
     RECT  133.369 237.12 133.981 237.384 ;
     RECT  133.157 170.256 133.985 170.28 ;
     RECT  132.304 221.184 133.985 221.256 ;
     RECT  133.909 144.048 134.003 144.936 ;
     RECT  133.957 158.016 134.003 160.248 ;
     RECT  132.977 161.808 134.003 162.36 ;
     RECT  133.909 204.912 134.017 206.328 ;
     RECT  133.811 224.016 134.017 224.04 ;
     RECT  132.304 168.912 134.089 168.936 ;
     RECT  134.017 204.624 134.129 206.328 ;
     RECT  133.913 207.504 134.197 208.584 ;
     RECT  133.445 209.712 134.197 210.024 ;
     RECT  133.981 235.968 134.233 237.384 ;
     RECT  134.089 168.576 134.237 168.936 ;
     RECT  133.553 211.632 134.237 213.192 ;
     RECT  134.003 158.016 134.273 159.048 ;
     RECT  133.955 199.824 134.273 202.968 ;
     RECT  134.233 235.584 134.305 237.384 ;
     RECT  134.197 207.504 134.309 210.024 ;
     RECT  133.693 166.272 134.341 167.208 ;
     RECT  133.373 147.504 134.377 147.528 ;
     RECT  132.833 164.736 134.413 165.192 ;
     RECT  134.341 166.272 134.413 167.832 ;
     RECT  134.003 162.288 134.417 162.36 ;
     RECT  133.585 216.48 134.437 217.32 ;
     RECT  134.437 216.192 134.449 217.32 ;
     RECT  134.449 215.28 134.483 217.32 ;
     RECT  134.003 160.032 134.485 160.248 ;
     RECT  134.309 209.952 134.485 210.024 ;
     RECT  134.377 147.504 134.489 147.624 ;
     RECT  134.483 215.28 134.489 216.744 ;
     RECT  133.957 145.968 134.521 146.472 ;
     RECT  133.625 149.328 134.521 150.456 ;
     RECT  133.139 171.504 134.521 196.68 ;
     RECT  133.445 197.808 134.521 198.6 ;
     RECT  133.907 226.176 134.521 229.752 ;
     RECT  134.521 145.968 134.525 146.52 ;
     RECT  134.521 171.504 134.525 198.6 ;
     RECT  134.485 160.032 134.531 160.776 ;
     RECT  134.525 171.504 134.561 185.16 ;
     RECT  134.017 224.016 134.561 224.136 ;
     RECT  134.521 226.176 134.579 230.232 ;
     RECT  134.417 162.336 134.593 162.36 ;
     RECT  133.667 231.36 134.593 231.96 ;
     RECT  133.667 156.768 134.597 156.792 ;
     RECT  134.525 186.432 134.597 198.6 ;
     RECT  134.089 218.736 134.597 218.808 ;
     RECT  134.579 226.176 134.597 229.896 ;
     RECT  134.593 162.336 134.633 162.456 ;
     RECT  134.237 211.776 134.633 213.192 ;
     RECT  134.593 230.88 134.633 231.96 ;
     RECT  134.561 171.504 134.669 182.232 ;
     RECT  134.489 216.432 134.669 216.744 ;
     RECT  134.597 226.176 134.669 226.2 ;
     RECT  134.633 230.88 134.675 231.576 ;
     RECT  134.309 207.504 134.705 208.728 ;
     RECT  133.837 153.888 134.725 155.448 ;
     RECT  134.129 204.624 134.741 205.8 ;
     RECT  134.273 158.016 134.771 158.568 ;
     RECT  134.521 148.8 134.777 150.456 ;
     RECT  132.941 151.536 134.809 151.56 ;
     RECT  134.597 218.736 134.809 218.76 ;
     RECT  134.561 183.36 134.813 185.16 ;
     RECT  134.305 235.584 134.813 237.72 ;
     RECT  134.725 153.888 134.845 155.592 ;
     RECT  134.237 168.816 134.845 168.936 ;
     RECT  134.413 164.736 134.849 167.832 ;
     RECT  134.273 200.208 134.849 202.968 ;
     RECT  134.845 153.888 134.917 156.504 ;
     RECT  134.813 183.36 134.921 183.384 ;
     RECT  134.741 204.624 134.953 205.656 ;
     RECT  134.809 151.536 134.963 152.232 ;
     RECT  134.849 164.736 134.963 167.208 ;
     RECT  134.917 170.4 134.989 170.424 ;
     RECT  134.669 171.504 134.989 178.152 ;
     RECT  134.953 204 135.011 205.656 ;
     RECT  134.377 220.608 135.025 220.776 ;
     RECT  134.633 211.776 135.029 213.144 ;
     RECT  133.769 233.04 135.061 233.688 ;
     RECT  134.813 236.88 135.061 237.72 ;
     RECT  134.531 160.656 135.065 160.776 ;
     RECT  135.061 232.56 135.101 233.688 ;
     RECT  134.777 149.328 135.107 150.456 ;
     RECT  135.025 220.608 135.173 220.92 ;
     RECT  135.101 232.56 135.173 233.448 ;
     RECT  134.485 209.952 135.241 210.264 ;
     RECT  134.809 218.448 135.277 218.76 ;
     RECT  134.633 162.432 135.281 162.456 ;
     RECT  134.597 227.664 135.281 229.896 ;
     RECT  134.989 170.4 135.317 178.152 ;
     RECT  135.061 236.88 135.317 238.248 ;
     RECT  134.963 164.736 135.349 167.016 ;
     RECT  135.277 218.304 135.385 218.76 ;
     RECT  134.489 147.504 135.389 147.528 ;
     RECT  135.173 220.704 135.389 220.92 ;
     RECT  134.669 216.48 135.425 216.744 ;
     RECT  134.003 144.048 135.457 144.888 ;
     RECT  134.771 158.544 135.457 158.568 ;
     RECT  133.955 222.624 135.461 222.648 ;
     RECT  135.241 209.952 135.493 210.936 ;
     RECT  134.813 184.512 135.497 185.16 ;
     RECT  135.281 228 135.533 229.896 ;
     RECT  134.917 153.264 135.569 156.504 ;
     RECT  135.065 160.704 135.569 160.776 ;
     RECT  135.317 236.88 135.587 237.384 ;
     RECT  135.569 156.48 135.589 156.504 ;
     RECT  135.385 218.256 135.601 218.76 ;
     RECT  135.349 163.824 135.605 167.016 ;
     RECT  135.457 158.544 135.635 159.48 ;
     RECT  134.675 230.88 135.635 230.904 ;
     RECT  134.561 224.016 135.637 224.04 ;
     RECT  135.497 185.136 135.673 185.16 ;
     RECT  134.705 208.464 135.673 208.728 ;
     RECT  135.493 209.76 135.673 210.936 ;
     RECT  135.565 226.704 135.677 226.728 ;
     RECT  135.637 150.816 135.683 150.84 ;
     RECT  134.489 215.28 135.685 215.304 ;
     RECT  134.845 168.816 135.709 169.368 ;
     RECT  134.597 186.432 135.709 189.672 ;
     RECT  134.597 190.752 135.709 198.6 ;
     RECT  134.849 200.208 135.709 202.872 ;
     RECT  135.637 224.016 135.713 224.472 ;
     RECT  135.685 215.28 135.731 215.496 ;
     RECT  135.457 143.28 135.733 144.888 ;
     RECT  134.525 146.064 135.733 146.52 ;
     RECT  135.205 207.024 135.745 207.48 ;
     RECT  135.533 228.192 135.745 229.896 ;
     RECT  135.541 148.128 135.749 148.2 ;
     RECT  135.673 185.136 135.749 185.4 ;
     RECT  135.425 216.48 135.749 216.504 ;
     RECT  135.601 218.256 135.749 219.624 ;
     RECT  135.733 142.752 135.779 146.52 ;
     RECT  135.709 186.432 135.785 198.648 ;
     RECT  134.669 179.136 135.817 182.232 ;
     RECT  135.745 206.928 135.817 207.48 ;
     RECT  135.673 208.464 135.817 210.936 ;
     RECT  135.779 144 135.821 144.072 ;
     RECT  135.605 163.824 135.925 166.296 ;
     RECT  135.779 145.584 135.929 146.52 ;
     RECT  135.731 215.472 135.929 215.496 ;
     RECT  135.749 185.328 135.961 185.4 ;
     RECT  135.785 186.432 135.961 192.936 ;
     RECT  134.813 235.584 135.961 235.608 ;
     RECT  135.589 156.48 135.971 156.744 ;
     RECT  135.709 168.816 136.033 170.232 ;
     RECT  135.709 200.16 136.033 202.872 ;
     RECT  135.685 214.224 136.033 214.248 ;
     RECT  135.785 194.16 136.037 198.648 ;
     RECT  135.971 156.72 136.073 156.744 ;
     RECT  135.389 220.704 136.073 220.776 ;
     RECT  136.033 168.048 136.105 170.232 ;
     RECT  135.749 218.256 136.109 219.432 ;
     RECT  135.673 140.208 136.165 140.232 ;
     RECT  135.565 141.648 136.165 141.672 ;
     RECT  135.317 171.552 136.165 178.152 ;
     RECT  135.817 179.136 136.165 182.376 ;
     RECT  135.817 231.504 136.165 231.528 ;
     RECT  135.569 160.752 136.177 160.776 ;
     RECT  135.817 206.928 136.177 210.936 ;
     RECT  135.961 235.344 136.177 235.608 ;
     RECT  136.033 214.224 136.181 214.344 ;
     RECT  136.165 140.208 136.211 141.672 ;
     RECT  135.173 233.136 136.211 233.448 ;
     RECT  134.963 151.92 136.213 152.232 ;
     RECT  135.569 153.264 136.213 155.4 ;
     RECT  136.211 141.168 136.217 141.192 ;
     RECT  135.749 148.128 136.253 148.152 ;
     RECT  135.779 142.752 136.285 142.92 ;
     RECT  136.165 171.552 136.285 182.376 ;
     RECT  135.635 159.456 136.321 159.48 ;
     RECT  136.177 206.928 136.321 211.224 ;
     RECT  135.029 212.304 136.321 213.144 ;
     RECT  135.107 149.328 136.393 149.736 ;
     RECT  136.073 220.752 136.397 220.776 ;
     RECT  136.321 159.456 136.403 159.624 ;
     RECT  136.393 149.232 136.429 149.736 ;
     RECT  136.321 241.632 136.429 241.656 ;
     RECT  136.429 149.136 136.465 149.736 ;
     RECT  135.011 204.144 136.465 205.656 ;
     RECT  136.033 199.92 136.501 202.872 ;
     RECT  136.465 203.952 136.501 205.656 ;
     RECT  135.745 228.192 136.609 230.28 ;
     RECT  136.177 160.752 136.645 161.304 ;
     RECT  136.645 160.752 136.681 161.88 ;
     RECT  136.285 171.408 136.717 182.376 ;
     RECT  136.105 223.392 136.741 223.416 ;
     RECT  135.713 224.448 136.741 224.472 ;
     RECT  136.501 199.92 136.753 205.656 ;
     RECT  136.321 206.928 136.753 213.144 ;
     RECT  135.349 242.784 136.753 242.808 ;
     RECT  136.321 243.936 136.753 243.96 ;
     RECT  136.717 171.408 136.789 182.664 ;
     RECT  136.609 227.232 136.789 230.28 ;
     RECT  136.165 231.504 136.789 231.96 ;
     RECT  136.105 167.52 136.861 170.232 ;
     RECT  136.717 225.504 136.861 225.528 ;
     RECT  136.789 227.232 136.861 231.96 ;
     RECT  136.789 171.408 136.897 183.24 ;
     RECT  136.465 149.136 136.933 150.024 ;
     RECT  136.213 151.92 136.933 155.4 ;
     RECT  135.925 162.864 136.933 166.296 ;
     RECT  136.861 167.28 136.933 170.232 ;
     RECT  136.897 216.912 136.969 216.936 ;
     RECT  136.741 223.392 136.969 224.472 ;
     RECT  135.961 185.328 137.005 192.936 ;
     RECT  136.037 194.16 137.005 198.6 ;
     RECT  136.933 162.864 137.077 170.232 ;
     RECT  136.897 171.408 137.077 183.72 ;
     RECT  136.969 216.72 137.077 216.936 ;
     RECT  136.177 235.344 137.077 235.896 ;
     RECT  136.753 242.784 137.113 243.96 ;
     RECT  135.587 236.88 137.149 236.904 ;
     RECT  136.753 199.92 137.173 213.72 ;
     RECT  137.077 171.408 137.221 184.296 ;
     RECT  137.005 185.328 137.221 198.6 ;
     RECT  137.149 236.88 137.269 237 ;
     RECT  137.077 216.432 137.329 216.936 ;
     RECT  136.109 218.304 137.329 219.432 ;
     RECT  136.861 225.504 137.365 231.96 ;
     RECT  136.211 233.424 137.365 233.448 ;
     RECT  136.285 142.56 137.401 142.92 ;
     RECT  136.933 148.8 137.401 150.024 ;
     RECT  136.933 151.92 137.401 155.928 ;
     RECT  137.005 133.296 137.408 133.32 ;
     RECT  137.365 135.36 137.408 135.384 ;
     RECT  137.005 137.328 137.408 137.352 ;
     RECT  137.401 142.176 137.408 142.92 ;
     RECT  135.821 144.048 137.408 144.072 ;
     RECT  135.929 145.584 137.408 145.608 ;
     RECT  136.753 147.216 137.408 147.24 ;
     RECT  137.401 148.8 137.408 155.928 ;
     RECT  136.357 157.872 137.408 157.896 ;
     RECT  137.221 158.88 137.408 158.904 ;
     RECT  136.681 160.56 137.408 161.88 ;
     RECT  137.077 162.864 137.408 170.28 ;
     RECT  137.221 171.408 137.408 198.6 ;
     RECT  137.173 199.92 137.408 214.008 ;
     RECT  136.981 214.992 137.408 215.016 ;
     RECT  137.329 216.432 137.408 219.432 ;
     RECT  136.537 220.992 137.408 221.016 ;
     RECT  136.969 222.576 137.408 224.472 ;
     RECT  137.365 225.504 137.408 233.448 ;
     RECT  137.077 234.72 137.408 235.896 ;
     RECT  137.269 236.88 137.408 237.144 ;
     RECT  136.501 238.8 137.408 238.824 ;
     RECT  136.429 240.912 137.408 241.656 ;
     RECT  137.113 242.784 137.408 244.584 ;
     RECT  137.408 2.148 137.512 369.372 ;
     RECT  137.512 2.418 137.704 369.102 ;
     RECT  137.704 154.32 137.765 155.928 ;
     RECT  137.704 237.12 137.765 237.144 ;
     RECT  137.704 157.344 137.837 160.776 ;
     RECT  137.704 134.64 137.843 137.352 ;
     RECT  137.704 140.784 137.843 142.92 ;
     RECT  137.704 146.688 137.843 146.712 ;
     RECT  137.704 149.184 137.843 151.032 ;
     RECT  137.837 160.032 137.843 160.776 ;
     RECT  137.704 161.808 137.891 219.432 ;
     RECT  137.704 152.112 137.909 153.288 ;
     RECT  137.891 161.808 137.909 218.712 ;
     RECT  137.704 233.424 137.909 235.896 ;
     RECT  137.704 242.256 137.909 243.96 ;
     RECT  137.909 161.808 137.939 218.568 ;
     RECT  137.704 220.56 137.939 221.208 ;
     RECT  137.843 140.784 137.945 141.336 ;
     RECT  137.843 149.232 137.945 150.024 ;
     RECT  137.909 233.424 137.945 235.8 ;
     RECT  137.939 216.384 137.981 218.568 ;
     RECT  137.704 223.968 137.987 228.6 ;
     RECT  137.981 216.384 138.017 218.376 ;
     RECT  137.704 239.712 138.053 240.936 ;
     RECT  137.987 226.32 138.089 228.6 ;
     RECT  137.909 152.112 138.233 153.24 ;
     RECT  137.987 223.968 138.305 225.144 ;
     RECT  137.837 157.344 138.419 159 ;
     RECT  138.419 157.344 138.515 157.368 ;
     RECT  137.765 154.32 138.521 155.688 ;
     RECT  137.939 161.808 138.557 215.304 ;
     RECT  138.557 168.048 138.629 215.304 ;
     RECT  137.843 137.232 138.665 137.352 ;
     RECT  137.704 222.576 138.697 222.888 ;
     RECT  138.305 223.968 138.697 223.992 ;
     RECT  138.665 137.232 138.707 137.256 ;
     RECT  137.704 133.296 138.733 133.32 ;
     RECT  137.704 138.576 138.733 138.6 ;
     RECT  138.089 226.32 138.737 226.92 ;
     RECT  137.704 147.984 138.773 148.104 ;
     RECT  137.704 230.016 138.773 230.04 ;
     RECT  138.419 158.496 138.841 159 ;
     RECT  138.089 228.192 138.845 228.6 ;
     RECT  137.945 234.816 138.851 235.8 ;
     RECT  137.843 134.64 138.913 136.2 ;
     RECT  138.697 222.576 138.913 223.992 ;
     RECT  137.909 242.256 138.913 242.424 ;
     RECT  137.909 243.456 138.913 243.96 ;
     RECT  137.945 149.232 138.917 149.976 ;
     RECT  138.557 161.808 138.947 167.016 ;
     RECT  137.704 144.768 138.949 144.792 ;
     RECT  138.913 242.256 138.949 243.96 ;
     RECT  138.913 222.144 138.953 223.992 ;
     RECT  138.913 134.4 138.985 136.2 ;
     RECT  137.704 231.072 138.985 232.056 ;
     RECT  137.945 140.784 138.989 140.808 ;
     RECT  138.521 154.32 138.989 154.344 ;
     RECT  138.947 161.808 138.995 166.776 ;
     RECT  138.949 242.256 138.995 244.008 ;
     RECT  138.233 152.112 139.021 153.192 ;
     RECT  138.769 156.672 139.025 156.696 ;
     RECT  138.995 243.408 139.025 244.008 ;
     RECT  138.017 216.432 139.057 218.376 ;
     RECT  137.704 238.176 139.057 238.248 ;
     RECT  138.841 158.496 139.093 159.528 ;
     RECT  137.843 160.656 139.093 160.776 ;
     RECT  139.057 216.432 139.093 219 ;
     RECT  138.053 240.912 139.129 240.936 ;
     RECT  138.995 242.256 139.129 242.424 ;
     RECT  139.093 158.496 139.133 160.776 ;
     RECT  138.629 168.384 139.133 215.016 ;
     RECT  139.133 158.496 139.139 160.2 ;
     RECT  139.129 240.912 139.139 242.424 ;
     RECT  138.053 239.712 139.141 239.736 ;
     RECT  139.139 240.912 139.141 242.328 ;
     RECT  138.949 144.288 139.169 144.792 ;
     RECT  138.521 155.664 139.169 155.688 ;
     RECT  138.985 134.304 139.205 136.2 ;
     RECT  137.945 233.424 139.237 233.688 ;
     RECT  139.093 216.432 139.273 219.96 ;
     RECT  138.773 148.08 139.309 148.104 ;
     RECT  138.917 149.232 139.309 149.256 ;
     RECT  139.273 216.096 139.309 220.2 ;
     RECT  138.737 226.56 139.349 226.92 ;
     RECT  138.953 222.144 139.381 223.416 ;
     RECT  139.349 226.56 139.385 226.584 ;
     RECT  139.139 158.496 139.421 159.528 ;
     RECT  139.057 237.648 139.453 238.248 ;
     RECT  139.453 237.648 139.477 238.488 ;
     RECT  139.141 239.712 139.477 242.328 ;
     RECT  139.237 233.424 139.489 233.784 ;
     RECT  138.733 133.152 139.525 133.32 ;
     RECT  139.205 134.304 139.525 135.624 ;
     RECT  139.477 237.648 139.525 242.328 ;
     RECT  139.525 133.152 139.529 135.624 ;
     RECT  138.733 138.48 139.561 138.6 ;
     RECT  139.525 237.264 139.565 242.328 ;
     RECT  139.025 243.408 139.565 243.72 ;
     RECT  139.565 237.264 139.571 238.488 ;
     RECT  138.995 161.808 139.597 163.176 ;
     RECT  139.381 221.52 139.601 223.416 ;
     RECT  139.309 216.096 139.633 220.296 ;
     RECT  139.421 158.544 139.637 159.528 ;
     RECT  139.489 233.424 139.669 234.216 ;
     RECT  139.489 154.416 139.673 154.44 ;
     RECT  139.601 222.144 139.673 223.416 ;
     RECT  139.565 239.52 139.673 242.328 ;
     RECT  139.133 168.384 139.705 211.272 ;
     RECT  139.597 161.28 139.715 163.176 ;
     RECT  139.633 224.4 139.715 224.424 ;
     RECT  139.669 233.376 139.745 234.216 ;
     RECT  139.745 233.376 139.781 234.12 ;
     RECT  139.571 237.264 139.781 238.248 ;
     RECT  139.633 216.096 139.817 220.632 ;
     RECT  139.529 134.112 139.853 135.624 ;
     RECT  138.733 246.144 139.957 246.168 ;
     RECT  138.995 164.4 139.993 166.776 ;
     RECT  139.705 168.288 139.993 211.272 ;
     RECT  139.993 164.4 140.005 211.272 ;
     RECT  139.309 146.4 140.065 146.424 ;
     RECT  139.561 138.48 140.101 139.128 ;
     RECT  137.843 142.656 140.101 142.92 ;
     RECT  138.985 230.4 140.137 232.056 ;
     RECT  139.781 233.376 140.137 233.4 ;
     RECT  139.957 246.144 140.137 246.792 ;
     RECT  139.673 239.52 140.141 239.544 ;
     RECT  139.565 243.696 140.141 243.72 ;
     RECT  140.065 145.536 140.147 146.424 ;
     RECT  139.853 134.112 140.213 134.52 ;
     RECT  140.137 230.4 140.245 233.4 ;
     RECT  139.021 151.344 140.249 153.192 ;
     RECT  139.715 161.28 140.285 162.408 ;
     RECT  140.065 132.96 140.317 132.984 ;
     RECT  139.853 135.6 140.317 135.624 ;
     RECT  139.309 148.08 140.353 149.256 ;
     RECT  138.851 235.776 140.389 235.8 ;
     RECT  139.781 237.264 140.389 238.056 ;
     RECT  140.353 148.08 140.425 149.4 ;
     RECT  140.425 147.792 140.483 149.4 ;
     RECT  139.817 216.096 140.485 220.296 ;
     RECT  138.845 228.192 140.533 228.216 ;
     RECT  140.245 229.488 140.533 233.4 ;
     RECT  140.101 138.48 140.629 139.656 ;
     RECT  140.437 146.448 140.645 146.472 ;
     RECT  140.629 137.904 140.675 139.656 ;
     RECT  140.533 224.544 140.677 224.568 ;
     RECT  140.389 225.84 140.677 225.864 ;
     RECT  139.777 249.648 140.677 249.672 ;
     RECT  140.005 163.584 140.713 211.272 ;
     RECT  140.677 224.544 140.713 225.864 ;
     RECT  140.461 244.176 140.713 244.2 ;
     RECT  140.137 245.472 140.713 246.792 ;
     RECT  140.675 137.904 140.717 137.928 ;
     RECT  140.533 228.192 140.723 233.4 ;
     RECT  140.317 160.032 140.725 160.056 ;
     RECT  140.569 161.088 140.725 161.112 ;
     RECT  140.713 163.584 140.725 211.368 ;
     RECT  139.133 212.4 140.725 215.016 ;
     RECT  140.725 163.584 140.749 215.016 ;
     RECT  140.485 216.048 140.749 220.296 ;
     RECT  140.725 160.032 140.771 161.112 ;
     RECT  139.561 141.552 140.773 141.576 ;
     RECT  140.101 142.608 140.773 142.92 ;
     RECT  140.483 148.752 140.773 149.4 ;
     RECT  140.281 150.432 140.773 150.792 ;
     RECT  139.673 240.912 140.773 242.328 ;
     RECT  140.749 163.584 140.785 220.296 ;
     RECT  140.785 163.584 140.789 220.44 ;
     RECT  140.773 141.312 140.819 141.576 ;
     RECT  140.773 240 140.825 242.808 ;
     RECT  140.773 142.608 140.857 143.256 ;
     RECT  139.169 144.288 140.857 144.312 ;
     RECT  140.771 160.032 140.857 160.536 ;
     RECT  140.789 191.568 140.867 220.44 ;
     RECT  140.867 219.552 140.893 220.44 ;
     RECT  140.677 247.968 140.929 247.992 ;
     RECT  140.867 191.568 140.933 218.568 ;
     RECT  140.389 235.776 140.933 238.056 ;
     RECT  140.723 228.192 140.965 229.704 ;
     RECT  140.789 163.584 140.969 190.536 ;
     RECT  140.713 244.176 141.001 246.792 ;
     RECT  140.933 217.92 141.005 218.568 ;
     RECT  140.825 240 141.005 242.28 ;
     RECT  140.317 132.768 141.073 132.984 ;
     RECT  140.213 134.112 141.073 134.136 ;
     RECT  140.675 139.632 141.073 139.656 ;
     RECT  140.857 142.608 141.073 144.312 ;
     RECT  140.821 154.224 141.073 154.248 ;
     RECT  139.237 156.24 141.073 156.264 ;
     RECT  140.249 152.112 141.077 153.192 ;
     RECT  141.073 132.768 141.109 134.136 ;
     RECT  140.969 163.584 141.113 168.024 ;
     RECT  141.073 142.608 141.145 144.792 ;
     RECT  141.109 132.192 141.155 134.136 ;
     RECT  141.005 240 141.155 241.704 ;
     RECT  141.155 132.192 141.185 132.792 ;
     RECT  141.077 152.4 141.185 153.192 ;
     RECT  141.001 244.176 141.217 246.84 ;
     RECT  140.929 247.824 141.217 247.992 ;
     RECT  140.933 191.568 141.221 216.936 ;
     RECT  140.723 230.784 141.221 233.4 ;
     RECT  141.073 156.24 141.253 156.888 ;
     RECT  139.637 158.544 141.253 158.664 ;
     RECT  140.857 159.696 141.253 160.536 ;
     RECT  140.773 148.752 141.257 150.792 ;
     RECT  141.073 154.224 141.257 154.44 ;
     RECT  140.713 224.544 141.293 226.344 ;
     RECT  141.253 156.24 141.299 157.368 ;
     RECT  141.299 156.768 141.329 157.368 ;
     RECT  140.285 162.192 141.329 162.408 ;
     RECT  141.221 233.088 141.329 233.4 ;
     RECT  141.217 244.176 141.347 247.992 ;
     RECT  141.185 132.768 141.365 132.792 ;
     RECT  140.317 135.6 141.437 136.296 ;
     RECT  140.933 236.496 141.437 238.056 ;
     RECT  141.073 139.632 141.473 140.232 ;
     RECT  141.145 142.512 141.505 144.792 ;
     RECT  139.673 222.192 141.505 223.416 ;
     RECT  141.221 210.384 141.509 216.936 ;
     RECT  141.469 235.152 141.539 235.176 ;
     RECT  141.493 224.4 141.545 224.424 ;
     RECT  141.155 134.016 141.577 134.136 ;
     RECT  141.293 225.408 141.577 226.344 ;
     RECT  140.965 227.52 141.577 229.704 ;
     RECT  141.577 134.016 141.635 134.568 ;
     RECT  141.253 158.544 141.689 160.536 ;
     RECT  141.469 162.432 141.689 162.456 ;
     RECT  141.155 240 141.793 241.272 ;
     RECT  140.893 219.552 141.829 220.536 ;
     RECT  141.505 221.76 141.829 223.416 ;
     RECT  141.221 191.568 141.865 209.208 ;
     RECT  141.505 142.512 141.901 144.936 ;
     RECT  141.509 214.992 141.901 216.936 ;
     RECT  141.073 146.544 141.925 146.568 ;
     RECT  141.793 239.904 142.009 241.272 ;
     RECT  141.257 150.432 142.045 150.792 ;
     RECT  140.969 169.056 142.081 190.536 ;
     RECT  141.865 191.52 142.081 209.208 ;
     RECT  140.819 141.312 142.165 141.336 ;
     RECT  141.689 159.552 142.165 160.536 ;
     RECT  141.437 237.744 142.165 238.056 ;
     RECT  141.185 152.688 142.213 153.192 ;
     RECT  141.257 154.224 142.213 154.248 ;
     RECT  141.257 148.752 142.261 149.4 ;
     RECT  142.165 159.552 142.261 161.016 ;
     RECT  141.113 163.584 142.261 166.44 ;
     RECT  141.113 167.472 142.261 168.024 ;
     RECT  141.347 244.176 142.261 245.496 ;
     RECT  142.009 239.808 142.333 241.272 ;
     RECT  142.213 152.688 142.369 154.248 ;
     RECT  141.005 218.256 142.405 218.568 ;
     RECT  141.829 219.552 142.405 223.416 ;
     RECT  141.329 233.376 142.405 233.4 ;
     RECT  142.165 237.744 142.405 238.776 ;
     RECT  142.333 239.808 142.405 241.8 ;
     RECT  142.405 218.256 142.441 223.416 ;
     RECT  141.473 139.728 142.453 139.752 ;
     RECT  141.901 142.512 142.453 145.368 ;
     RECT  141.925 146.448 142.453 146.568 ;
     RECT  141.689 158.544 142.477 158.568 ;
     RECT  142.261 243.36 142.477 245.496 ;
     RECT  141.347 246.528 142.477 247.368 ;
     RECT  141.829 147.648 142.501 147.672 ;
     RECT  142.261 148.656 142.501 149.4 ;
     RECT  142.081 169.056 142.501 209.208 ;
     RECT  141.509 210.384 142.501 213.72 ;
     RECT  142.045 150.432 142.513 151.032 ;
     RECT  142.261 163.584 142.513 168.024 ;
     RECT  142.369 152.64 142.549 154.248 ;
     RECT  142.369 155.616 142.549 155.64 ;
     RECT  141.901 214.992 142.549 217.272 ;
     RECT  142.441 218.256 142.549 224.136 ;
     RECT  141.221 230.784 142.549 231.816 ;
     RECT  141.329 156.768 142.585 156.888 ;
     RECT  141.577 225.408 142.585 229.704 ;
     RECT  142.549 230.784 142.585 232.056 ;
     RECT  142.453 142.512 142.597 146.568 ;
     RECT  142.405 237.744 142.597 241.8 ;
     RECT  142.585 225.408 142.729 232.056 ;
     RECT  142.513 162.72 142.765 168.024 ;
     RECT  141.635 134.016 142.808 134.28 ;
     RECT  141.437 135.6 142.808 135.624 ;
     RECT  142.453 138.96 142.808 139.752 ;
     RECT  142.165 141.024 142.808 141.336 ;
     RECT  142.597 142.416 142.808 146.568 ;
     RECT  142.501 147.648 142.808 149.4 ;
     RECT  142.513 150.432 142.808 151.608 ;
     RECT  142.549 152.64 142.808 155.64 ;
     RECT  142.585 156.768 142.808 156.984 ;
     RECT  142.477 158.448 142.808 158.568 ;
     RECT  142.261 159.552 142.808 161.112 ;
     RECT  142.765 162.624 142.808 168.024 ;
     RECT  142.501 169.056 142.808 213.72 ;
     RECT  142.549 214.992 142.808 224.136 ;
     RECT  142.729 225.408 142.808 232.104 ;
     RECT  142.405 233.184 142.808 233.4 ;
     RECT  141.437 236.496 142.808 236.52 ;
     RECT  142.597 237.744 142.808 242.28 ;
     RECT  142.477 243.36 142.808 247.368 ;
     RECT  140.677 249.6 142.808 249.672 ;
     RECT  142.808 2.148 142.912 369.372 ;
     RECT  142.912 2.418 143.104 369.102 ;
     RECT  143.104 249.12 143.165 249.672 ;
     RECT  143.104 132.192 143.219 136.968 ;
     RECT  143.104 156.048 143.219 206.904 ;
     RECT  143.104 211.008 143.237 213.768 ;
     RECT  143.104 144.816 143.267 154.872 ;
     RECT  143.104 223.728 143.309 234.312 ;
     RECT  143.267 145.632 143.315 154.296 ;
     RECT  143.309 225.888 143.315 234.312 ;
     RECT  143.219 132.192 143.345 135.384 ;
     RECT  143.104 241.152 143.381 243.72 ;
     RECT  143.219 156.048 143.411 159.384 ;
     RECT  143.315 225.888 143.417 230.328 ;
     RECT  143.411 156.48 143.459 159.384 ;
     RECT  143.219 162.384 143.459 206.904 ;
     RECT  143.315 231.312 143.489 234.312 ;
     RECT  143.489 233.952 143.525 234.312 ;
     RECT  143.219 136.416 143.561 136.968 ;
     RECT  143.104 140.784 143.597 143.304 ;
     RECT  143.315 145.632 143.651 149.4 ;
     RECT  143.597 140.784 143.741 141.816 ;
     RECT  143.651 145.632 143.777 146.472 ;
     RECT  143.219 160.992 143.777 161.016 ;
     RECT  143.104 208.08 143.795 209.592 ;
     RECT  143.459 191.76 143.813 206.904 ;
     RECT  143.795 208.608 143.813 209.592 ;
     RECT  143.104 214.896 143.813 222.264 ;
     RECT  143.813 191.76 143.849 201.624 ;
     RECT  143.381 242.64 143.987 243.72 ;
     RECT  143.315 150.48 144.029 154.296 ;
     RECT  144.029 150.816 144.035 153.192 ;
     RECT  143.104 237.216 144.035 240.024 ;
     RECT  143.237 213.696 144.065 213.768 ;
     RECT  143.417 228.336 144.065 230.328 ;
     RECT  144.035 237.216 144.065 238.776 ;
     RECT  143.165 249.12 144.101 249.624 ;
     RECT  143.104 138.96 144.137 138.984 ;
     RECT  143.813 215.04 144.169 222.264 ;
     RECT  143.309 223.728 144.169 224.28 ;
     RECT  143.381 241.152 144.169 241.272 ;
     RECT  143.345 132.192 144.173 133.368 ;
     RECT  143.777 146.448 144.173 146.472 ;
     RECT  143.597 143.136 144.205 143.304 ;
     RECT  144.169 241.104 144.209 241.272 ;
     RECT  144.205 143.136 144.241 143.64 ;
     RECT  144.065 230.208 144.245 230.328 ;
     RECT  143.489 231.312 144.275 232.968 ;
     RECT  144.029 154.272 144.277 154.296 ;
     RECT  144.035 151.056 144.317 152.136 ;
     RECT  143.741 140.784 144.323 141.336 ;
     RECT  144.065 213.744 144.323 213.768 ;
     RECT  143.561 136.752 144.353 136.968 ;
     RECT  143.104 244.704 144.353 247.08 ;
     RECT  143.345 135.216 144.385 135.384 ;
     RECT  144.275 231.408 144.389 232.968 ;
     RECT  144.065 228.336 144.425 229.176 ;
     RECT  144.065 237.216 144.425 237.288 ;
     RECT  144.169 215.04 144.457 224.28 ;
     RECT  143.651 148.176 144.461 149.4 ;
     RECT  144.035 239.904 144.461 239.928 ;
     RECT  144.209 241.104 144.461 241.128 ;
     RECT  143.459 156.768 144.493 159.384 ;
     RECT  143.813 202.656 144.493 206.904 ;
     RECT  143.104 236.16 144.493 236.184 ;
     RECT  144.425 237.216 144.493 237.24 ;
     RECT  144.421 155.568 144.533 155.592 ;
     RECT  143.459 162.384 144.533 190.776 ;
     RECT  144.493 156.768 144.563 159.624 ;
     RECT  143.417 225.888 144.565 226.872 ;
     RECT  144.425 228.336 144.565 228.648 ;
     RECT  143.987 242.64 144.601 242.664 ;
     RECT  144.389 231.408 144.605 232.68 ;
     RECT  144.605 231.408 144.611 231.432 ;
     RECT  144.461 148.224 144.641 149.4 ;
     RECT  144.457 215.04 144.641 224.664 ;
     RECT  143.987 243.696 144.641 243.72 ;
     RECT  144.533 163.008 144.677 190.776 ;
     RECT  144.563 159.312 144.713 159.384 ;
     RECT  144.565 225.888 144.713 228.648 ;
     RECT  144.353 136.944 144.745 136.968 ;
     RECT  143.813 209.136 144.745 209.592 ;
     RECT  143.237 211.008 144.745 212.616 ;
     RECT  143.525 233.952 144.781 233.976 ;
     RECT  144.641 215.04 144.805 217.704 ;
     RECT  143.849 191.76 144.817 201.576 ;
     RECT  144.493 202.656 144.817 207.144 ;
     RECT  144.641 218.88 144.821 224.664 ;
     RECT  144.805 214.848 144.851 217.704 ;
     RECT  144.851 216.096 144.857 217.704 ;
     RECT  144.821 218.88 144.857 219.432 ;
     RECT  144.821 220.416 144.857 224.664 ;
     RECT  144.601 144.768 144.889 145.32 ;
     RECT  144.851 214.848 144.893 214.872 ;
     RECT  144.323 140.784 144.929 140.808 ;
     RECT  144.889 144.768 144.929 145.896 ;
     RECT  144.677 164.112 144.929 190.776 ;
     RECT  144.757 247.968 144.929 247.992 ;
     RECT  144.173 133.344 144.949 133.368 ;
     RECT  144.385 135.216 144.949 135.72 ;
     RECT  144.563 156.768 144.949 157.032 ;
     RECT  144.241 143.136 144.961 143.736 ;
     RECT  144.857 223.968 144.961 224.664 ;
     RECT  144.713 225.888 144.961 225.912 ;
     RECT  144.929 165.264 144.965 190.776 ;
     RECT  144.245 230.208 144.965 230.232 ;
     RECT  144.949 156.624 144.995 157.032 ;
     RECT  144.317 151.392 144.997 152.136 ;
     RECT  144.035 153.168 144.997 153.192 ;
     RECT  144.277 154.272 144.997 154.536 ;
     RECT  144.949 133.344 145.001 135.72 ;
     RECT  144.857 216.096 145.001 217.176 ;
     RECT  144.995 156.624 145.037 156.84 ;
     RECT  144.961 142.656 145.069 143.736 ;
     RECT  144.929 144.768 145.069 144.792 ;
     RECT  144.965 182.64 145.091 190.776 ;
     RECT  145.069 142.656 145.105 144.792 ;
     RECT  145.105 142.512 145.109 144.792 ;
     RECT  144.961 235.104 145.109 235.128 ;
     RECT  144.745 209.136 145.141 212.616 ;
     RECT  145.109 142.512 145.177 144.312 ;
     RECT  144.857 220.416 145.217 222.792 ;
     RECT  145.001 134.784 145.253 135.72 ;
     RECT  145.189 138.528 145.253 138.552 ;
     RECT  145.091 182.64 145.283 187.512 ;
     RECT  145.283 182.64 145.331 187.416 ;
     RECT  144.781 233.664 145.333 233.976 ;
     RECT  144.997 151.392 145.357 154.536 ;
     RECT  145.253 134.784 145.379 135.096 ;
     RECT  145.331 182.784 145.379 187.416 ;
     RECT  145.333 233.664 145.379 234.264 ;
     RECT  144.173 132.192 145.381 132.216 ;
     RECT  145.001 133.344 145.381 133.752 ;
     RECT  144.713 226.992 145.397 228.648 ;
     RECT  145.381 132.192 145.427 133.752 ;
     RECT  144.853 213.792 145.429 213.816 ;
     RECT  145.427 133.152 145.433 133.752 ;
     RECT  144.493 236.16 145.465 237.24 ;
     RECT  144.065 238.752 145.465 238.776 ;
     RECT  144.677 163.008 145.469 163.032 ;
     RECT  145.379 182.784 145.469 187.176 ;
     RECT  145.433 133.344 145.505 133.368 ;
     RECT  145.141 208.896 145.523 212.616 ;
     RECT  144.563 158.304 145.525 158.328 ;
     RECT  145.091 188.592 145.537 190.776 ;
     RECT  144.817 191.76 145.537 207.144 ;
     RECT  145.523 210.288 145.541 212.616 ;
     RECT  144.353 244.704 145.541 246.936 ;
     RECT  145.465 236.16 145.573 238.776 ;
     RECT  144.745 136.944 145.609 137.4 ;
     RECT  144.745 161.856 145.609 161.88 ;
     RECT  144.605 232.656 145.609 232.68 ;
     RECT  145.357 150.912 145.649 154.536 ;
     RECT  145.217 222.24 145.649 222.792 ;
     RECT  144.961 223.968 145.667 225.912 ;
     RECT  145.397 226.992 145.667 227.976 ;
     RECT  145.667 224.976 145.685 225.912 ;
     RECT  145.649 151.488 145.717 154.536 ;
     RECT  145.541 244.704 145.717 246.36 ;
     RECT  144.101 249.12 145.721 249.144 ;
     RECT  144.641 148.704 145.753 149.4 ;
     RECT  145.667 227.136 145.757 227.976 ;
     RECT  145.717 243.84 145.763 246.36 ;
     RECT  144.713 159.312 145.789 159.336 ;
     RECT  145.681 160.656 145.789 160.68 ;
     RECT  145.667 223.968 145.793 223.992 ;
     RECT  145.357 147.024 145.825 147.048 ;
     RECT  145.753 148.56 145.825 149.4 ;
     RECT  145.789 140.112 145.859 140.136 ;
     RECT  145.177 141.792 145.859 144.312 ;
     RECT  145.525 157.872 145.861 158.328 ;
     RECT  145.789 159.312 145.861 160.68 ;
     RECT  145.609 161.808 145.861 161.88 ;
     RECT  145.537 188.592 145.861 207.144 ;
     RECT  145.523 208.896 145.861 209.16 ;
     RECT  145.573 236.112 145.861 238.776 ;
     RECT  145.469 182.784 145.865 187.128 ;
     RECT  145.717 151.488 145.907 154.68 ;
     RECT  145.825 147.024 145.909 149.4 ;
     RECT  145.907 151.488 145.937 154.44 ;
     RECT  145.865 183.264 145.937 187.128 ;
     RECT  145.685 225.312 145.969 225.912 ;
     RECT  145.763 244.704 145.973 246.36 ;
     RECT  145.861 157.872 146.041 161.88 ;
     RECT  145.861 235.584 146.041 238.776 ;
     RECT  145.859 142.176 146.045 144.312 ;
     RECT  144.929 145.872 146.077 145.896 ;
     RECT  144.601 242.592 146.081 242.664 ;
     RECT  145.037 156.768 146.113 156.84 ;
     RECT  146.041 157.872 146.113 161.928 ;
     RECT  146.077 145.632 146.117 145.896 ;
     RECT  144.857 218.88 146.149 219.384 ;
     RECT  145.379 233.952 146.189 234.264 ;
     RECT  146.041 235.584 146.189 239.544 ;
     RECT  145.429 213.792 146.225 214.248 ;
     RECT  145.609 229.296 146.225 229.416 ;
     RECT  145.861 188.592 146.257 209.16 ;
     RECT  146.225 229.392 146.257 229.416 ;
     RECT  145.937 151.488 146.261 154.296 ;
     RECT  146.149 218.832 146.293 219.384 ;
     RECT  146.257 188.496 146.297 209.16 ;
     RECT  145.217 220.416 146.297 221.16 ;
     RECT  145.717 155.76 146.329 155.784 ;
     RECT  145.609 136.608 146.365 137.4 ;
     RECT  145.969 225.312 146.369 226.152 ;
     RECT  146.257 229.392 146.369 230.28 ;
     RECT  146.261 151.824 146.387 154.296 ;
     RECT  145.609 232.608 146.401 232.68 ;
     RECT  145.379 134.784 146.405 134.808 ;
     RECT  146.297 188.496 146.405 193.944 ;
     RECT  145.825 240.96 146.405 240.984 ;
     RECT  146.297 194.928 146.435 209.16 ;
     RECT  145.541 210.336 146.437 212.616 ;
     RECT  146.297 220.464 146.437 221.16 ;
     RECT  145.649 222.24 146.437 222.408 ;
     RECT  146.189 234.192 146.441 234.264 ;
     RECT  146.437 220.464 146.477 222.408 ;
     RECT  145.937 183.552 146.513 187.128 ;
     RECT  146.435 201.168 146.513 209.16 ;
     RECT  146.189 236.496 146.513 239.544 ;
     RECT  146.329 155.664 146.533 155.784 ;
     RECT  146.113 156.768 146.533 161.928 ;
     RECT  146.365 136.176 146.549 137.4 ;
     RECT  146.533 155.664 146.549 161.928 ;
     RECT  145.973 244.704 146.549 245.64 ;
     RECT  146.549 155.664 146.579 160.728 ;
     RECT  146.513 236.64 146.581 239.544 ;
     RECT  146.579 155.664 146.585 156.024 ;
     RECT  146.581 236.64 146.585 240.216 ;
     RECT  146.513 206.88 146.617 209.16 ;
     RECT  146.437 210.336 146.617 212.664 ;
     RECT  146.549 136.944 146.621 137.4 ;
     RECT  146.509 241.296 146.627 241.32 ;
     RECT  146.081 242.592 146.627 242.616 ;
     RECT  144.965 165.264 146.629 181.56 ;
     RECT  146.405 188.592 146.675 193.944 ;
     RECT  146.513 201.168 146.675 205.848 ;
     RECT  146.387 153.312 146.693 154.296 ;
     RECT  146.675 188.64 146.693 193.944 ;
     RECT  146.629 165.264 146.765 182.184 ;
     RECT  145.001 216.096 146.765 216.312 ;
     RECT  146.401 232.512 146.765 232.68 ;
     RECT  146.045 142.176 146.771 143.16 ;
     RECT  145.681 162.96 146.833 162.984 ;
     RECT  144.929 164.112 146.833 164.136 ;
     RECT  146.693 188.64 146.837 192.504 ;
     RECT  146.435 194.928 146.837 199.992 ;
     RECT  146.293 218.832 146.837 219.432 ;
     RECT  146.477 220.944 146.869 222.408 ;
     RECT  145.909 147.024 146.873 149.736 ;
     RECT  146.765 216.096 146.905 216.216 ;
     RECT  146.579 160.704 146.909 160.728 ;
     RECT  146.833 162.96 146.909 164.136 ;
     RECT  146.617 206.88 146.981 212.664 ;
     RECT  146.905 215.232 147.011 216.216 ;
     RECT  146.837 192.48 147.017 192.504 ;
     RECT  146.869 220.944 147.059 222.84 ;
     RECT  146.621 136.944 147.089 136.968 ;
     RECT  146.117 145.632 147.089 145.656 ;
     RECT  146.675 201.312 147.089 205.848 ;
     RECT  146.585 236.64 147.089 238.248 ;
     RECT  146.837 188.64 147.107 191.304 ;
     RECT  146.387 151.824 147.125 152.136 ;
     RECT  146.513 183.552 147.157 186.84 ;
     RECT  146.225 213.792 147.157 214.2 ;
     RECT  146.437 140.736 147.161 140.76 ;
     RECT  145.757 227.136 147.233 227.304 ;
     RECT  147.229 139.92 147.265 139.944 ;
     RECT  146.771 142.176 147.265 142.968 ;
     RECT  147.265 142.128 147.481 142.968 ;
     RECT  147.089 203.904 147.481 205.848 ;
     RECT  146.585 239.52 147.481 240.216 ;
     RECT  147.157 182.832 147.517 186.84 ;
     RECT  146.909 163.488 147.553 164.136 ;
     RECT  146.765 165.264 147.553 181.56 ;
     RECT  147.481 239.52 147.553 241.128 ;
     RECT  146.693 193.68 147.589 193.944 ;
     RECT  146.837 194.928 147.589 199.32 ;
     RECT  146.837 218.832 147.589 219.384 ;
     RECT  146.765 232.512 147.589 232.536 ;
     RECT  147.059 222.096 147.625 222.84 ;
     RECT  147.089 201.312 147.637 202.92 ;
     RECT  147.517 182.832 147.661 186.984 ;
     RECT  147.107 188.64 147.661 189.768 ;
     RECT  147.157 213.12 147.733 214.2 ;
     RECT  147.625 222.096 147.733 223.656 ;
     RECT  146.369 225.36 147.733 226.152 ;
     RECT  146.579 157.296 147.781 159 ;
     RECT  147.589 193.68 147.805 199.32 ;
     RECT  147.589 218.304 147.877 219.384 ;
     RECT  147.553 228 147.913 228.072 ;
     RECT  147.125 152.064 147.985 152.136 ;
     RECT  146.693 153.312 147.985 154.008 ;
     RECT  147.781 157.056 147.985 159 ;
     RECT  147.985 156.72 148.021 159 ;
     RECT  147.553 163.488 148.021 181.56 ;
     RECT  147.661 182.832 148.021 189.768 ;
     RECT  147.805 193.68 148.021 199.56 ;
     RECT  147.107 190.752 148.057 191.304 ;
     RECT  146.977 155.04 148.069 155.064 ;
     RECT  148.021 156.144 148.069 159 ;
     RECT  148.057 190.752 148.069 192.264 ;
     RECT  148.021 193.584 148.069 199.56 ;
     RECT  147.553 239.376 148.069 241.128 ;
     RECT  146.873 148.56 148.093 149.736 ;
     RECT  147.985 152.064 148.093 154.008 ;
     RECT  148.069 155.04 148.093 159 ;
     RECT  147.011 215.904 148.165 216.216 ;
     RECT  147.013 138 148.208 138.024 ;
     RECT  147.265 139.104 148.208 139.944 ;
     RECT  147.481 141.072 148.208 142.968 ;
     RECT  146.045 144.288 148.208 144.312 ;
     RECT  147.157 145.824 148.208 145.848 ;
     RECT  146.873 147.504 148.208 147.528 ;
     RECT  148.093 148.56 148.208 150.024 ;
     RECT  148.093 152.064 148.208 159 ;
     RECT  147.553 160.032 148.208 160.056 ;
     RECT  146.549 161.904 148.208 161.928 ;
     RECT  148.021 163.152 148.208 181.56 ;
     RECT  148.021 182.64 148.208 189.768 ;
     RECT  148.069 190.752 148.208 199.56 ;
     RECT  147.637 201.168 148.208 202.92 ;
     RECT  147.481 203.904 148.208 205.896 ;
     RECT  146.981 206.88 148.208 211.8 ;
     RECT  147.733 213.12 148.208 214.296 ;
     RECT  148.165 215.904 148.208 216.456 ;
     RECT  147.877 218.304 148.208 219.48 ;
     RECT  147.059 220.944 148.208 220.968 ;
     RECT  147.733 222.096 148.208 226.152 ;
     RECT  147.913 228 148.208 228.36 ;
     RECT  146.369 229.392 148.208 229.416 ;
     RECT  147.589 231.936 148.208 232.536 ;
     RECT  146.441 234.192 148.208 234.216 ;
     RECT  147.089 236.64 148.208 238.008 ;
     RECT  148.069 239.328 148.208 241.128 ;
     RECT  148.208 2.148 148.312 369.372 ;
     RECT  148.312 2.418 148.504 369.102 ;
     RECT  148.504 170.832 148.529 189.192 ;
     RECT  148.504 148.368 148.601 150.024 ;
     RECT  148.504 233.904 148.601 234.312 ;
     RECT  148.504 162 148.637 169.512 ;
     RECT  148.637 162 148.643 163.8 ;
     RECT  148.504 213.648 148.643 214.824 ;
     RECT  148.504 156.144 148.673 156.744 ;
     RECT  148.643 162 148.673 162.456 ;
     RECT  148.504 211.44 148.673 211.896 ;
     RECT  148.504 223.776 148.673 224.568 ;
     RECT  148.601 233.904 148.673 233.928 ;
     RECT  148.504 236.64 148.673 236.712 ;
     RECT  148.504 218.064 148.691 222.744 ;
     RECT  148.601 148.704 148.709 150.024 ;
     RECT  148.504 190.704 148.709 210.312 ;
     RECT  148.504 230.448 148.709 230.472 ;
     RECT  148.691 218.064 148.745 220.104 ;
     RECT  148.709 190.704 148.781 192.456 ;
     RECT  148.745 218.16 148.781 220.104 ;
     RECT  148.529 170.832 148.787 186.888 ;
     RECT  148.637 164.832 148.817 169.512 ;
     RECT  148.709 193.68 148.817 210.312 ;
     RECT  148.787 178.032 148.835 186.888 ;
     RECT  148.504 138.864 148.853 139.128 ;
     RECT  148.504 158.112 148.853 158.472 ;
     RECT  148.817 201.264 148.853 209.064 ;
     RECT  148.504 239.328 148.853 239.352 ;
     RECT  148.643 214.32 148.883 214.824 ;
     RECT  148.504 141.648 148.889 144.36 ;
     RECT  148.781 218.256 148.889 220.104 ;
     RECT  148.835 178.032 148.925 181.608 ;
     RECT  148.853 201.264 148.925 204.072 ;
     RECT  148.691 221.184 148.925 222.744 ;
     RECT  148.673 223.776 148.925 224.472 ;
     RECT  148.673 162 148.961 162.024 ;
     RECT  148.883 214.8 148.961 214.824 ;
     RECT  148.853 205.056 148.979 209.064 ;
     RECT  148.853 158.256 148.997 158.472 ;
     RECT  148.781 190.704 148.997 192.312 ;
     RECT  148.925 222.096 148.997 222.744 ;
     RECT  148.504 225.888 149.033 228.36 ;
     RECT  148.709 149.232 149.069 150.024 ;
     RECT  148.504 152.064 149.069 154.968 ;
     RECT  148.817 165.648 149.105 169.512 ;
     RECT  149.105 167.28 149.177 169.512 ;
     RECT  148.529 188.304 149.177 189.192 ;
     RECT  148.997 222.288 149.219 222.456 ;
     RECT  148.979 208.224 149.249 209.064 ;
     RECT  148.673 236.64 149.285 236.664 ;
     RECT  148.504 159.504 149.357 160.776 ;
     RECT  148.889 218.832 149.363 220.104 ;
     RECT  149.033 226.128 149.363 228.36 ;
     RECT  149.069 149.232 149.393 149.736 ;
     RECT  148.673 211.488 149.393 211.896 ;
     RECT  148.643 163.68 149.429 163.8 ;
     RECT  148.889 141.648 149.465 143.064 ;
     RECT  148.673 156.144 149.465 156.168 ;
     RECT  148.835 182.64 149.465 186.888 ;
     RECT  148.817 193.68 149.465 200.04 ;
     RECT  149.363 226.608 149.465 228.36 ;
     RECT  148.504 137.856 149.533 137.88 ;
     RECT  149.465 141.648 149.557 142.488 ;
     RECT  148.889 144.336 149.557 144.36 ;
     RECT  149.533 137.616 149.603 137.88 ;
     RECT  149.557 141.168 149.609 142.488 ;
     RECT  149.069 152.064 149.681 153.864 ;
     RECT  149.177 188.496 149.701 189.192 ;
     RECT  148.504 145.872 149.713 146.952 ;
     RECT  149.641 212.256 149.713 212.76 ;
     RECT  149.557 144.336 149.749 144.456 ;
     RECT  149.713 145.872 149.749 147.288 ;
     RECT  149.533 232.512 149.749 232.536 ;
     RECT  149.701 188.496 149.753 189.432 ;
     RECT  149.105 165.648 149.797 166.296 ;
     RECT  148.853 138.864 149.821 139.032 ;
     RECT  149.429 163.776 149.821 163.8 ;
     RECT  149.797 164.928 149.821 166.296 ;
     RECT  149.609 141.696 149.825 142.488 ;
     RECT  149.603 137.856 149.845 137.88 ;
     RECT  149.821 138.864 149.845 139.128 ;
     RECT  149.749 232.176 149.861 232.536 ;
     RECT  149.845 137.856 149.891 139.128 ;
     RECT  149.393 149.232 149.893 149.448 ;
     RECT  149.219 222.288 149.897 222.312 ;
     RECT  148.817 210.096 149.929 210.312 ;
     RECT  149.357 160.032 149.933 160.776 ;
     RECT  148.787 170.832 149.933 177.048 ;
     RECT  148.979 205.056 149.933 207.24 ;
     RECT  149.749 144.336 149.939 147.288 ;
     RECT  149.249 208.8 149.941 209.064 ;
     RECT  149.929 210.096 149.941 211.128 ;
     RECT  148.997 158.256 149.965 158.376 ;
     RECT  149.939 144.336 149.969 146.808 ;
     RECT  148.997 190.704 149.989 191.64 ;
     RECT  149.465 193.68 149.989 196.44 ;
     RECT  148.925 178.08 150.001 181.608 ;
     RECT  149.465 182.64 150.001 186.504 ;
     RECT  149.941 208.8 150.005 211.128 ;
     RECT  149.465 226.848 150.005 228.36 ;
     RECT  148.504 229.344 150.037 229.368 ;
     RECT  149.893 214.752 150.073 214.776 ;
     RECT  149.713 212.256 150.083 213.192 ;
     RECT  148.925 201.264 150.109 203.496 ;
     RECT  149.891 138.768 150.113 138.792 ;
     RECT  148.925 223.776 150.113 223.8 ;
     RECT  150.005 227.328 150.113 228.36 ;
     RECT  149.989 190.704 150.149 196.44 ;
     RECT  148.504 216.432 150.217 216.456 ;
     RECT  149.465 197.424 150.221 200.04 ;
     RECT  150.037 231.024 150.221 231.048 ;
     RECT  149.177 167.616 150.253 169.512 ;
     RECT  150.149 192.864 150.323 196.44 ;
     RECT  149.069 154.944 150.361 154.968 ;
     RECT  149.821 163.776 150.397 166.296 ;
     RECT  150.253 167.52 150.397 169.512 ;
     RECT  150.005 208.8 150.397 209.016 ;
     RECT  149.363 218.832 150.421 219.432 ;
     RECT  150.001 178.08 150.433 186.504 ;
     RECT  150.083 212.64 150.467 213.192 ;
     RECT  150.421 218.832 150.467 219.48 ;
     RECT  149.753 188.496 150.469 189.384 ;
     RECT  150.323 193.632 150.473 196.44 ;
     RECT  150.109 201.12 150.473 203.496 ;
     RECT  150.073 214.752 150.505 215.352 ;
     RECT  150.217 216.432 150.505 216.6 ;
     RECT  149.605 151.008 150.509 151.032 ;
     RECT  150.221 197.664 150.509 200.04 ;
     RECT  150.473 201.12 150.509 203.4 ;
     RECT  149.933 205.104 150.509 207.24 ;
     RECT  149.965 157.872 150.541 158.376 ;
     RECT  149.893 148.704 150.545 149.448 ;
     RECT  149.681 152.88 150.545 153.864 ;
     RECT  150.473 193.728 150.545 196.44 ;
     RECT  150.509 201.12 150.545 201.768 ;
     RECT  150.467 212.64 150.545 212.904 ;
     RECT  150.073 161.856 150.565 161.88 ;
     RECT  150.397 163.008 150.565 169.512 ;
     RECT  150.433 178.08 150.581 186.984 ;
     RECT  150.509 197.76 150.581 200.04 ;
     RECT  150.037 229.344 150.581 229.656 ;
     RECT  150.545 193.728 150.611 196.344 ;
     RECT  150.565 161.856 150.617 169.512 ;
     RECT  150.611 195.024 150.617 196.344 ;
     RECT  150.581 198.336 150.617 200.04 ;
     RECT  150.541 157.872 150.653 158.472 ;
     RECT  150.469 188.064 150.653 189.384 ;
     RECT  150.581 229.632 150.653 229.656 ;
     RECT  149.969 144.336 150.685 144.456 ;
     RECT  150.397 160.848 150.685 160.872 ;
     RECT  150.617 163.776 150.685 169.512 ;
     RECT  149.933 170.832 150.685 171.48 ;
     RECT  150.581 184.176 150.685 186.984 ;
     RECT  150.653 188.064 150.685 189.336 ;
     RECT  149.861 232.512 150.725 232.536 ;
     RECT  150.685 184.176 150.755 189.336 ;
     RECT  150.509 206.16 150.757 207.24 ;
     RECT  150.397 208.608 150.757 209.016 ;
     RECT  150.581 178.08 150.761 183.192 ;
     RECT  149.749 156.72 150.793 156.744 ;
     RECT  150.653 157.872 150.793 158.376 ;
     RECT  150.505 214.752 150.797 217.032 ;
     RECT  150.149 190.704 150.833 191.64 ;
     RECT  150.617 195.456 150.833 196.344 ;
     RECT  149.969 145.872 150.869 146.808 ;
     RECT  150.761 179.088 150.869 183.192 ;
     RECT  150.509 203.136 150.869 203.4 ;
     RECT  150.217 220.896 150.937 220.92 ;
     RECT  150.869 203.136 150.941 203.256 ;
     RECT  150.685 163.776 150.973 171.48 ;
     RECT  149.933 172.848 150.973 177.048 ;
     RECT  150.757 206.16 150.973 209.016 ;
     RECT  150.005 210.096 150.973 211.128 ;
     RECT  150.617 199.392 150.977 200.04 ;
     RECT  150.361 154.944 150.997 155.352 ;
     RECT  150.869 182.64 151.013 183.192 ;
     RECT  150.973 206.16 151.013 211.128 ;
     RECT  150.685 143.664 151.043 144.456 ;
     RECT  150.545 152.88 151.043 153.048 ;
     RECT  150.997 154.416 151.045 155.352 ;
     RECT  149.825 142.464 151.049 142.488 ;
     RECT  151.013 206.16 151.085 209.352 ;
     RECT  150.755 184.176 151.091 187.128 ;
     RECT  150.755 188.448 151.091 189.336 ;
     RECT  150.869 179.088 151.121 181.56 ;
     RECT  150.685 160.848 151.153 161.832 ;
     RECT  150.973 163.776 151.157 177.048 ;
     RECT  150.467 219.072 151.157 219.48 ;
     RECT  150.611 193.728 151.193 193.944 ;
     RECT  150.545 212.736 151.193 212.904 ;
     RECT  151.153 160.8 151.235 161.832 ;
     RECT  150.937 220.656 151.265 220.92 ;
     RECT  151.157 164.352 151.283 177.048 ;
     RECT  150.833 190.704 151.373 191.496 ;
     RECT  150.797 216.432 151.405 217.032 ;
     RECT  150.797 214.752 151.409 215.352 ;
     RECT  151.013 182.736 151.445 183.192 ;
     RECT  150.545 148.704 151.477 148.728 ;
     RECT  151.283 168.672 151.481 177.048 ;
     RECT  151.481 171.36 151.513 177.048 ;
     RECT  150.761 178.08 151.513 178.104 ;
     RECT  151.405 216.432 151.517 217.656 ;
     RECT  151.193 212.88 151.549 212.904 ;
     RECT  151.091 188.832 151.553 189.336 ;
     RECT  151.517 217.008 151.553 217.656 ;
     RECT  150.869 146.496 151.585 146.808 ;
     RECT  150.113 227.328 151.585 227.4 ;
     RECT  151.585 152.736 151.621 152.76 ;
     RECT  151.549 212.88 151.621 213.528 ;
     RECT  151.409 214.752 151.621 215.304 ;
     RECT  151.553 217.632 151.625 217.656 ;
     RECT  150.793 149.904 151.657 149.928 ;
     RECT  151.157 219.072 151.657 219.096 ;
     RECT  151.235 160.848 151.661 161.832 ;
     RECT  150.545 201.264 151.661 201.768 ;
     RECT  151.657 149.76 151.697 149.928 ;
     RECT  151.283 164.352 151.733 167.544 ;
     RECT  151.621 152.496 151.765 152.76 ;
     RECT  151.441 222.528 151.765 222.552 ;
     RECT  150.793 156.72 151.805 158.376 ;
     RECT  151.733 164.4 151.805 167.544 ;
     RECT  151.091 184.176 151.841 186.984 ;
     RECT  151.657 218.208 151.841 219.096 ;
     RECT  151.445 182.976 151.877 183.192 ;
     RECT  151.013 211.008 151.909 211.128 ;
     RECT  151.765 151.92 151.913 152.76 ;
     RECT  151.661 161.136 151.945 161.832 ;
     RECT  151.621 212.88 151.985 215.304 ;
     RECT  150.941 203.136 152.017 203.16 ;
     RECT  151.841 218.208 152.021 218.904 ;
     RECT  150.833 195.456 152.053 195.96 ;
     RECT  152.017 202.896 152.053 203.16 ;
     RECT  151.585 146.496 152.057 147.048 ;
     RECT  151.373 191.472 152.057 191.496 ;
     RECT  151.193 193.728 152.057 193.752 ;
     RECT  151.985 212.88 152.093 213.672 ;
     RECT  152.057 146.784 152.125 147.048 ;
     RECT  151.477 148.176 152.125 148.728 ;
     RECT  151.045 154.416 152.129 155.688 ;
     RECT  151.765 222.48 152.129 222.552 ;
     RECT  151.913 152.496 152.165 152.76 ;
     RECT  151.513 171.36 152.165 178.104 ;
     RECT  151.085 206.16 152.197 206.952 ;
     RECT  151.085 207.936 152.197 209.352 ;
     RECT  152.129 154.416 152.237 155.16 ;
     RECT  151.661 201.6 152.237 201.768 ;
     RECT  151.265 220.896 152.237 220.92 ;
     RECT  152.165 178.032 152.245 178.104 ;
     RECT  151.121 179.712 152.245 181.56 ;
     RECT  151.877 183.168 152.245 183.192 ;
     RECT  151.841 184.176 152.245 186.936 ;
     RECT  152.053 195.312 152.269 195.96 ;
     RECT  152.125 146.784 152.273 148.728 ;
     RECT  152.165 152.64 152.273 152.76 ;
     RECT  152.017 225.792 152.273 225.816 ;
     RECT  151.945 161.136 152.305 161.88 ;
     RECT  152.269 194.352 152.305 195.96 ;
     RECT  152.245 183.168 152.309 186.936 ;
     RECT  152.273 147.024 152.341 148.728 ;
     RECT  151.697 149.76 152.341 149.784 ;
     RECT  152.237 154.416 152.345 154.776 ;
     RECT  152.165 171.36 152.345 177.048 ;
     RECT  151.985 214.848 152.345 215.304 ;
     RECT  152.341 147.024 152.381 149.784 ;
     RECT  151.481 168.672 152.381 170.28 ;
     RECT  152.345 171.36 152.381 171.624 ;
     RECT  152.345 173.28 152.381 177.048 ;
     RECT  152.381 147.024 152.387 149.352 ;
     RECT  152.381 168.96 152.417 170.28 ;
     RECT  152.237 201.744 152.449 201.768 ;
     RECT  152.053 202.896 152.449 203.544 ;
     RECT  150.509 205.104 152.449 205.128 ;
     RECT  152.197 206.16 152.449 209.352 ;
     RECT  152.381 176.592 152.633 177.048 ;
     RECT  151.805 158.352 152.701 158.376 ;
     RECT  152.305 161.136 152.725 162.216 ;
     RECT  151.585 227.328 152.725 228.024 ;
     RECT  152.305 194.352 152.881 196.296 ;
     RECT  152.725 227.328 152.917 228.744 ;
     RECT  152.701 158.352 152.953 158.568 ;
     RECT  152.417 169.344 152.953 170.28 ;
     RECT  152.381 171.36 152.953 171.384 ;
     RECT  151.909 211.008 152.989 211.896 ;
     RECT  152.449 201.744 153.013 203.544 ;
     RECT  152.449 205.104 153.013 209.352 ;
     RECT  152.989 210.432 153.013 211.896 ;
     RECT  152.917 226.896 153.097 228.744 ;
     RECT  152.725 161.136 153.133 163.032 ;
     RECT  152.633 176.688 153.169 177.048 ;
     RECT  152.245 178.032 153.169 181.56 ;
     RECT  150.977 199.392 153.205 199.944 ;
     RECT  153.013 201.744 153.205 209.352 ;
     RECT  153.013 210.336 153.205 211.896 ;
     RECT  151.805 164.88 153.241 166.776 ;
     RECT  151.553 189.312 153.241 189.336 ;
     RECT  153.133 161.088 153.253 163.032 ;
     RECT  152.629 216.624 153.313 216.648 ;
     RECT  152.309 183.168 153.349 183.192 ;
     RECT  152.309 184.176 153.349 186.936 ;
     RECT  153.205 201.744 153.349 211.896 ;
     RECT  153.205 199.344 153.385 199.944 ;
     RECT  153.349 183.168 153.421 187.512 ;
     RECT  152.129 222.48 153.457 222.504 ;
     RECT  151.805 156.72 153.493 157.08 ;
     RECT  152.953 158.352 153.493 159.528 ;
     RECT  152.629 217.776 153.493 217.8 ;
     RECT  153.457 222.24 153.493 222.504 ;
     RECT  152.773 193.344 153.529 193.368 ;
     RECT  152.881 194.352 153.529 196.68 ;
     RECT  152.387 147.024 153.608 149.304 ;
     RECT  152.665 150.336 153.608 150.36 ;
     RECT  152.629 151.44 153.608 151.464 ;
     RECT  152.629 152.784 153.608 152.808 ;
     RECT  152.345 154.752 153.608 154.776 ;
     RECT  153.493 156.48 153.608 159.528 ;
     RECT  153.253 161.088 153.608 163.224 ;
     RECT  153.241 164.88 153.608 167.592 ;
     RECT  152.953 169.344 153.608 171.384 ;
     RECT  152.381 173.28 153.608 175.368 ;
     RECT  153.169 176.688 153.608 181.56 ;
     RECT  153.421 182.928 153.608 187.512 ;
     RECT  153.241 188.544 153.608 189.336 ;
     RECT  152.773 190.896 153.608 190.92 ;
     RECT  153.529 193.344 153.608 196.68 ;
     RECT  150.617 198.336 153.608 198.36 ;
     RECT  153.385 199.344 153.608 200.184 ;
     RECT  153.349 201.6 153.608 211.896 ;
     RECT  152.093 213.648 153.608 213.672 ;
     RECT  152.345 215.28 153.608 215.304 ;
     RECT  153.313 216.432 153.608 216.648 ;
     RECT  153.493 217.728 153.608 217.8 ;
     RECT  152.021 218.88 153.608 218.904 ;
     RECT  153.493 221.664 153.608 222.504 ;
     RECT  153.097 226.368 153.608 228.744 ;
     RECT  153.608 2.148 153.712 369.372 ;
     RECT  153.712 2.418 153.904 369.102 ;
     RECT  153.904 212.928 153.965 214.344 ;
     RECT  153.904 160.272 154.019 170.52 ;
     RECT  153.965 213.216 154.037 214.344 ;
     RECT  153.904 172.704 154.073 176.664 ;
     RECT  153.904 188.688 154.109 190.968 ;
     RECT  153.904 198.336 154.109 203.544 ;
     RECT  153.904 224.976 154.181 227.208 ;
     RECT  154.109 188.688 154.217 190.056 ;
     RECT  153.904 192.624 154.217 194.856 ;
     RECT  154.181 224.976 154.253 225 ;
     RECT  153.904 182.928 154.289 183.432 ;
     RECT  154.109 200.688 154.397 203.544 ;
     RECT  154.109 198.336 154.451 199.368 ;
     RECT  154.019 162.144 154.469 170.52 ;
     RECT  154.217 193.2 154.469 194.856 ;
     RECT  153.904 204.768 154.499 205.368 ;
     RECT  154.289 183.408 154.505 183.432 ;
     RECT  154.397 201.744 154.505 203.544 ;
     RECT  153.904 208.512 154.505 209.352 ;
     RECT  153.904 223.344 154.541 223.416 ;
     RECT  153.904 219.264 154.613 219.288 ;
     RECT  154.541 223.344 154.613 223.368 ;
     RECT  153.904 196.32 154.643 197.256 ;
     RECT  154.469 193.2 154.649 194.808 ;
     RECT  154.451 198.384 154.649 199.368 ;
     RECT  154.505 208.56 154.649 209.352 ;
     RECT  153.904 216.048 154.649 216.456 ;
     RECT  154.469 162.144 154.787 169.704 ;
     RECT  154.649 194.784 154.829 194.808 ;
     RECT  154.181 226.272 154.829 227.208 ;
     RECT  154.505 203.52 154.835 203.544 ;
     RECT  153.904 177.792 154.883 181.8 ;
     RECT  153.904 185.136 154.883 187.512 ;
     RECT  154.883 178.128 154.931 180.552 ;
     RECT  153.904 156.096 154.933 156.744 ;
     RECT  153.904 158.352 154.933 159.24 ;
     RECT  154.933 156.096 154.979 159.24 ;
     RECT  154.019 160.272 155.005 161.112 ;
     RECT  154.787 162.144 155.005 163.224 ;
     RECT  154.505 202.224 155.045 202.344 ;
     RECT  154.883 181.536 155.081 181.8 ;
     RECT  154.787 164.304 155.153 169.704 ;
     RECT  154.649 193.2 155.153 193.704 ;
     RECT  155.005 160.272 155.221 163.224 ;
     RECT  154.073 172.704 155.221 176.232 ;
     RECT  153.904 206.88 155.221 207.528 ;
     RECT  154.829 226.272 155.261 226.296 ;
     RECT  154.979 158.976 155.267 159.24 ;
     RECT  153.904 153.312 155.297 153.336 ;
     RECT  154.883 186.192 155.317 187.512 ;
     RECT  154.499 204.768 155.365 204.792 ;
     RECT  155.317 186.192 155.369 188.136 ;
     RECT  154.933 218.304 155.369 218.328 ;
     RECT  155.045 202.32 155.477 202.344 ;
     RECT  153.904 210.768 155.477 211.896 ;
     RECT  154.037 213.408 155.477 214.344 ;
     RECT  154.397 200.688 155.545 200.712 ;
     RECT  155.401 184.752 155.585 184.776 ;
     RECT  154.649 198.384 155.585 198.408 ;
     RECT  155.153 169.296 155.617 169.704 ;
     RECT  155.221 172.704 155.621 176.616 ;
     RECT  154.979 156.096 155.657 157.944 ;
     RECT  155.369 186.192 155.657 187.56 ;
     RECT  154.217 189.216 155.657 190.056 ;
     RECT  154.649 216.048 155.657 216.072 ;
     RECT  155.477 214.32 155.689 214.344 ;
     RECT  155.267 158.976 155.699 159.192 ;
     RECT  155.153 164.304 155.699 167.976 ;
     RECT  155.477 210.768 155.725 211.848 ;
     RECT  155.689 214.32 155.729 214.872 ;
     RECT  155.699 158.976 155.747 159.048 ;
     RECT  155.617 169.296 155.765 170.616 ;
     RECT  155.221 206.496 155.797 207.528 ;
     RECT  155.729 214.848 155.797 214.872 ;
     RECT  155.365 204.048 155.801 204.792 ;
     RECT  155.797 214.848 155.891 214.92 ;
     RECT  154.931 178.128 155.905 178.152 ;
     RECT  154.931 179.904 155.905 180.552 ;
     RECT  155.725 210.336 155.945 211.848 ;
     RECT  155.905 178.128 155.987 180.552 ;
     RECT  155.797 206.4 156.049 207.72 ;
     RECT  154.649 209.328 156.049 209.352 ;
     RECT  156.049 209.328 156.089 209.736 ;
     RECT  153.904 154.464 156.157 154.488 ;
     RECT  155.221 160.224 156.157 163.224 ;
     RECT  155.621 174.288 156.157 176.616 ;
     RECT  156.089 209.712 156.179 209.736 ;
     RECT  155.153 193.2 156.181 193.224 ;
     RECT  155.657 189.216 156.193 189.864 ;
     RECT  156.157 174.288 156.227 176.712 ;
     RECT  156.181 192.624 156.227 193.224 ;
     RECT  156.229 152.976 156.265 153 ;
     RECT  156.157 153.984 156.265 154.488 ;
     RECT  156.227 192.624 156.269 192.648 ;
     RECT  155.699 164.88 156.305 167.976 ;
     RECT  156.193 188.688 156.323 189.864 ;
     RECT  155.801 204.48 156.337 204.792 ;
     RECT  156.049 206.4 156.337 208.056 ;
     RECT  156.323 188.688 156.341 189.768 ;
     RECT  156.157 194.352 156.341 194.376 ;
     RECT  155.657 156.72 156.377 157.944 ;
     RECT  156.377 156.768 156.409 157.944 ;
     RECT  156.409 219.6 156.481 219.864 ;
     RECT  155.545 200.688 156.517 201.096 ;
     RECT  156.227 174.288 156.521 176.232 ;
     RECT  155.657 186.912 156.521 187.56 ;
     RECT  155.987 179.904 156.553 180.552 ;
     RECT  155.081 181.536 156.553 181.56 ;
     RECT  155.765 169.296 156.557 169.704 ;
     RECT  155.945 211.056 156.565 211.848 ;
     RECT  156.521 174.336 156.611 176.232 ;
     RECT  156.565 211.056 156.661 212.184 ;
     RECT  155.621 172.704 156.733 173.304 ;
     RECT  156.013 155.472 156.769 155.496 ;
     RECT  156.557 169.296 156.773 169.656 ;
     RECT  156.611 174.336 156.773 176.136 ;
     RECT  156.337 218.496 156.773 218.52 ;
     RECT  156.773 169.296 156.805 169.368 ;
     RECT  156.157 160.176 156.877 163.224 ;
     RECT  155.987 178.128 156.877 178.392 ;
     RECT  156.661 211.056 156.877 212.664 ;
     RECT  156.409 156.768 156.953 158.52 ;
     RECT  156.733 172.608 156.953 173.304 ;
     RECT  156.481 219.552 156.953 219.864 ;
     RECT  156.521 186.912 156.985 186.984 ;
     RECT  156.341 189.744 156.989 189.768 ;
     RECT  156.953 219.6 156.989 219.864 ;
     RECT  156.305 164.88 157.021 167.496 ;
     RECT  156.877 177.456 157.021 178.392 ;
     RECT  156.337 204.48 157.021 208.056 ;
     RECT  156.341 188.688 157.025 188.712 ;
     RECT  156.265 152.976 157.061 154.488 ;
     RECT  156.625 170.976 157.061 171 ;
     RECT  157.061 154.032 157.093 154.488 ;
     RECT  156.769 155.472 157.093 155.64 ;
     RECT  156.517 200.112 157.093 201.096 ;
     RECT  157.021 204 157.093 208.056 ;
     RECT  157.093 200.112 157.097 201.288 ;
     RECT  157.021 164.688 157.129 167.496 ;
     RECT  157.097 200.688 157.129 201.288 ;
     RECT  156.953 156.768 157.133 158.424 ;
     RECT  157.021 177.456 157.169 178.68 ;
     RECT  156.553 179.904 157.169 181.56 ;
     RECT  157.133 157.296 157.187 158.424 ;
     RECT  156.805 169.248 157.201 169.368 ;
     RECT  157.093 203.856 157.205 208.056 ;
     RECT  157.129 200.688 157.241 201.768 ;
     RECT  157.201 168.96 157.273 169.368 ;
     RECT  155.891 214.848 157.273 214.872 ;
     RECT  157.129 216.336 157.273 216.36 ;
     RECT  156.877 211.056 157.285 213.144 ;
     RECT  157.061 152.976 157.331 153 ;
     RECT  157.241 200.688 157.349 201.288 ;
     RECT  157.285 210.336 157.421 213.144 ;
     RECT  157.273 214.848 157.421 216.36 ;
     RECT  157.165 222.624 157.421 222.648 ;
     RECT  157.169 178.128 157.457 178.68 ;
     RECT  157.093 154.032 157.493 155.64 ;
     RECT  157.205 204 157.529 207.528 ;
     RECT  157.493 155.616 157.601 155.64 ;
     RECT  157.457 178.128 157.601 178.44 ;
     RECT  156.877 159.696 157.621 163.224 ;
     RECT  157.525 184.704 157.637 184.728 ;
     RECT  157.529 204.24 157.637 207.528 ;
     RECT  157.273 168.864 157.669 169.368 ;
     RECT  157.621 159.6 157.673 163.224 ;
     RECT  157.421 210.384 157.673 213.144 ;
     RECT  157.669 168.72 157.715 169.368 ;
     RECT  157.673 210.384 157.763 211.848 ;
     RECT  157.421 214.848 157.763 215.688 ;
     RECT  157.741 197.712 157.765 197.736 ;
     RECT  157.169 179.904 157.777 180.552 ;
     RECT  157.637 205.632 157.781 207.528 ;
     RECT  157.763 210.72 157.781 211.848 ;
     RECT  157.765 197.712 157.811 197.832 ;
     RECT  156.953 172.752 157.817 173.304 ;
     RECT  157.813 170.736 157.889 170.76 ;
     RECT  157.777 191.472 157.889 191.496 ;
     RECT  157.811 197.808 157.889 197.832 ;
     RECT  157.187 157.296 157.907 158.376 ;
     RECT  157.673 159.648 157.909 163.224 ;
     RECT  157.129 164.448 157.909 167.496 ;
     RECT  157.493 154.032 157.925 154.44 ;
     RECT  157.907 157.296 157.925 157.944 ;
     RECT  156.989 219.6 157.925 219.624 ;
     RECT  157.909 159.648 157.955 167.496 ;
     RECT  157.673 213.072 157.993 213.144 ;
     RECT  157.955 161.328 157.997 167.496 ;
     RECT  157.637 204.24 157.997 204.6 ;
     RECT  157.777 194.352 158.029 194.376 ;
     RECT  157.817 173.136 158.065 173.304 ;
     RECT  156.773 174.336 158.065 175.896 ;
     RECT  158.029 193.2 158.101 193.224 ;
     RECT  157.993 213.072 158.101 213.192 ;
     RECT  157.169 181.536 158.137 181.56 ;
     RECT  158.101 192.624 158.245 193.224 ;
     RECT  158.029 194.304 158.245 194.376 ;
     RECT  157.349 200.688 158.317 201.096 ;
     RECT  158.101 213.072 158.317 213.528 ;
     RECT  157.997 164.448 158.605 167.496 ;
     RECT  158.281 155.712 158.629 155.736 ;
     RECT  157.925 157.296 158.629 157.896 ;
     RECT  158.629 155.712 158.713 157.896 ;
     RECT  158.245 199.68 158.713 199.704 ;
     RECT  158.317 200.688 158.713 201.48 ;
     RECT  157.781 206.64 158.821 207.528 ;
     RECT  158.629 208.608 158.821 208.632 ;
     RECT  158.713 199.68 158.965 201.48 ;
     RECT  157.777 202.848 158.965 202.872 ;
     RECT  158.785 170.784 159.001 170.808 ;
     RECT  157.925 154.416 159.008 154.44 ;
     RECT  158.713 155.616 159.008 157.896 ;
     RECT  157.955 159.648 159.008 160.152 ;
     RECT  157.997 161.328 159.008 163.224 ;
     RECT  158.605 164.448 159.008 167.592 ;
     RECT  157.715 168.96 159.008 169.368 ;
     RECT  159.001 170.784 159.008 171 ;
     RECT  158.065 173.136 159.008 175.896 ;
     RECT  157.601 178.128 159.008 178.248 ;
     RECT  157.777 179.616 159.008 180.552 ;
     RECT  158.137 181.536 159.008 181.608 ;
     RECT  157.669 183.264 159.008 183.288 ;
     RECT  158.281 185.232 159.008 185.256 ;
     RECT  156.985 186.432 159.008 186.984 ;
     RECT  158.425 189.024 159.008 189.048 ;
     RECT  158.245 192.624 159.008 194.376 ;
     RECT  156.157 195.936 159.008 195.96 ;
     RECT  158.821 197.184 159.008 197.208 ;
     RECT  158.965 199.68 159.008 201.576 ;
     RECT  158.965 202.848 159.008 203.16 ;
     RECT  157.997 204.24 159.008 204.504 ;
     RECT  157.781 205.632 159.008 205.656 ;
     RECT  158.821 206.64 159.008 208.632 ;
     RECT  157.781 211.584 159.008 211.848 ;
     RECT  158.317 213.072 159.008 213.624 ;
     RECT  157.763 214.848 159.008 214.872 ;
     RECT  157.717 216.864 159.008 216.888 ;
     RECT  158.281 219.936 159.008 219.96 ;
     RECT  158.209 221.232 159.008 221.256 ;
     RECT  159.008 2.148 159.112 369.372 ;
     RECT  159.112 2.418 159.304 369.102 ;
     RECT  159.304 213.12 159.329 213.192 ;
     RECT  159.304 154.992 159.365 156.456 ;
     RECT  159.304 195.936 159.365 196.68 ;
     RECT  159.304 200.208 159.365 201.576 ;
     RECT  159.365 200.784 159.437 201.576 ;
     RECT  159.304 169.344 159.443 169.8 ;
     RECT  159.304 159.648 159.473 160.008 ;
     RECT  159.304 202.896 159.473 204.504 ;
     RECT  159.329 213.168 159.509 213.192 ;
     RECT  159.304 164.544 159.539 164.568 ;
     RECT  159.304 170.784 159.539 171.576 ;
     RECT  159.304 165.648 159.581 167.592 ;
     RECT  159.304 172.896 159.581 175.464 ;
     RECT  159.365 154.992 159.587 155.016 ;
     RECT  159.365 156.432 159.587 156.456 ;
     RECT  159.473 204.24 159.617 204.504 ;
     RECT  159.304 188.496 159.635 189.24 ;
     RECT  159.304 209.328 159.635 209.352 ;
     RECT  159.304 157.488 159.653 157.512 ;
     RECT  159.473 159.648 159.653 159.72 ;
     RECT  159.304 161.328 159.653 161.352 ;
     RECT  159.304 207.168 159.653 207.192 ;
     RECT  159.617 204.48 159.683 204.504 ;
     RECT  159.304 205.632 159.689 205.656 ;
     RECT  159.473 202.896 159.725 202.92 ;
     RECT  159.304 190.896 159.731 190.92 ;
     RECT  159.304 210.336 159.731 210.36 ;
     RECT  159.304 214.704 159.869 214.728 ;
     RECT  159.304 199.104 159.923 199.128 ;
     RECT  159.437 200.784 159.923 200.808 ;
     RECT  159.635 188.496 159.977 188.52 ;
     RECT  159.304 192.192 160.013 192.216 ;
     RECT  159.365 196.656 160.013 196.68 ;
     RECT  159.304 176.688 160.019 176.712 ;
     RECT  159.653 159.696 160.193 159.72 ;
     RECT  159.539 171.024 160.229 171.576 ;
     RECT  159.581 173.136 160.309 175.464 ;
     RECT  160.229 171.552 160.355 171.576 ;
     RECT  160.309 173.136 160.355 175.608 ;
     RECT  159.443 169.344 160.441 169.704 ;
     RECT  159.581 167.04 160.499 167.592 ;
     RECT  160.441 168.624 160.499 169.704 ;
     RECT  160.355 173.28 160.697 175.608 ;
     RECT  159.581 165.648 160.801 165.672 ;
     RECT  159.304 193.776 160.805 193.8 ;
     RECT  160.801 165.648 160.883 165.864 ;
     RECT  160.499 167.568 160.883 167.592 ;
     RECT  160.883 165.648 164.408 165.672 ;
     RECT  160.499 169.344 164.408 169.368 ;
     RECT  160.697 173.28 164.408 175.464 ;
     RECT  159.304 179.904 164.408 180.552 ;
     RECT  159.304 181.536 164.408 181.56 ;
     RECT  164.408 2.148 164.512 369.372 ;
     RECT  164.512 2.418 164.704 369.102 ;
     RECT  164.704 165.648 169.808 165.672 ;
     RECT  164.704 169.344 169.808 169.368 ;
     RECT  164.704 173.28 169.808 175.464 ;
     RECT  164.704 179.904 169.808 180.552 ;
     RECT  164.704 181.536 169.808 181.56 ;
     RECT  169.808 2.148 169.912 369.372 ;
     RECT  169.912 2.418 170.104 369.102 ;
     RECT  170.104 165.648 175.208 165.672 ;
     RECT  170.104 169.344 175.208 169.368 ;
     RECT  170.104 173.28 175.208 175.464 ;
     RECT  170.104 179.904 175.208 180.552 ;
     RECT  170.104 181.536 175.208 181.56 ;
     RECT  175.208 2.148 175.312 369.372 ;
     RECT  175.312 2.418 175.504 369.102 ;
     RECT  175.504 165.648 180.608 165.672 ;
     RECT  175.504 169.344 180.608 169.368 ;
     RECT  175.504 173.28 180.608 175.464 ;
     RECT  175.504 179.904 180.608 180.552 ;
     RECT  175.504 181.536 180.608 181.56 ;
     RECT  180.608 2.148 180.712 369.372 ;
     RECT  180.712 2.418 180.904 369.102 ;
     RECT  180.904 165.648 186.008 165.672 ;
     RECT  180.904 169.344 186.008 169.368 ;
     RECT  180.904 173.28 186.008 175.464 ;
     RECT  180.904 179.904 186.008 180.552 ;
     RECT  180.904 181.536 186.008 181.56 ;
     RECT  186.008 2.148 186.112 369.372 ;
     RECT  186.112 2.418 186.304 369.102 ;
     RECT  186.304 165.648 191.408 165.672 ;
     RECT  186.304 169.344 191.408 169.368 ;
     RECT  186.304 173.28 191.408 175.464 ;
     RECT  186.304 179.904 191.408 180.552 ;
     RECT  186.304 181.536 191.408 181.56 ;
     RECT  191.408 2.148 191.512 369.372 ;
     RECT  191.512 2.418 191.704 369.102 ;
     RECT  191.704 165.648 196.808 165.672 ;
     RECT  191.704 169.344 196.808 169.368 ;
     RECT  191.704 173.28 196.808 175.464 ;
     RECT  191.704 179.904 196.808 180.552 ;
     RECT  191.704 181.536 196.808 181.56 ;
     RECT  196.808 2.148 196.912 369.372 ;
     RECT  196.912 2.418 197.104 369.102 ;
     RECT  197.104 165.648 202.208 165.672 ;
     RECT  197.104 169.344 202.208 169.368 ;
     RECT  197.104 173.28 202.208 175.464 ;
     RECT  197.104 179.904 202.208 180.552 ;
     RECT  197.104 181.536 202.208 181.56 ;
     RECT  202.208 2.148 202.312 369.372 ;
     RECT  202.312 2.418 202.504 369.102 ;
     RECT  202.504 165.648 207.608 165.672 ;
     RECT  202.504 169.344 207.608 169.368 ;
     RECT  202.504 173.28 207.608 175.464 ;
     RECT  202.504 179.904 207.608 180.552 ;
     RECT  202.504 181.536 207.608 181.56 ;
     RECT  207.608 2.148 207.712 369.372 ;
     RECT  207.712 2.418 207.904 369.102 ;
     RECT  207.904 165.648 213.008 165.672 ;
     RECT  207.904 169.344 213.008 169.368 ;
     RECT  207.904 173.28 213.008 175.464 ;
     RECT  207.904 179.904 213.008 180.552 ;
     RECT  207.904 181.536 213.008 181.56 ;
     RECT  213.008 2.148 213.112 369.372 ;
     RECT  213.112 2.418 213.304 369.102 ;
     RECT  213.304 165.648 218.408 165.672 ;
     RECT  213.304 169.344 218.408 169.368 ;
     RECT  213.304 173.28 218.408 175.464 ;
     RECT  213.304 179.904 218.408 180.552 ;
     RECT  213.304 181.536 218.408 181.56 ;
     RECT  218.408 2.148 218.512 369.372 ;
     RECT  218.512 2.418 218.704 369.102 ;
     RECT  218.704 165.648 223.808 165.672 ;
     RECT  218.704 169.344 223.808 169.368 ;
     RECT  218.704 173.28 223.808 175.464 ;
     RECT  218.704 179.904 223.808 180.552 ;
     RECT  218.704 181.536 223.808 181.56 ;
     RECT  223.808 2.148 223.912 369.372 ;
     RECT  223.912 2.418 224.104 369.102 ;
     RECT  224.104 165.648 229.208 165.672 ;
     RECT  224.104 169.344 229.208 169.368 ;
     RECT  224.104 173.28 229.208 175.464 ;
     RECT  224.104 179.904 229.208 180.552 ;
     RECT  224.104 181.536 229.208 181.56 ;
     RECT  229.208 2.148 229.312 369.372 ;
     RECT  229.312 2.418 229.504 369.102 ;
     RECT  229.504 165.648 234.608 165.672 ;
     RECT  229.504 169.344 234.608 169.368 ;
     RECT  229.504 173.28 234.608 175.464 ;
     RECT  229.504 179.904 234.608 180.552 ;
     RECT  229.504 181.536 234.608 181.56 ;
     RECT  234.608 2.148 234.712 369.372 ;
     RECT  234.712 2.418 234.904 369.102 ;
     RECT  234.904 173.28 238.313 175.464 ;
     RECT  234.904 165.648 240.008 165.672 ;
     RECT  234.904 169.344 240.008 169.368 ;
     RECT  238.313 173.424 240.008 175.464 ;
     RECT  234.904 179.904 240.008 180.552 ;
     RECT  234.904 181.536 240.008 181.56 ;
     RECT  240.008 2.148 240.112 369.372 ;
     RECT  240.112 2.418 240.304 369.102 ;
     RECT  240.304 173.424 243.173 175.464 ;
     RECT  243.173 173.664 243.857 175.464 ;
     RECT  240.304 169.344 244.289 169.368 ;
     RECT  243.857 175.296 244.753 175.464 ;
     RECT  240.304 165.648 245.408 165.672 ;
     RECT  243.857 173.664 245.408 173.688 ;
     RECT  244.753 175.296 245.408 176.184 ;
     RECT  240.304 179.904 245.408 180.552 ;
     RECT  240.304 181.536 245.408 181.56 ;
     RECT  245.408 2.148 245.512 369.372 ;
     RECT  245.512 2.418 245.704 369.102 ;
     RECT  245.704 173.616 246.697 174.024 ;
     RECT  245.704 175.344 246.697 176.232 ;
     RECT  245.704 180.336 246.733 180.36 ;
     RECT  246.733 180.144 246.769 180.36 ;
     RECT  246.769 180.048 247.273 180.36 ;
     RECT  247.273 179.856 247.309 180.36 ;
     RECT  246.697 173.616 247.345 176.232 ;
     RECT  247.309 179.76 247.345 180.36 ;
     RECT  247.345 173.52 248.281 176.424 ;
     RECT  248.281 173.52 248.364 176.52 ;
     RECT  247.345 179.664 248.364 180.36 ;
    LAYER M5 ;
     RECT  2.4 2.137 2.52 2.151 ;
     RECT  7.8 2.137 7.92 2.151 ;
     RECT  13.2 2.137 13.32 2.151 ;
     RECT  18.6 2.137 18.72 2.151 ;
     RECT  24 2.137 24.12 2.151 ;
     RECT  29.4 2.137 29.52 2.151 ;
     RECT  34.8 2.137 34.92 2.151 ;
     RECT  40.2 2.137 40.32 2.151 ;
     RECT  45.6 2.137 45.72 2.151 ;
     RECT  51 2.137 51.12 2.151 ;
     RECT  56.4 2.137 56.52 2.151 ;
     RECT  61.8 2.137 61.92 2.151 ;
     RECT  67.2 2.137 67.32 2.151 ;
     RECT  72.6 2.137 72.72 2.151 ;
     RECT  78 2.137 78.12 2.151 ;
     RECT  83.4 2.137 83.52 2.151 ;
     RECT  88.8 2.137 88.92 2.151 ;
     RECT  94.2 2.137 94.32 2.151 ;
     RECT  99.6 2.137 99.72 2.151 ;
     RECT  105 2.137 105.12 2.151 ;
     RECT  110.4 2.137 110.52 2.151 ;
     RECT  115.8 2.137 115.92 2.151 ;
     RECT  121.2 2.137 121.32 2.151 ;
     RECT  126.6 2.137 126.72 2.151 ;
     RECT  132 2.137 132.12 2.151 ;
     RECT  137.4 2.137 137.52 2.151 ;
     RECT  142.8 2.137 142.92 2.151 ;
     RECT  148.2 2.137 148.32 2.151 ;
     RECT  153.6 2.137 153.72 2.151 ;
     RECT  159 2.137 159.12 2.151 ;
     RECT  164.4 2.137 164.52 2.151 ;
     RECT  169.8 2.137 169.92 2.151 ;
     RECT  175.2 2.137 175.32 2.151 ;
     RECT  180.6 2.137 180.72 2.151 ;
     RECT  186 2.137 186.12 2.151 ;
     RECT  191.4 2.137 191.52 2.151 ;
     RECT  196.8 2.137 196.92 2.151 ;
     RECT  202.2 2.137 202.32 2.151 ;
     RECT  207.6 2.137 207.72 2.151 ;
     RECT  213 2.137 213.12 2.151 ;
     RECT  218.4 2.137 218.52 2.151 ;
     RECT  223.8 2.137 223.92 2.151 ;
     RECT  229.2 2.137 229.32 2.151 ;
     RECT  234.6 2.137 234.72 2.151 ;
     RECT  240 2.137 240.12 2.151 ;
     RECT  245.4 2.137 245.52 2.151 ;
     RECT  141.12 132.181 141.144 132.757 ;
     RECT  142.8 2.151 143.112 132.757 ;
     RECT  145.392 132.181 145.416 133.187 ;
     RECT  141.12 132.757 141.336 133.571 ;
     RECT  145.344 133.717 145.368 133.861 ;
     RECT  141.312 133.571 141.336 134.005 ;
     RECT  141.312 134.005 141.624 134.051 ;
     RECT  142.8 132.757 143.304 134.291 ;
     RECT  138.768 133.285 138.792 134.293 ;
     RECT  141.6 134.051 141.624 134.579 ;
     RECT  137.4 2.151 137.712 134.629 ;
     RECT  138.768 134.293 139.032 134.629 ;
     RECT  144.96 133.861 145.368 135.107 ;
     RECT  137.4 134.629 139.032 135.155 ;
     RECT  142.8 134.291 143.256 135.349 ;
     RECT  142.8 135.349 143.64 136.787 ;
     RECT  142.8 136.787 143.208 136.979 ;
     RECT  137.4 135.155 138.696 137.267 ;
     RECT  137.4 137.267 137.832 137.363 ;
     RECT  144.96 135.107 144.984 137.365 ;
     RECT  149.568 137.605 149.592 137.845 ;
     RECT  144.96 137.365 145.224 138.563 ;
     RECT  142.8 136.979 143.112 138.949 ;
     RECT  139.632 138.469 139.656 139.139 ;
     RECT  149.568 137.845 149.88 139.139 ;
     RECT  142.464 138.949 143.112 139.717 ;
     RECT  146.736 136.933 146.76 139.909 ;
     RECT  148.2 2.151 148.512 139.909 ;
     RECT  144.96 138.563 144.984 140.101 ;
     RECT  146.736 139.909 148.512 140.101 ;
     RECT  142.176 139.717 143.112 141.059 ;
     RECT  137.4 137.363 137.712 141.301 ;
     RECT  140.64 137.893 140.664 141.301 ;
     RECT  144.96 140.101 148.512 141.301 ;
     RECT  144.288 141.301 148.512 141.587 ;
     RECT  149.568 139.139 149.592 141.685 ;
     RECT  142.8 141.059 143.112 141.781 ;
     RECT  144.288 141.587 146.76 141.781 ;
     RECT  137.4 141.301 137.832 142.211 ;
     RECT  142.8 141.781 146.76 142.405 ;
     RECT  140.64 141.301 141.336 142.547 ;
     RECT  136.176 140.197 136.2 142.741 ;
     RECT  135.744 142.741 136.2 142.787 ;
     RECT  142.608 142.405 146.76 142.979 ;
     RECT  148.08 141.587 148.512 142.979 ;
     RECT  146.736 142.979 146.76 143.171 ;
     RECT  142.608 142.979 145.512 143.269 ;
     RECT  142.512 143.269 145.512 143.795 ;
     RECT  133.392 143.989 133.416 144.037 ;
     RECT  140.64 142.547 141.096 144.277 ;
     RECT  149.568 141.685 149.784 144.467 ;
     RECT  140.112 144.277 141.096 144.757 ;
     RECT  133.392 144.037 133.992 144.899 ;
     RECT  149.76 144.467 149.784 144.901 ;
     RECT  149.76 144.901 149.88 144.947 ;
     RECT  142.608 143.795 145.512 145.333 ;
     RECT  140.112 144.757 141.144 145.571 ;
     RECT  135.744 142.787 135.768 145.619 ;
     RECT  149.856 144.947 149.88 145.907 ;
     RECT  148.2 142.979 148.512 145.909 ;
     RECT  133.968 144.899 133.992 146.003 ;
     RECT  148.2 145.909 148.728 146.243 ;
     RECT  140.448 145.571 141.144 146.437 ;
     RECT  142.464 145.333 145.512 146.437 ;
     RECT  151.008 142.453 151.032 146.531 ;
     RECT  137.4 142.211 137.712 146.677 ;
     RECT  153.6 2.151 153.912 147.301 ;
     RECT  140.448 146.437 145.512 147.827 ;
     RECT  152.352 147.589 152.376 147.973 ;
     RECT  153.36 147.301 153.912 147.973 ;
     RECT  137.4 146.677 137.832 148.115 ;
     RECT  135.936 148.117 135.96 148.165 ;
     RECT  146.496 147.829 146.52 148.597 ;
     RECT  149.904 147.253 149.928 148.739 ;
     RECT  137.4 148.115 137.712 149.173 ;
     RECT  132 2.151 132.312 149.317 ;
     RECT  135.552 148.165 135.96 149.317 ;
     RECT  137.4 149.173 137.832 149.317 ;
     RECT  152.352 147.973 153.912 149.363 ;
     RECT  140.64 147.827 145.512 149.365 ;
     RECT  146.496 148.597 146.904 149.365 ;
     RECT  132 149.317 132.984 149.413 ;
     RECT  132 149.413 133.608 149.459 ;
     RECT  135.072 149.317 135.96 149.747 ;
     RECT  137.4 149.317 137.928 150.035 ;
     RECT  135.072 149.747 135.672 150.467 ;
     RECT  133.584 149.459 133.608 150.515 ;
     RECT  135.648 150.467 135.672 150.851 ;
     RECT  132 149.459 132.312 150.997 ;
     RECT  152.688 149.363 153.912 151.429 ;
     RECT  131.328 150.997 132.312 151.619 ;
     RECT  140.64 149.365 146.904 151.907 ;
     RECT  148.2 146.243 148.512 152.053 ;
     RECT  128.928 151.573 128.952 152.149 ;
     RECT  134.928 151.525 134.952 152.197 ;
     RECT  148.2 152.053 148.68 152.627 ;
     RECT  137.4 150.035 137.832 152.773 ;
     RECT  152.64 151.429 153.912 152.819 ;
     RECT  140.64 151.907 146.376 153.301 ;
     RECT  148.2 152.627 148.512 153.301 ;
     RECT  128.928 152.149 129.864 153.395 ;
     RECT  129.696 153.395 129.864 153.731 ;
     RECT  132 151.619 132.312 153.925 ;
     RECT  156.288 153.061 156.312 153.971 ;
     RECT  140.64 153.301 148.512 154.019 ;
     RECT  134.928 152.197 135.096 154.117 ;
     RECT  134.544 154.117 135.096 154.163 ;
     RECT  132 153.925 133.128 154.405 ;
     RECT  134.544 154.163 134.952 154.405 ;
     RECT  159 2.151 159.312 154.405 ;
     RECT  157.296 152.965 157.32 154.499 ;
     RECT  132 154.405 134.952 154.547 ;
     RECT  132 154.547 132.312 154.549 ;
     RECT  129.696 153.731 129.72 154.883 ;
     RECT  158.64 154.405 159.312 154.981 ;
     RECT  135.936 154.405 135.96 155.027 ;
     RECT  151.008 153.013 151.032 155.029 ;
     RECT  150.384 155.029 151.032 155.075 ;
     RECT  133.632 154.547 134.952 155.123 ;
     RECT  133.632 155.123 134.76 155.315 ;
     RECT  148.2 154.019 148.512 155.413 ;
     RECT  131.04 154.549 132.312 155.651 ;
     RECT  133.632 155.315 133.656 155.845 ;
     RECT  133.344 155.845 133.656 155.891 ;
     RECT  140.64 154.019 146.376 155.989 ;
     RECT  158.64 154.981 159.576 156.419 ;
     RECT  134.736 155.315 134.76 156.709 ;
     RECT  135.936 156.469 135.96 156.709 ;
     RECT  150.384 155.075 150.408 156.709 ;
     RECT  152.688 152.819 153.912 156.709 ;
     RECT  150.384 156.709 150.504 156.755 ;
     RECT  152.208 156.709 153.912 156.755 ;
     RECT  133.344 155.891 133.368 156.803 ;
     RECT  140.64 155.989 146.568 156.803 ;
     RECT  152.208 156.755 152.232 156.995 ;
     RECT  148.08 155.413 148.512 157.045 ;
     RECT  132 155.651 132.312 157.237 ;
     RECT  140.64 156.803 146.472 157.331 ;
     RECT  159 156.419 159.576 157.523 ;
     RECT  134.736 156.709 135.96 157.861 ;
     RECT  150.48 156.755 150.504 157.861 ;
     RECT  150.48 157.861 151.224 157.907 ;
     RECT  154.944 157.285 154.968 157.909 ;
     RECT  128.592 154.309 128.616 158.003 ;
     RECT  134.736 157.861 136.392 158.051 ;
     RECT  154.944 157.909 155.736 158.243 ;
     RECT  157.872 157.861 157.896 158.341 ;
     RECT  157.632 158.341 157.896 158.387 ;
     RECT  130.032 158.293 130.056 158.389 ;
     RECT  157.632 158.387 157.656 158.389 ;
     RECT  134.064 158.389 134.088 158.533 ;
     RECT  135.6 158.051 136.392 158.579 ;
     RECT  147.792 157.045 148.512 159.011 ;
     RECT  130.032 158.389 130.104 159.059 ;
     RECT  133.968 158.533 134.088 159.059 ;
     RECT  153.36 156.755 153.912 159.059 ;
     RECT  155.232 158.243 155.736 159.059 ;
     RECT  133.968 159.059 133.992 159.107 ;
     RECT  130.032 159.059 130.056 159.155 ;
     RECT  131.808 157.237 132.312 159.155 ;
     RECT  137.4 152.773 138.648 159.493 ;
     RECT  135.936 158.579 136.392 159.635 ;
     RECT  140.64 157.331 146.376 159.635 ;
     RECT  157.152 158.389 157.656 159.731 ;
     RECT  145.488 159.635 146.376 159.781 ;
     RECT  148.08 159.011 148.512 160.021 ;
     RECT  137.4 159.493 139.128 160.211 ;
     RECT  134.496 160.021 134.52 160.213 ;
     RECT  155.232 159.059 155.688 160.307 ;
     RECT  133.968 160.213 134.52 160.787 ;
     RECT  148.08 160.021 149.448 160.787 ;
     RECT  151.2 157.907 151.224 160.835 ;
     RECT  157.92 160.021 157.944 161.077 ;
     RECT  155.232 160.307 155.256 161.123 ;
     RECT  153.6 159.059 153.912 161.269 ;
     RECT  157.344 161.077 157.944 161.363 ;
     RECT  132 159.155 132.312 161.797 ;
     RECT  0.144 161.605 0.168 161.987 ;
     RECT  121.2 2.151 121.512 162.085 ;
     RECT  122.88 160.597 122.904 162.085 ;
     RECT  121.2 162.085 122.904 162.131 ;
     RECT  153.6 161.269 154.008 162.181 ;
     RECT  133.968 160.787 133.992 162.323 ;
     RECT  157.344 161.363 157.368 162.419 ;
     RECT  140.64 159.635 144.312 162.421 ;
     RECT  148.08 160.787 148.512 162.421 ;
     RECT  137.4 160.211 138.648 162.469 ;
     RECT  139.68 162.421 144.312 162.469 ;
     RECT  150.576 161.845 150.6 162.707 ;
     RECT  135.936 159.635 135.96 162.899 ;
     RECT  137.4 162.469 144.312 162.947 ;
     RECT  152.736 162.181 154.008 162.949 ;
     RECT  152.736 162.949 155.688 163.043 ;
     RECT  153.264 163.043 155.688 163.235 ;
     RECT  128.544 160.309 128.568 163.285 ;
     RECT  132 161.797 132.84 163.523 ;
     RECT  123.744 162.709 123.768 163.525 ;
     RECT  126.6 2.151 126.912 163.525 ;
     RECT  128.544 163.285 128.76 163.525 ;
     RECT  129.84 162.757 129.864 163.525 ;
     RECT  140.016 162.947 144.312 163.619 ;
     RECT  148.08 162.421 148.632 163.715 ;
     RECT  137.4 162.947 138.984 163.813 ;
     RECT  99.6 2.151 99.912 164.101 ;
     RECT  150.48 163.525 150.504 164.291 ;
     RECT  153.6 163.235 155.688 164.339 ;
     RECT  157.92 163.525 157.944 164.483 ;
     RECT  153.6 164.339 154.776 164.531 ;
     RECT  159 157.523 159.312 164.533 ;
     RECT  105 2.151 105.312 164.677 ;
     RECT  140.016 163.619 141.24 164.677 ;
     RECT  142.512 163.619 144.312 164.677 ;
     RECT  123.744 163.525 124.536 164.725 ;
     RECT  159 164.533 159.528 164.725 ;
     RECT  103.536 164.293 103.56 164.771 ;
     RECT  126.6 163.525 129.864 164.771 ;
     RECT  153.6 164.531 154.728 164.869 ;
     RECT  140.016 164.677 144.312 165.107 ;
     RECT  153.504 164.869 154.728 165.155 ;
     RECT  128.112 164.771 129.864 165.205 ;
     RECT  123.696 164.725 124.536 165.253 ;
     RECT  104.832 164.677 105.312 165.347 ;
     RECT  128.112 165.205 130.296 165.347 ;
     RECT  98.64 164.101 99.912 165.589 ;
     RECT  149.808 164.917 149.832 165.827 ;
     RECT  156.096 164.869 156.12 165.829 ;
     RECT  158.448 164.725 159.528 165.923 ;
     RECT  105 165.347 105.312 165.925 ;
     RECT  158.448 165.923 159.312 165.971 ;
     RECT  145.488 159.781 146.568 165.973 ;
     RECT  148.08 163.715 148.512 165.973 ;
     RECT  153.504 165.155 153.912 165.973 ;
     RECT  128.112 165.347 129 166.115 ;
     RECT  126.6 164.771 126.912 166.117 ;
     RECT  137.04 163.813 138.984 166.259 ;
     RECT  140.208 165.107 144.312 166.261 ;
     RECT  105 165.925 105.912 166.357 ;
     RECT  123.696 165.253 125.256 166.451 ;
     RECT  137.04 166.259 137.712 166.499 ;
     RECT  151.056 164.869 151.08 166.499 ;
     RECT  156.096 165.829 156.792 166.499 ;
     RECT  124.56 166.451 125.256 166.691 ;
     RECT  140.208 166.261 144.504 166.693 ;
     RECT  145.488 165.973 148.512 166.693 ;
     RECT  115.8 2.151 116.112 166.885 ;
     RECT  130.272 165.347 130.296 166.931 ;
     RECT  160.848 165.829 160.872 167.029 ;
     RECT  126.6 166.117 127.128 167.075 ;
     RECT  140.208 166.693 148.512 167.125 ;
     RECT  134.544 166.981 134.568 167.173 ;
     RECT  156.768 166.499 156.792 167.221 ;
     RECT  157.824 166.453 157.848 167.221 ;
     RECT  156.768 167.221 157.848 167.267 ;
     RECT  104.304 166.357 105.912 167.315 ;
     RECT  114.912 166.885 116.112 167.365 ;
     RECT  137.4 166.499 137.712 167.461 ;
     RECT  137.28 167.461 137.712 167.557 ;
     RECT  140.016 167.125 148.512 167.603 ;
     RECT  160.464 167.029 160.872 167.603 ;
     RECT  140.304 167.603 148.512 167.651 ;
     RECT  148.08 167.651 148.512 167.749 ;
     RECT  134.544 167.173 134.952 167.843 ;
     RECT  148.08 167.749 149.16 168.035 ;
     RECT  104.592 167.315 105.912 168.037 ;
     RECT  121.2 162.131 121.944 168.085 ;
     RECT  125.232 166.691 125.256 168.085 ;
     RECT  128.544 166.115 129 168.085 ;
     RECT  128.208 168.085 129 168.131 ;
     RECT  151.248 166.981 151.272 168.131 ;
     RECT  101.52 168.037 101.544 168.133 ;
     RECT  101.472 168.133 101.544 168.613 ;
     RECT  137.04 167.557 137.712 168.661 ;
     RECT  138.72 166.259 138.984 168.661 ;
     RECT  140.304 167.651 147.096 168.661 ;
     RECT  98.496 165.589 99.912 168.755 ;
     RECT  156.768 167.267 157.704 168.755 ;
     RECT  121.2 168.085 121.992 168.803 ;
     RECT  114.912 167.365 116.376 168.851 ;
     RECT  126.6 167.075 127.08 168.851 ;
     RECT  129.648 169.045 129.672 169.091 ;
     RECT  148.2 168.035 149.16 169.139 ;
     RECT  98.496 168.755 98.52 169.189 ;
     RECT  104.592 168.037 106.152 169.189 ;
     RECT  132 163.523 132.312 169.189 ;
     RECT  125.136 168.085 125.256 169.237 ;
     RECT  131.616 169.189 132.312 169.237 ;
     RECT  128.208 168.131 128.568 169.331 ;
     RECT  156.768 168.755 156.792 169.333 ;
     RECT  126.6 168.851 127.032 169.379 ;
     RECT  152.016 169.333 152.04 169.475 ;
     RECT  156.576 169.333 156.792 169.475 ;
     RECT  159 165.971 159.312 169.669 ;
     RECT  160.464 167.603 160.488 169.669 ;
     RECT  159 169.669 160.488 169.715 ;
     RECT  126.6 169.379 126.912 169.717 ;
     RECT  140.064 168.661 147.096 169.765 ;
     RECT  128.544 169.331 128.568 169.813 ;
     RECT  129.648 169.091 129.669 169.813 ;
     RECT  100.944 168.613 101.544 169.907 ;
     RECT  122.496 169.141 122.52 169.907 ;
     RECT  124.704 169.237 125.256 169.907 ;
     RECT  98.112 169.189 98.52 169.957 ;
     RECT  125.136 169.907 125.256 170.291 ;
     RECT  110.4 2.151 110.712 170.293 ;
     RECT  102.96 168.853 102.984 170.389 ;
     RECT  126.432 169.717 126.912 170.389 ;
     RECT  131.376 169.237 132.312 170.389 ;
     RECT  126.336 170.389 126.912 170.485 ;
     RECT  102.528 170.389 102.984 170.533 ;
     RECT  104.592 169.189 106.392 170.533 ;
     RECT  102.528 170.533 106.392 170.965 ;
     RECT  128.544 169.813 129.669 171.011 ;
     RECT  131.376 170.389 133.128 171.059 ;
     RECT  148.2 169.139 149.112 171.253 ;
     RECT  99.6 168.755 99.912 171.349 ;
     RECT  110.4 170.293 111.48 171.541 ;
     RECT  134.928 167.843 134.952 171.541 ;
     RECT  137.04 168.661 138.984 171.541 ;
     RECT  140.016 169.765 147.096 171.541 ;
     RECT  159 169.715 160.2 171.541 ;
     RECT  110.4 171.541 111.72 171.587 ;
     RECT  123.648 170.389 123.672 172.069 ;
     RECT  125.232 170.291 125.256 172.069 ;
     RECT  98.112 169.957 98.616 172.115 ;
     RECT  102.528 170.965 106.632 172.163 ;
     RECT  123.648 172.069 125.256 172.163 ;
     RECT  102.528 172.163 106.392 172.355 ;
     RECT  137.04 171.541 147.096 172.501 ;
     RECT  148.2 171.253 149.208 172.501 ;
     RECT  121.2 168.803 121.512 172.597 ;
     RECT  153.072 165.973 153.912 172.645 ;
     RECT  102.624 172.355 106.392 172.835 ;
     RECT  126.288 170.485 126.912 172.979 ;
     RECT  134.928 171.541 135.672 172.981 ;
     RECT  137.04 172.501 149.208 172.981 ;
     RECT  101.52 169.907 101.544 173.027 ;
     RECT  99.6 171.349 100.008 173.029 ;
     RECT  131.376 171.059 132.312 173.123 ;
     RECT  157.824 169.237 157.848 173.125 ;
     RECT  159 171.541 160.344 173.125 ;
     RECT  157.824 173.125 160.344 173.171 ;
     RECT  98.448 172.115 98.616 173.221 ;
     RECT  99.6 173.029 100.296 173.221 ;
     RECT  102.624 172.835 105.912 173.267 ;
     RECT  152.304 172.645 153.912 173.269 ;
     RECT  123.648 172.163 124.296 173.315 ;
     RECT  126.432 172.979 126.912 173.315 ;
     RECT  151.344 173.269 153.912 173.411 ;
     RECT  121.2 172.597 121.608 173.459 ;
     RECT  98.448 173.221 100.296 173.509 ;
     RECT  123.648 173.315 124.248 173.749 ;
     RECT  128.544 171.011 128.568 173.749 ;
     RECT  98.304 173.509 100.296 173.797 ;
     RECT  131.616 173.123 132.312 173.987 ;
     RECT  158.4 173.171 160.344 173.987 ;
     RECT  98.304 173.797 101.016 174.227 ;
     RECT  102.816 173.267 105.912 174.373 ;
     RECT  132 173.987 132.312 174.373 ;
     RECT  133.392 173.797 133.416 174.373 ;
     RECT  123.408 173.749 124.248 174.467 ;
     RECT  152.304 173.411 153.912 174.467 ;
     RECT  158.88 173.987 160.344 174.467 ;
     RECT  99.168 174.227 101.016 174.517 ;
     RECT  152.304 174.467 152.328 174.611 ;
     RECT  134.928 172.981 149.208 175.043 ;
     RECT  156.768 169.475 156.792 175.043 ;
     RECT  102.816 174.373 106.152 175.091 ;
     RECT  123.408 174.467 123.432 175.091 ;
     RECT  102.816 175.091 103.128 175.427 ;
     RECT  158.88 174.467 159.312 175.429 ;
     RECT  160.32 174.467 160.344 175.429 ;
     RECT  121.2 173.459 121.512 175.525 ;
     RECT  158.88 175.429 160.344 175.619 ;
     RECT  135.888 175.043 149.208 175.715 ;
     RECT  99.168 174.517 101.208 175.813 ;
     RECT  158.88 175.619 160.008 175.907 ;
     RECT  126.6 173.315 126.912 175.909 ;
     RECT  128.352 173.749 128.568 175.909 ;
     RECT  132 174.373 133.416 176.005 ;
     RECT  99.168 175.813 101.88 176.147 ;
     RECT  156.576 175.861 156.6 176.197 ;
     RECT  156.192 176.197 156.6 176.243 ;
     RECT  99.6 176.147 101.88 176.629 ;
     RECT  153.6 174.467 153.912 176.677 ;
     RECT  99.6 176.629 102.024 176.723 ;
     RECT  104.256 175.091 106.152 176.723 ;
     RECT  139.296 175.715 149.208 176.723 ;
     RECT  156.192 176.243 156.216 176.723 ;
     RECT  159 175.907 160.008 176.723 ;
     RECT  134.592 175.525 134.616 176.771 ;
     RECT  120.816 175.525 121.512 176.915 ;
     RECT  135.888 175.715 138.072 177.157 ;
     RECT  152.736 176.677 153.912 177.157 ;
     RECT  135.888 177.157 138.312 177.205 ;
     RECT  139.296 176.723 149.064 177.205 ;
     RECT  152.064 177.157 153.912 177.347 ;
     RECT  101.856 176.723 102.024 177.493 ;
     RECT  110.4 171.587 110.712 177.733 ;
     RECT  99.6 176.723 100.104 177.779 ;
     RECT  152.256 177.347 153.912 177.781 ;
     RECT  126.6 175.909 128.568 177.971 ;
     RECT  99.6 177.779 100.056 178.019 ;
     RECT  152.256 177.781 154.872 178.115 ;
     RECT  101.856 177.493 102.12 178.117 ;
     RECT  99.6 178.019 100.008 178.261 ;
     RECT  104.4 176.723 106.152 178.357 ;
     RECT  121.2 176.915 121.512 178.357 ;
     RECT  122.976 176.101 123 178.357 ;
     RECT  99.504 178.261 100.008 178.405 ;
     RECT  101.28 178.117 102.12 178.691 ;
     RECT  110.304 177.733 110.712 178.933 ;
     RECT  111.696 171.587 111.72 178.933 ;
     RECT  153.6 178.115 154.872 178.933 ;
     RECT  99.36 178.405 100.008 179.125 ;
     RECT  104.4 178.357 106.392 179.411 ;
     RECT  121.2 178.357 123 179.461 ;
     RECT  124.08 178.261 124.104 179.461 ;
     RECT  103.104 175.427 103.128 179.653 ;
     RECT  101.952 178.691 102.12 179.699 ;
     RECT  102.096 179.699 102.12 179.891 ;
     RECT  132 176.005 133.512 179.893 ;
     RECT  125.424 178.549 125.448 179.987 ;
     RECT  114.912 168.851 116.112 180.179 ;
     RECT  121.2 179.461 124.104 180.179 ;
     RECT  132 179.893 133.656 180.181 ;
     RECT  153.6 178.933 154.92 180.227 ;
     RECT  155.952 178.357 155.976 180.227 ;
     RECT  132 180.181 134.136 180.373 ;
     RECT  110.304 178.933 111.72 180.421 ;
     RECT  98.448 179.125 100.008 180.563 ;
     RECT  108.672 178.933 108.696 180.755 ;
     RECT  0.288 179.461 0.312 180.805 ;
     RECT  130.992 180.085 131.016 180.853 ;
     RECT  132 180.373 134.184 180.853 ;
     RECT  135.888 177.205 149.064 180.947 ;
     RECT  128.208 177.971 128.568 180.949 ;
     RECT  129.651 171.011 129.669 180.949 ;
     RECT  130.992 180.853 134.184 181.139 ;
     RECT  130.992 181.139 131.016 181.187 ;
     RECT  98.448 180.563 98.472 181.237 ;
     RECT  132 181.139 134.184 181.237 ;
     RECT  97.344 178.357 97.368 181.429 ;
     RECT  97.008 181.429 97.368 181.475 ;
     RECT  103.104 179.653 103.992 181.573 ;
     RECT  105 179.411 106.392 181.573 ;
     RECT  110.304 180.421 111.768 181.573 ;
     RECT  128.208 180.949 129.669 181.573 ;
     RECT  99.504 180.563 100.008 181.619 ;
     RECT  123.792 180.179 124.104 181.619 ;
     RECT  135.888 180.947 148.968 181.717 ;
     RECT  103.104 181.573 106.392 181.765 ;
     RECT  103.104 181.765 106.68 181.811 ;
     RECT  132 181.237 134.52 181.811 ;
     RECT  0.288 180.805 0.36 181.909 ;
     RECT  0.24 181.909 0.36 182.149 ;
     RECT  128.208 181.573 130.008 182.243 ;
     RECT  110.208 181.573 111.768 182.291 ;
     RECT  0.192 182.149 0.36 182.341 ;
     RECT  99.6 181.619 100.008 182.341 ;
     RECT  97.008 181.475 97.032 182.435 ;
     RECT  124.08 181.619 124.104 182.627 ;
     RECT  0.144 182.341 0.36 182.675 ;
     RECT  110.208 182.291 111.72 182.675 ;
     RECT  103.104 181.811 105.528 182.869 ;
     RECT  106.656 181.811 106.68 182.869 ;
     RECT  103.104 182.869 106.68 182.917 ;
     RECT  107.856 181.621 107.88 182.917 ;
     RECT  129.651 182.243 130.008 183.013 ;
     RECT  98.352 181.237 98.472 183.155 ;
     RECT  99.6 182.341 100.536 183.253 ;
     RECT  129.651 183.013 130.68 183.347 ;
     RECT  128.208 182.243 128.568 183.397 ;
     RECT  129.651 183.347 130.344 183.397 ;
     RECT  103.104 182.917 107.88 183.493 ;
     RECT  0.192 182.675 0.36 183.685 ;
     RECT  126.6 177.971 126.912 183.781 ;
     RECT  124.8 182.917 124.824 183.827 ;
     RECT  128.208 183.397 130.344 183.827 ;
     RECT  99.6 183.253 100.632 184.021 ;
     RECT  153.6 180.227 154.872 184.021 ;
     RECT  110.4 182.675 111.72 184.069 ;
     RECT  103.104 183.493 108.168 184.163 ;
     RECT  0.144 183.685 0.36 184.261 ;
     RECT  103.104 184.163 106.68 184.355 ;
     RECT  126.048 183.781 126.912 184.451 ;
     RECT  152.256 178.115 152.28 184.501 ;
     RECT  152.112 184.501 152.28 184.547 ;
     RECT  98.448 183.155 98.472 184.645 ;
     RECT  110.4 184.069 112.152 184.739 ;
     RECT  110.4 184.739 111.96 184.741 ;
     RECT  98.352 184.645 98.472 184.789 ;
     RECT  99.6 184.021 100.92 185.027 ;
     RECT  108.144 184.163 108.168 185.029 ;
     RECT  153.36 184.021 154.872 185.171 ;
     RECT  159 176.723 159.312 185.221 ;
     RECT  153.6 185.171 154.872 185.315 ;
     RECT  103.968 184.355 106.68 185.317 ;
     RECT  108.144 185.029 108.312 185.365 ;
     RECT  0.144 184.261 0.552 185.411 ;
     RECT  108.048 185.365 108.312 185.411 ;
     RECT  94.2 2.151 94.512 185.413 ;
     RECT  150.48 184.645 150.504 185.413 ;
     RECT  121.2 180.179 122.76 185.555 ;
     RECT  2.4 2.151 2.712 185.701 ;
     RECT  103.632 185.317 106.68 185.797 ;
     RECT  108.048 185.411 108.168 185.797 ;
     RECT  0.24 185.411 0.552 185.843 ;
     RECT  99.6 185.027 100.632 185.843 ;
     RECT  122.736 185.555 122.76 185.843 ;
     RECT  152.112 184.547 152.136 185.843 ;
     RECT  126.432 184.451 126.912 185.845 ;
     RECT  126.432 185.845 127.128 185.891 ;
     RECT  150.48 185.413 151.08 185.891 ;
     RECT  109.44 184.741 111.96 186.133 ;
     RECT  128.208 183.827 129.669 186.325 ;
     RECT  0.288 185.843 0.552 186.419 ;
     RECT  103.632 185.797 108.168 186.515 ;
     RECT  109.248 186.133 111.96 186.515 ;
     RECT  97.2 184.597 97.224 186.661 ;
     RECT  153.6 185.315 153.912 186.661 ;
     RECT  94.2 185.413 95.352 186.707 ;
     RECT  96.912 186.661 97.224 186.707 ;
     RECT  99.6 185.843 100.536 186.805 ;
     RECT  98.352 184.789 98.568 186.901 ;
     RECT  99.6 186.805 101.016 186.901 ;
     RECT  0.336 186.419 0.552 186.995 ;
     RECT  2.4 185.701 2.856 186.995 ;
     RECT  109.44 186.515 111.96 186.995 ;
     RECT  0.528 186.995 0.552 187.043 ;
     RECT  98.112 186.901 101.016 187.187 ;
     RECT  103.632 186.515 105.72 187.189 ;
     RECT  106.752 186.515 108.168 187.333 ;
     RECT  121.2 185.555 121.512 187.477 ;
     RECT  151.056 185.891 151.08 187.477 ;
     RECT  153.36 186.661 153.912 187.523 ;
     RECT  102.864 187.189 105.72 187.765 ;
     RECT  96.912 186.707 96.936 188.003 ;
     RECT  98.112 187.187 100.008 188.051 ;
     RECT  100.992 187.187 101.016 188.051 ;
     RECT  124.896 186.373 124.92 188.051 ;
     RECT  135.696 181.717 148.968 188.051 ;
     RECT  132 181.811 134.424 188.053 ;
     RECT  150.72 187.477 151.08 188.053 ;
     RECT  121.2 187.477 122.472 188.099 ;
     RECT  131.856 188.053 134.424 188.147 ;
     RECT  110.064 186.995 111.432 188.341 ;
     RECT  150.48 188.053 151.08 188.483 ;
     RECT  128.208 186.325 129.768 188.485 ;
     RECT  135.84 188.051 148.968 188.485 ;
     RECT  150.48 188.483 150.744 188.485 ;
     RECT  128.208 188.485 130.68 188.627 ;
     RECT  102.576 187.765 105.72 188.629 ;
     RECT  155.328 187.477 155.352 188.677 ;
     RECT  106.752 187.333 108.216 188.723 ;
     RECT  102.096 188.629 105.72 188.771 ;
     RECT  128.208 188.627 129.768 189.203 ;
     RECT  108.144 188.723 108.216 189.205 ;
     RECT  110.064 188.341 111.576 189.205 ;
     RECT  158.304 185.221 159.312 189.205 ;
     RECT  126.6 185.891 127.128 189.299 ;
     RECT  155.328 188.677 156.312 189.299 ;
     RECT  106.752 188.723 107.16 189.347 ;
     RECT  108.144 189.205 111.576 189.347 ;
     RECT  135.84 188.485 150.744 189.443 ;
     RECT  98.544 188.051 100.008 189.875 ;
     RECT  102.096 188.771 103.656 189.875 ;
     RECT  107.136 189.347 107.16 189.875 ;
     RECT  108.144 189.347 108.216 189.875 ;
     RECT  109.2 189.347 111.576 189.875 ;
     RECT  156.288 189.299 156.312 189.875 ;
     RECT  109.2 189.875 109.224 189.923 ;
     RECT  124.848 188.629 124.872 190.211 ;
     RECT  130.8 189.349 130.824 190.309 ;
     RECT  131.856 188.147 134.088 190.309 ;
     RECT  99.6 189.875 100.008 190.451 ;
     RECT  102.624 189.875 103.656 190.451 ;
     RECT  126.6 189.299 126.912 190.501 ;
     RECT  128.208 189.203 129.669 190.501 ;
     RECT  126.6 190.501 129.669 190.549 ;
     RECT  105 188.771 105.48 190.693 ;
     RECT  98.544 189.875 98.568 190.739 ;
     RECT  126.6 190.549 129.672 190.739 ;
     RECT  108.192 189.875 108.216 190.885 ;
     RECT  153.6 187.523 153.912 190.885 ;
     RECT  158.304 189.205 159.624 190.885 ;
     RECT  110.256 189.875 111.576 191.267 ;
     RECT  102.864 190.451 103.656 191.365 ;
     RECT  110.256 191.267 110.712 191.459 ;
     RECT  102.864 191.365 103.896 191.461 ;
     RECT  130.8 190.309 134.088 191.461 ;
     RECT  130.8 191.461 134.328 191.555 ;
     RECT  102.576 191.461 103.896 191.795 ;
     RECT  101.28 189.973 101.304 192.037 ;
     RECT  102.576 191.795 102.6 192.037 ;
     RECT  131.808 191.555 134.328 192.085 ;
     RECT  101.28 192.037 102.6 192.371 ;
     RECT  150.048 189.443 150.744 192.373 ;
     RECT  131.808 192.085 134.856 192.563 ;
     RECT  103.632 191.795 103.896 192.611 ;
     RECT  107.28 190.885 108.216 192.611 ;
     RECT  108.192 192.611 108.216 192.899 ;
     RECT  103.632 192.611 103.656 193.093 ;
     RECT  102.816 193.093 103.656 193.139 ;
     RECT  152.784 190.885 153.912 193.189 ;
     RECT  156.192 192.613 156.216 193.235 ;
     RECT  109.248 192.853 109.272 193.237 ;
     RECT  125.424 192.613 125.448 193.237 ;
     RECT  124.704 193.237 125.448 193.283 ;
     RECT  126.6 190.739 128.232 193.283 ;
     RECT  129.216 190.739 129.672 193.283 ;
     RECT  152.784 193.189 154.632 193.379 ;
     RECT  101.28 192.371 101.832 193.525 ;
     RECT  102.816 193.139 103.512 193.525 ;
     RECT  105 190.693 105.816 193.717 ;
     RECT  101.28 193.525 103.512 193.955 ;
     RECT  109.152 193.237 109.272 194.197 ;
     RECT  110.304 191.459 110.712 194.197 ;
     RECT  124.704 193.283 124.728 194.341 ;
     RECT  102.096 193.955 103.512 194.435 ;
     RECT  109.152 194.197 110.712 194.435 ;
     RECT  104.832 193.717 105.816 194.531 ;
     RECT  130.8 191.555 130.824 194.531 ;
     RECT  102.816 194.435 103.512 194.627 ;
     RECT  129.408 193.283 129.672 194.963 ;
     RECT  131.856 192.563 134.856 194.963 ;
     RECT  150 192.373 150.744 195.109 ;
     RECT  129.648 194.963 129.672 195.301 ;
     RECT  105 194.531 105.816 195.397 ;
     RECT  132 194.963 134.856 195.397 ;
     RECT  135.84 189.443 148.968 195.397 ;
     RECT  105 195.397 106.776 195.541 ;
     RECT  149.952 195.109 150.744 195.637 ;
     RECT  124.704 194.341 124.872 195.683 ;
     RECT  101.52 195.109 101.544 195.685 ;
     RECT  101.52 195.685 101.88 195.781 ;
     RECT  103.488 194.627 103.512 195.781 ;
     RECT  101.52 195.781 103.512 195.827 ;
     RECT  124.848 195.683 124.872 195.925 ;
     RECT  126.6 193.283 127.557 195.925 ;
     RECT  104.88 195.541 106.776 196.067 ;
     RECT  109.248 194.435 110.712 196.115 ;
     RECT  123.648 195.637 123.672 196.115 ;
     RECT  124.848 195.925 127.557 196.115 ;
     RECT  149.952 195.637 151.032 196.115 ;
     RECT  132 195.397 148.968 196.597 ;
     RECT  129.648 195.301 129.912 196.691 ;
     RECT  101.856 195.827 102.6 196.787 ;
     RECT  109.584 196.115 110.712 196.931 ;
     RECT  125.664 196.115 127.557 197.221 ;
     RECT  153.6 193.379 154.632 197.267 ;
     RECT  103.392 197.173 103.416 197.701 ;
     RECT  158.304 190.885 159.72 197.701 ;
     RECT  131.664 196.597 148.968 197.843 ;
     RECT  157.776 197.701 159.72 197.843 ;
     RECT  129.648 196.691 129.672 197.845 ;
     RECT  104.88 196.067 105.816 197.939 ;
     RECT  105 197.939 105.816 198.131 ;
     RECT  101.856 196.787 102.168 198.227 ;
     RECT  101.856 198.227 101.88 198.275 ;
     RECT  107.616 196.885 107.64 198.275 ;
     RECT  131.664 197.843 134.232 198.323 ;
     RECT  153.6 197.267 153.912 198.325 ;
     RECT  150.192 196.115 151.032 198.371 ;
     RECT  103.392 197.701 103.848 198.419 ;
     RECT  150.192 198.371 150.504 198.419 ;
     RECT  103.392 198.419 103.416 198.467 ;
     RECT  125.424 197.221 127.557 198.901 ;
     RECT  158.304 197.843 159.72 199.093 ;
     RECT  125.424 198.901 127.944 199.379 ;
     RECT  129.648 197.845 130.632 199.619 ;
     RECT  158.304 199.093 159.912 199.669 ;
     RECT  132 198.323 134.232 199.861 ;
     RECT  131.904 199.861 134.232 200.677 ;
     RECT  135.6 197.843 148.968 200.677 ;
     RECT  158.256 199.669 159.912 200.819 ;
     RECT  125.904 199.379 127.944 201.061 ;
     RECT  131.904 200.677 148.968 201.107 ;
     RECT  158.256 200.819 159.72 201.107 ;
     RECT  150.48 198.419 150.504 201.155 ;
     RECT  131.904 201.107 134.856 201.587 ;
     RECT  131.904 201.587 134.232 201.589 ;
     RECT  153.6 198.325 154.44 201.589 ;
     RECT  125.904 201.061 128.472 201.731 ;
     RECT  153.504 201.589 154.44 202.309 ;
     RECT  126 201.731 128.472 202.403 ;
     RECT  153.504 202.309 154.824 202.691 ;
     RECT  126 202.403 127.557 202.693 ;
     RECT  135.84 201.107 148.968 202.693 ;
     RECT  125.424 202.693 127.557 202.739 ;
     RECT  135.84 202.693 149.352 203.171 ;
     RECT  129.648 199.619 129.672 203.365 ;
     RECT  152.064 202.885 152.088 203.555 ;
     RECT  153.6 202.691 154.824 203.555 ;
     RECT  131.712 201.589 134.232 203.603 ;
     RECT  131.904 203.603 134.232 203.989 ;
     RECT  135.84 203.171 148.968 203.989 ;
     RECT  129.648 203.365 130.008 204.083 ;
     RECT  123.696 202.309 123.72 204.323 ;
     RECT  153.6 203.555 154.44 204.469 ;
     RECT  156.72 204.469 156.744 204.565 ;
     RECT  153.024 204.469 154.44 204.757 ;
     RECT  125.424 202.739 125.448 204.851 ;
     RECT  131.904 203.989 148.968 205.187 ;
     RECT  153.024 204.757 154.488 205.379 ;
     RECT  150.432 203.461 150.456 205.381 ;
     RECT  156.72 204.565 156.84 205.573 ;
     RECT  129.648 204.083 129.672 205.717 ;
     RECT  126.6 202.739 127.557 206.293 ;
     RECT  135.888 205.187 148.968 206.293 ;
     RECT  129.648 205.717 129.96 206.387 ;
     RECT  156.384 205.573 156.84 206.389 ;
     RECT  155.808 206.389 156.84 206.435 ;
     RECT  155.808 206.435 156.408 206.531 ;
     RECT  126 206.293 127.557 206.629 ;
     RECT  131.904 205.187 134.232 206.629 ;
     RECT  135.888 206.293 149.208 206.869 ;
     RECT  150.288 205.381 150.456 206.869 ;
     RECT  153.6 205.379 154.44 206.915 ;
     RECT  153.6 206.915 153.912 206.965 ;
     RECT  153.504 206.965 153.912 207.013 ;
     RECT  135.888 206.869 150.456 207.109 ;
     RECT  135.696 207.109 150.456 207.445 ;
     RECT  131.376 206.629 134.232 207.539 ;
     RECT  155.808 206.531 155.832 207.731 ;
     RECT  129.648 206.387 129.672 208.261 ;
     RECT  129.024 208.261 129.672 208.499 ;
     RECT  152.976 207.013 153.912 208.499 ;
     RECT  131.808 207.539 134.232 208.597 ;
     RECT  125.856 206.629 127.557 208.643 ;
     RECT  135.264 207.445 150.456 209.075 ;
     RECT  131.52 208.597 134.232 209.219 ;
     RECT  131.52 209.219 133.416 209.701 ;
     RECT  135.264 209.075 148.728 210.181 ;
     RECT  149.952 209.075 150.456 210.181 ;
     RECT  130.944 209.701 133.416 210.371 ;
     RECT  153.024 208.499 153.912 210.371 ;
     RECT  158.304 201.107 159.72 210.371 ;
     RECT  157.296 210.325 157.32 210.373 ;
     RECT  158.304 210.371 159.312 210.373 ;
     RECT  157.296 210.373 159.312 210.515 ;
     RECT  135.264 210.181 150.456 210.707 ;
     RECT  157.728 210.515 159.312 210.755 ;
     RECT  135.264 210.707 135.288 210.947 ;
     RECT  156.144 209.701 156.168 211.093 ;
     RECT  136.656 210.707 150.456 211.139 ;
     RECT  129.024 208.499 129.048 211.235 ;
     RECT  136.656 211.139 149.352 211.475 ;
     RECT  136.992 211.475 149.352 211.523 ;
     RECT  156.144 211.093 156.6 211.813 ;
     RECT  155.856 211.813 156.6 212.005 ;
     RECT  150.432 211.139 150.456 212.245 ;
     RECT  136.992 211.523 148.872 212.579 ;
     RECT  136.992 212.579 145.032 212.675 ;
     RECT  146.448 212.579 148.872 212.675 ;
     RECT  155.856 212.005 156.792 212.675 ;
     RECT  150.048 212.245 150.456 212.771 ;
     RECT  128.832 212.581 128.856 213.203 ;
     RECT  150.432 212.771 150.456 213.203 ;
     RECT  158.304 210.755 159.312 213.251 ;
     RECT  155.856 212.675 155.88 213.397 ;
     RECT  151.92 211.045 151.944 213.493 ;
     RECT  151.632 213.493 151.944 213.539 ;
     RECT  126.6 208.643 127.557 213.589 ;
     RECT  136.992 212.675 140.808 213.731 ;
     RECT  146.784 212.675 148.872 214.355 ;
     RECT  151.632 213.539 151.656 214.355 ;
     RECT  154.992 213.397 155.88 214.355 ;
     RECT  126.6 213.589 128.376 214.787 ;
     RECT  155.856 214.355 155.88 214.931 ;
     RECT  136.992 213.731 138.072 215.027 ;
     RECT  153.6 210.371 153.912 215.269 ;
     RECT  131.52 210.371 133.416 215.413 ;
     RECT  135.696 214.213 135.72 215.507 ;
     RECT  131.088 215.413 133.416 216.083 ;
     RECT  139.104 213.731 140.808 216.085 ;
     RECT  129.264 214.789 129.288 216.179 ;
     RECT  157.728 215.653 157.752 216.899 ;
     RECT  134.448 216.181 134.472 217.331 ;
     RECT  152.64 215.269 153.912 217.811 ;
     RECT  146.784 214.355 148.728 218.821 ;
     RECT  126.6 214.787 128.28 218.867 ;
     RECT  153.504 217.811 153.912 218.915 ;
     RECT  126.6 218.867 128.232 219.107 ;
     RECT  146.784 218.821 149.352 219.301 ;
     RECT  146.736 219.301 149.352 219.491 ;
     RECT  150.432 218.821 150.456 219.491 ;
     RECT  148.2 219.491 149.352 220.115 ;
     RECT  131.52 216.083 133.416 220.643 ;
     RECT  129.984 219.973 130.008 220.645 ;
     RECT  141.888 212.675 145.032 220.931 ;
     RECT  129.984 220.645 130.488 221.125 ;
     RECT  146.736 219.491 147.048 221.171 ;
     RECT  141.888 220.931 144.456 221.219 ;
     RECT  148.2 220.115 148.68 221.219 ;
     RECT  131.904 220.643 133.416 221.221 ;
     RECT  129.984 221.125 130.536 221.459 ;
     RECT  147.024 221.171 147.048 221.747 ;
     RECT  130.512 221.459 130.536 221.749 ;
     RECT  130.512 221.749 130.632 222.275 ;
     RECT  130.608 222.275 130.632 222.323 ;
     RECT  148.2 221.219 148.512 222.421 ;
     RECT  131.904 221.221 133.944 222.611 ;
     RECT  139.104 216.085 140.904 222.805 ;
     RECT  137.4 215.027 138.072 223.381 ;
     RECT  139.104 222.805 140.952 223.381 ;
     RECT  142.08 221.219 144.456 223.381 ;
     RECT  131.904 222.611 133.8 223.909 ;
     RECT  131.808 223.909 133.8 224.051 ;
     RECT  136.752 223.381 138.072 224.291 ;
     RECT  139.104 223.381 144.456 224.291 ;
     RECT  139.104 224.291 143.112 224.435 ;
     RECT  145.632 223.957 145.656 225.347 ;
     RECT  131.808 224.051 133.416 225.685 ;
     RECT  131.808 225.685 133.896 225.827 ;
     RECT  139.104 224.435 140.952 225.923 ;
     RECT  148.2 222.421 149.208 226.117 ;
     RECT  139.104 225.923 140.808 226.691 ;
     RECT  148.2 226.117 149.352 227.411 ;
     RECT  128.832 226.165 128.856 227.459 ;
     RECT  142.08 224.435 143.112 227.507 ;
     RECT  144.096 224.291 144.456 227.509 ;
     RECT  132 225.827 133.896 227.653 ;
     RECT  145.632 226.981 145.656 227.987 ;
     RECT  153.6 218.915 153.912 227.989 ;
     RECT  142.56 227.507 143.112 228.083 ;
     RECT  142.656 228.083 143.112 228.131 ;
     RECT  152.736 227.989 153.912 228.755 ;
     RECT  132 227.653 133.944 228.853 ;
     RECT  131.856 228.853 133.944 229.045 ;
     RECT  131.856 229.045 134.568 229.093 ;
     RECT  139.44 226.691 140.808 229.669 ;
     RECT  142.704 228.131 143.112 229.669 ;
     RECT  137.4 224.291 138.072 229.717 ;
     RECT  131.424 229.093 134.568 229.859 ;
     RECT  142.56 229.669 143.112 230.245 ;
     RECT  144.096 227.509 144.6 230.245 ;
     RECT  131.856 229.859 134.568 230.915 ;
     RECT  135.6 226.693 135.624 230.915 ;
     RECT  142.56 230.245 144.6 230.963 ;
     RECT  136.8 229.717 138.072 231.011 ;
     RECT  139.44 229.669 141.528 231.061 ;
     RECT  137.4 231.011 138.072 231.443 ;
     RECT  139.2 231.061 141.528 231.443 ;
     RECT  142.704 230.963 144.6 231.443 ;
     RECT  131.904 230.915 134.568 231.445 ;
     RECT  131.904 231.445 134.664 231.587 ;
     RECT  133.392 231.587 133.656 232.019 ;
     RECT  142.704 231.443 144.456 232.019 ;
     RECT  142.704 232.019 143.112 232.021 ;
     RECT  139.44 231.443 140.808 232.067 ;
     RECT  131.904 231.587 132.312 232.501 ;
     RECT  136.176 231.925 136.2 233.171 ;
     RECT  142.608 232.021 143.112 233.365 ;
     RECT  137.4 231.443 137.712 233.413 ;
     RECT  139.44 232.067 139.464 233.413 ;
     RECT  131.04 232.501 132.312 233.651 ;
     RECT  131.904 233.651 132.312 233.653 ;
     RECT  133.392 232.019 133.416 233.653 ;
     RECT  131.904 233.653 133.416 233.699 ;
     RECT  132 233.699 133.416 233.747 ;
     RECT  144.096 232.019 144.36 233.987 ;
     RECT  145.344 233.653 145.368 234.229 ;
     RECT  145.344 234.229 145.896 234.275 ;
     RECT  132 233.747 133.224 234.899 ;
     RECT  137.4 233.413 139.464 235.093 ;
     RECT  140.448 232.067 140.808 235.141 ;
     RECT  142.224 233.365 143.112 235.141 ;
     RECT  137.28 235.093 139.464 235.811 ;
     RECT  132 234.899 132.792 236.003 ;
     RECT  145.872 234.275 145.896 236.101 ;
     RECT  145.584 236.101 145.896 236.147 ;
     RECT  144.096 233.987 144.12 236.197 ;
     RECT  140.448 235.141 143.112 236.531 ;
     RECT  137.28 235.811 137.712 236.869 ;
     RECT  144.096 236.197 144.6 237.109 ;
     RECT  145.584 236.147 145.608 237.109 ;
     RECT  144.096 237.109 145.608 237.251 ;
     RECT  139.44 235.811 139.464 237.253 ;
     RECT  140.448 236.531 140.808 237.253 ;
     RECT  135.552 236.869 137.712 237.349 ;
     RECT  135.264 237.349 137.712 237.395 ;
     RECT  145.584 237.251 145.608 237.971 ;
     RECT  148.2 227.411 148.512 237.973 ;
     RECT  142.224 236.531 143.112 238.213 ;
     RECT  144.096 237.251 144.12 238.213 ;
     RECT  135.264 237.395 135.288 238.259 ;
     RECT  142.176 238.213 144.12 238.787 ;
     RECT  136.512 237.395 137.712 238.835 ;
     RECT  142.464 238.787 144.12 239.941 ;
     RECT  139.44 237.253 140.808 240.035 ;
     RECT  141.888 239.941 144.12 240.035 ;
     RECT  148.08 237.973 148.512 240.133 ;
     RECT  139.44 240.035 140.472 240.229 ;
     RECT  141.888 240.035 143.112 240.901 ;
     RECT  139.152 240.229 140.472 241.045 ;
     RECT  141.696 240.901 143.112 241.045 ;
     RECT  144.096 240.035 144.12 241.093 ;
     RECT  147.696 240.133 148.512 241.139 ;
     RECT  139.152 241.045 143.112 241.715 ;
     RECT  140.928 241.715 143.112 242.291 ;
     RECT  139.152 241.715 139.944 242.389 ;
     RECT  146.592 240.181 146.616 242.581 ;
     RECT  145.728 242.581 146.616 242.627 ;
     RECT  144.096 241.093 144.264 242.675 ;
     RECT  139.104 242.389 139.944 242.773 ;
     RECT  140.928 242.291 141.72 242.773 ;
     RECT  142.704 242.291 143.112 242.773 ;
     RECT  144.096 242.675 144.12 242.773 ;
     RECT  142.704 242.773 144.12 243.685 ;
     RECT  138.96 242.773 141.72 243.731 ;
     RECT  145.728 242.627 145.752 243.875 ;
     RECT  137.4 238.835 137.712 243.877 ;
     RECT  138.96 243.731 138.984 244.019 ;
     RECT  137.28 243.877 137.712 244.595 ;
     RECT  142.704 243.685 144.6 244.693 ;
     RECT  142.704 244.693 144.792 244.739 ;
     RECT  140.784 243.731 141.72 245.077 ;
     RECT  142.704 244.739 143.112 245.077 ;
     RECT  140.784 245.077 143.112 246.133 ;
     RECT  139.968 246.133 143.112 246.275 ;
     RECT  140.832 246.275 143.112 246.419 ;
     RECT  144.096 244.739 144.792 246.611 ;
     RECT  141.312 246.419 143.112 247.379 ;
     RECT  141.312 247.379 141.336 248.003 ;
     RECT  144.768 246.611 144.792 248.003 ;
     RECT  132 236.003 132.312 258.757 ;
     RECT  126.6 219.107 127.557 276.469 ;
     RECT  126.6 276.469 127.56 276.515 ;
     RECT  2.4 186.995 2.712 369.369 ;
     RECT  7.8 2.151 8.112 369.369 ;
     RECT  13.2 2.151 13.512 369.369 ;
     RECT  18.6 2.151 18.912 369.369 ;
     RECT  24 2.151 24.312 369.369 ;
     RECT  29.4 2.151 29.712 369.369 ;
     RECT  34.8 2.151 35.112 369.369 ;
     RECT  40.2 2.151 40.512 369.369 ;
     RECT  45.6 2.151 45.912 369.369 ;
     RECT  51 2.151 51.312 369.369 ;
     RECT  56.4 2.151 56.712 369.369 ;
     RECT  61.8 2.151 62.112 369.369 ;
     RECT  67.2 2.151 67.512 369.369 ;
     RECT  72.6 2.151 72.912 369.369 ;
     RECT  78 2.151 78.312 369.369 ;
     RECT  83.4 2.151 83.712 369.369 ;
     RECT  88.8 2.151 89.112 369.369 ;
     RECT  94.2 186.707 94.512 369.369 ;
     RECT  99.6 190.451 99.912 369.369 ;
     RECT  105 198.131 105.312 369.369 ;
     RECT  110.4 196.931 110.712 369.369 ;
     RECT  115.8 180.179 116.112 369.369 ;
     RECT  121.2 188.099 121.512 369.369 ;
     RECT  126.6 276.515 126.912 369.369 ;
     RECT  137.4 244.595 137.712 369.369 ;
     RECT  142.8 247.379 143.112 369.369 ;
     RECT  148.2 241.139 148.512 369.369 ;
     RECT  153.6 228.755 153.912 369.369 ;
     RECT  159 213.251 159.312 369.369 ;
     RECT  164.4 2.151 164.712 369.369 ;
     RECT  169.8 2.151 170.112 369.369 ;
     RECT  175.2 2.151 175.512 369.369 ;
     RECT  180.6 2.151 180.912 369.369 ;
     RECT  186 2.151 186.312 369.369 ;
     RECT  191.4 2.151 191.712 369.369 ;
     RECT  196.8 2.151 197.112 369.369 ;
     RECT  202.2 2.151 202.512 369.369 ;
     RECT  207.6 2.151 207.912 369.369 ;
     RECT  213 2.151 213.312 369.369 ;
     RECT  218.4 2.151 218.712 369.369 ;
     RECT  223.8 2.151 224.112 369.369 ;
     RECT  229.2 2.151 229.512 369.369 ;
     RECT  234.6 2.151 234.912 369.369 ;
     RECT  240 2.151 240.312 369.369 ;
     RECT  245.4 2.151 245.712 369.369 ;
     RECT  2.4 369.369 2.52 369.383 ;
     RECT  7.8 369.369 7.92 369.383 ;
     RECT  13.2 369.369 13.32 369.383 ;
     RECT  18.6 369.369 18.72 369.383 ;
     RECT  24 369.369 24.12 369.383 ;
     RECT  29.4 369.369 29.52 369.383 ;
     RECT  34.8 369.369 34.92 369.383 ;
     RECT  40.2 369.369 40.32 369.383 ;
     RECT  45.6 369.369 45.72 369.383 ;
     RECT  51 369.369 51.12 369.383 ;
     RECT  56.4 369.369 56.52 369.383 ;
     RECT  61.8 369.369 61.92 369.383 ;
     RECT  67.2 369.369 67.32 369.383 ;
     RECT  72.6 369.369 72.72 369.383 ;
     RECT  78 369.369 78.12 369.383 ;
     RECT  83.4 369.369 83.52 369.383 ;
     RECT  88.8 369.369 88.92 369.383 ;
     RECT  94.2 369.369 94.32 369.383 ;
     RECT  99.6 369.369 99.72 369.383 ;
     RECT  105 369.369 105.12 369.383 ;
     RECT  110.4 369.369 110.52 369.383 ;
     RECT  115.8 369.369 115.92 369.383 ;
     RECT  121.2 369.369 121.32 369.383 ;
     RECT  126.6 369.369 126.72 369.383 ;
     RECT  132 258.757 132.552 369.383 ;
     RECT  137.4 369.369 137.52 369.383 ;
     RECT  142.8 369.369 142.92 369.383 ;
     RECT  148.2 369.369 148.32 369.383 ;
     RECT  153.6 369.369 153.72 369.383 ;
     RECT  159 369.369 159.12 369.383 ;
     RECT  164.4 369.369 164.52 369.383 ;
     RECT  169.8 369.369 169.92 369.383 ;
     RECT  175.2 369.369 175.32 369.383 ;
     RECT  180.6 369.369 180.72 369.383 ;
     RECT  186 369.369 186.12 369.383 ;
     RECT  191.4 369.369 191.52 369.383 ;
     RECT  196.8 369.369 196.92 369.383 ;
     RECT  202.2 369.369 202.32 369.383 ;
     RECT  207.6 369.369 207.72 369.383 ;
     RECT  213 369.369 213.12 369.383 ;
     RECT  218.4 369.369 218.52 369.383 ;
     RECT  223.8 369.369 223.92 369.383 ;
     RECT  229.2 369.369 229.32 369.383 ;
     RECT  234.6 369.369 234.72 369.383 ;
     RECT  240 369.369 240.12 369.383 ;
     RECT  245.4 369.369 245.52 369.383 ;
     RECT  132.144 369.383 132.552 371.315 ;
     RECT  132.144 371.315 132.456 371.472 ;
  END
END ot_qwen_ctrl_pc_head
END LIBRARY
